VERSION 5.8 ;
BUSBITCHARS "[]" ;
DIVIDERCHAR "/" ;
UNITS
    DATABASE MICRONS 1000 ;
END UNITS

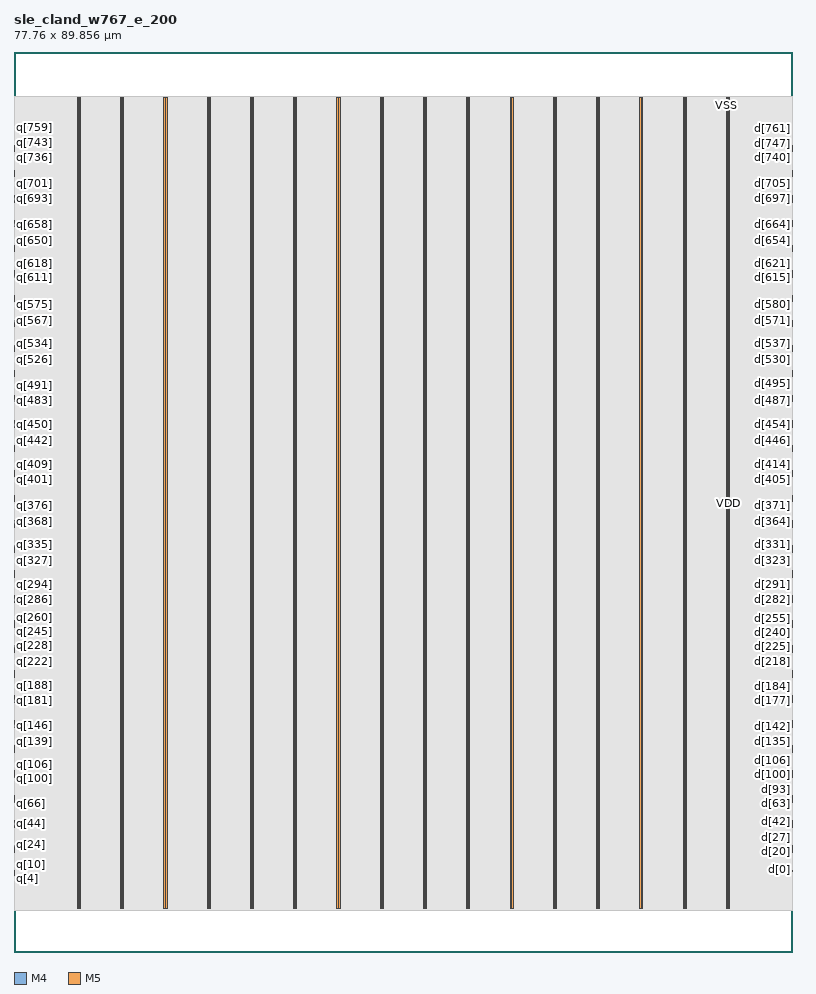
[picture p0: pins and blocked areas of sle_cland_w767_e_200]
MACRO sle_cland_w767_e_200
  FOREIGN sle_cland_w767_e_200 0 0 ;
  CLASS BLOCK ;
  SIZE 77.76 BY 89.856 ;
  PIN clk
    DIRECTION INPUT ;
    USE SIGNAL ;
    PORT
      LAYER M4 ;
        RECT  0 44.448 0.084 44.472 ;
    END
  END clk
  PIN d[0]
    DIRECTION INPUT ;
    USE SIGNAL ;
    PORT
      LAYER M4 ;
        RECT  77.676 8.256 77.76 8.28 ;
    END
  END d[0]
  PIN d[100]
    DIRECTION INPUT ;
    USE SIGNAL ;
    PORT
      LAYER M4 ;
        RECT  77.676 17.664 77.76 17.688 ;
    END
  END d[100]
  PIN d[101]
    DIRECTION INPUT ;
    USE SIGNAL ;
    PORT
      LAYER M4 ;
        RECT  77.676 17.76 77.76 17.784 ;
    END
  END d[101]
  PIN d[102]
    DIRECTION INPUT ;
    USE SIGNAL ;
    PORT
      LAYER M4 ;
        RECT  77.676 17.856 77.76 17.88 ;
    END
  END d[102]
  PIN d[103]
    DIRECTION INPUT ;
    USE SIGNAL ;
    PORT
      LAYER M4 ;
        RECT  77.676 17.952 77.76 17.976 ;
    END
  END d[103]
  PIN d[104]
    DIRECTION INPUT ;
    USE SIGNAL ;
    PORT
      LAYER M4 ;
        RECT  77.676 18.144 77.76 18.168 ;
    END
  END d[104]
  PIN d[105]
    DIRECTION INPUT ;
    USE SIGNAL ;
    PORT
      LAYER M4 ;
        RECT  77.676 18.048 77.76 18.072 ;
    END
  END d[105]
  PIN d[106]
    DIRECTION INPUT ;
    USE SIGNAL ;
    PORT
      LAYER M4 ;
        RECT  77.676 18.336 77.76 18.36 ;
    END
  END d[106]
  PIN d[107]
    DIRECTION INPUT ;
    USE SIGNAL ;
    PORT
      LAYER M4 ;
        RECT  77.676 18.24 77.76 18.264 ;
    END
  END d[107]
  PIN d[108]
    DIRECTION INPUT ;
    USE SIGNAL ;
    PORT
      LAYER M4 ;
        RECT  77.676 18.432 77.76 18.456 ;
    END
  END d[108]
  PIN d[109]
    DIRECTION INPUT ;
    USE SIGNAL ;
    PORT
      LAYER M4 ;
        RECT  77.676 18.528 77.76 18.552 ;
    END
  END d[109]
  PIN d[10]
    DIRECTION INPUT ;
    USE SIGNAL ;
    PORT
      LAYER M4 ;
        RECT  77.676 9.12 77.76 9.144 ;
    END
  END d[10]
  PIN d[110]
    DIRECTION INPUT ;
    USE SIGNAL ;
    PORT
      LAYER M4 ;
        RECT  77.676 18.624 77.76 18.648 ;
    END
  END d[110]
  PIN d[111]
    DIRECTION INPUT ;
    USE SIGNAL ;
    PORT
      LAYER M4 ;
        RECT  77.676 18.72 77.76 18.744 ;
    END
  END d[111]
  PIN d[112]
    DIRECTION INPUT ;
    USE SIGNAL ;
    PORT
      LAYER M4 ;
        RECT  77.676 18.816 77.76 18.84 ;
    END
  END d[112]
  PIN d[113]
    DIRECTION INPUT ;
    USE SIGNAL ;
    PORT
      LAYER M4 ;
        RECT  77.676 18.912 77.76 18.936 ;
    END
  END d[113]
  PIN d[114]
    DIRECTION INPUT ;
    USE SIGNAL ;
    PORT
      LAYER M4 ;
        RECT  77.676 19.008 77.76 19.032 ;
    END
  END d[114]
  PIN d[115]
    DIRECTION INPUT ;
    USE SIGNAL ;
    PORT
      LAYER M4 ;
        RECT  77.676 19.104 77.76 19.128 ;
    END
  END d[115]
  PIN d[116]
    DIRECTION INPUT ;
    USE SIGNAL ;
    PORT
      LAYER M4 ;
        RECT  77.676 19.2 77.76 19.224 ;
    END
  END d[116]
  PIN d[117]
    DIRECTION INPUT ;
    USE SIGNAL ;
    PORT
      LAYER M4 ;
        RECT  77.676 19.296 77.76 19.32 ;
    END
  END d[117]
  PIN d[118]
    DIRECTION INPUT ;
    USE SIGNAL ;
    PORT
      LAYER M4 ;
        RECT  77.676 19.392 77.76 19.416 ;
    END
  END d[118]
  PIN d[119]
    DIRECTION INPUT ;
    USE SIGNAL ;
    PORT
      LAYER M4 ;
        RECT  77.676 19.488 77.76 19.512 ;
    END
  END d[119]
  PIN d[11]
    DIRECTION INPUT ;
    USE SIGNAL ;
    PORT
      LAYER M4 ;
        RECT  77.676 9.024 77.76 9.048 ;
    END
  END d[11]
  PIN d[120]
    DIRECTION INPUT ;
    USE SIGNAL ;
    PORT
      LAYER M4 ;
        RECT  77.676 19.584 77.76 19.608 ;
    END
  END d[120]
  PIN d[121]
    DIRECTION INPUT ;
    USE SIGNAL ;
    PORT
      LAYER M4 ;
        RECT  77.676 19.68 77.76 19.704 ;
    END
  END d[121]
  PIN d[122]
    DIRECTION INPUT ;
    USE SIGNAL ;
    PORT
      LAYER M4 ;
        RECT  77.676 19.776 77.76 19.8 ;
    END
  END d[122]
  PIN d[123]
    DIRECTION INPUT ;
    USE SIGNAL ;
    PORT
      LAYER M4 ;
        RECT  77.676 19.872 77.76 19.896 ;
    END
  END d[123]
  PIN d[124]
    DIRECTION INPUT ;
    USE SIGNAL ;
    PORT
      LAYER M4 ;
        RECT  77.676 20.16 77.76 20.184 ;
    END
  END d[124]
  PIN d[125]
    DIRECTION INPUT ;
    USE SIGNAL ;
    PORT
      LAYER M4 ;
        RECT  77.676 19.968 77.76 19.992 ;
    END
  END d[125]
  PIN d[126]
    DIRECTION INPUT ;
    USE SIGNAL ;
    PORT
      LAYER M4 ;
        RECT  77.676 20.256 77.76 20.28 ;
    END
  END d[126]
  PIN d[127]
    DIRECTION INPUT ;
    USE SIGNAL ;
    PORT
      LAYER M4 ;
        RECT  77.676 20.064 77.76 20.088 ;
    END
  END d[127]
  PIN d[128]
    DIRECTION INPUT ;
    USE SIGNAL ;
    PORT
      LAYER M4 ;
        RECT  77.676 20.352 77.76 20.376 ;
    END
  END d[128]
  PIN d[129]
    DIRECTION INPUT ;
    USE SIGNAL ;
    PORT
      LAYER M4 ;
        RECT  77.676 20.448 77.76 20.472 ;
    END
  END d[129]
  PIN d[12]
    DIRECTION INPUT ;
    USE SIGNAL ;
    PORT
      LAYER M4 ;
        RECT  77.676 9.216 77.76 9.24 ;
    END
  END d[12]
  PIN d[130]
    DIRECTION INPUT ;
    USE SIGNAL ;
    PORT
      LAYER M4 ;
        RECT  77.676 20.544 77.76 20.568 ;
    END
  END d[130]
  PIN d[131]
    DIRECTION INPUT ;
    USE SIGNAL ;
    PORT
      LAYER M4 ;
        RECT  77.676 20.64 77.76 20.664 ;
    END
  END d[131]
  PIN d[132]
    DIRECTION INPUT ;
    USE SIGNAL ;
    PORT
      LAYER M4 ;
        RECT  77.676 20.736 77.76 20.76 ;
    END
  END d[132]
  PIN d[133]
    DIRECTION INPUT ;
    USE SIGNAL ;
    PORT
      LAYER M4 ;
        RECT  77.676 20.832 77.76 20.856 ;
    END
  END d[133]
  PIN d[134]
    DIRECTION INPUT ;
    USE SIGNAL ;
    PORT
      LAYER M4 ;
        RECT  77.676 20.928 77.76 20.952 ;
    END
  END d[134]
  PIN d[135]
    DIRECTION INPUT ;
    USE SIGNAL ;
    PORT
      LAYER M4 ;
        RECT  77.676 21.024 77.76 21.048 ;
    END
  END d[135]
  PIN d[136]
    DIRECTION INPUT ;
    USE SIGNAL ;
    PORT
      LAYER M4 ;
        RECT  77.676 21.12 77.76 21.144 ;
    END
  END d[136]
  PIN d[137]
    DIRECTION INPUT ;
    USE SIGNAL ;
    PORT
      LAYER M4 ;
        RECT  77.676 21.216 77.76 21.24 ;
    END
  END d[137]
  PIN d[138]
    DIRECTION INPUT ;
    USE SIGNAL ;
    PORT
      LAYER M4 ;
        RECT  77.676 21.312 77.76 21.336 ;
    END
  END d[138]
  PIN d[139]
    DIRECTION INPUT ;
    USE SIGNAL ;
    PORT
      LAYER M4 ;
        RECT  77.676 21.408 77.76 21.432 ;
    END
  END d[139]
  PIN d[13]
    DIRECTION INPUT ;
    USE SIGNAL ;
    PORT
      LAYER M4 ;
        RECT  77.676 9.312 77.76 9.336 ;
    END
  END d[13]
  PIN d[140]
    DIRECTION INPUT ;
    USE SIGNAL ;
    PORT
      LAYER M4 ;
        RECT  77.676 21.504 77.76 21.528 ;
    END
  END d[140]
  PIN d[141]
    DIRECTION INPUT ;
    USE SIGNAL ;
    PORT
      LAYER M4 ;
        RECT  77.676 21.6 77.76 21.624 ;
    END
  END d[141]
  PIN d[142]
    DIRECTION INPUT ;
    USE SIGNAL ;
    PORT
      LAYER M4 ;
        RECT  77.676 21.696 77.76 21.72 ;
    END
  END d[142]
  PIN d[143]
    DIRECTION INPUT ;
    USE SIGNAL ;
    PORT
      LAYER M4 ;
        RECT  77.676 21.792 77.76 21.816 ;
    END
  END d[143]
  PIN d[144]
    DIRECTION INPUT ;
    USE SIGNAL ;
    PORT
      LAYER M4 ;
        RECT  77.676 21.888 77.76 21.912 ;
    END
  END d[144]
  PIN d[145]
    DIRECTION INPUT ;
    USE SIGNAL ;
    PORT
      LAYER M4 ;
        RECT  77.676 21.984 77.76 22.008 ;
    END
  END d[145]
  PIN d[146]
    DIRECTION INPUT ;
    USE SIGNAL ;
    PORT
      LAYER M4 ;
        RECT  77.676 22.176 77.76 22.2 ;
    END
  END d[146]
  PIN d[147]
    DIRECTION INPUT ;
    USE SIGNAL ;
    PORT
      LAYER M4 ;
        RECT  77.676 22.08 77.76 22.104 ;
    END
  END d[147]
  PIN d[148]
    DIRECTION INPUT ;
    USE SIGNAL ;
    PORT
      LAYER M4 ;
        RECT  77.676 22.272 77.76 22.296 ;
    END
  END d[148]
  PIN d[149]
    DIRECTION INPUT ;
    USE SIGNAL ;
    PORT
      LAYER M4 ;
        RECT  77.676 22.368 77.76 22.392 ;
    END
  END d[149]
  PIN d[14]
    DIRECTION INPUT ;
    USE SIGNAL ;
    PORT
      LAYER M4 ;
        RECT  77.676 9.504 77.76 9.528 ;
    END
  END d[14]
  PIN d[150]
    DIRECTION INPUT ;
    USE SIGNAL ;
    PORT
      LAYER M4 ;
        RECT  77.676 22.464 77.76 22.488 ;
    END
  END d[150]
  PIN d[151]
    DIRECTION INPUT ;
    USE SIGNAL ;
    PORT
      LAYER M4 ;
        RECT  77.676 22.56 77.76 22.584 ;
    END
  END d[151]
  PIN d[152]
    DIRECTION INPUT ;
    USE SIGNAL ;
    PORT
      LAYER M4 ;
        RECT  77.676 22.656 77.76 22.68 ;
    END
  END d[152]
  PIN d[153]
    DIRECTION INPUT ;
    USE SIGNAL ;
    PORT
      LAYER M4 ;
        RECT  77.676 22.752 77.76 22.776 ;
    END
  END d[153]
  PIN d[154]
    DIRECTION INPUT ;
    USE SIGNAL ;
    PORT
      LAYER M4 ;
        RECT  77.676 22.848 77.76 22.872 ;
    END
  END d[154]
  PIN d[155]
    DIRECTION INPUT ;
    USE SIGNAL ;
    PORT
      LAYER M4 ;
        RECT  77.676 22.944 77.76 22.968 ;
    END
  END d[155]
  PIN d[156]
    DIRECTION INPUT ;
    USE SIGNAL ;
    PORT
      LAYER M4 ;
        RECT  77.676 23.04 77.76 23.064 ;
    END
  END d[156]
  PIN d[157]
    DIRECTION INPUT ;
    USE SIGNAL ;
    PORT
      LAYER M4 ;
        RECT  77.676 23.136 77.76 23.16 ;
    END
  END d[157]
  PIN d[158]
    DIRECTION INPUT ;
    USE SIGNAL ;
    PORT
      LAYER M4 ;
        RECT  77.676 23.232 77.76 23.256 ;
    END
  END d[158]
  PIN d[159]
    DIRECTION INPUT ;
    USE SIGNAL ;
    PORT
      LAYER M4 ;
        RECT  77.676 23.328 77.76 23.352 ;
    END
  END d[159]
  PIN d[15]
    DIRECTION INPUT ;
    USE SIGNAL ;
    PORT
      LAYER M4 ;
        RECT  77.676 9.408 77.76 9.432 ;
    END
  END d[15]
  PIN d[160]
    DIRECTION INPUT ;
    USE SIGNAL ;
    PORT
      LAYER M4 ;
        RECT  77.676 23.424 77.76 23.448 ;
    END
  END d[160]
  PIN d[161]
    DIRECTION INPUT ;
    USE SIGNAL ;
    PORT
      LAYER M4 ;
        RECT  77.676 23.52 77.76 23.544 ;
    END
  END d[161]
  PIN d[162]
    DIRECTION INPUT ;
    USE SIGNAL ;
    PORT
      LAYER M4 ;
        RECT  77.676 23.616 77.76 23.64 ;
    END
  END d[162]
  PIN d[163]
    DIRECTION INPUT ;
    USE SIGNAL ;
    PORT
      LAYER M4 ;
        RECT  77.676 23.712 77.76 23.736 ;
    END
  END d[163]
  PIN d[164]
    DIRECTION INPUT ;
    USE SIGNAL ;
    PORT
      LAYER M4 ;
        RECT  77.676 23.808 77.76 23.832 ;
    END
  END d[164]
  PIN d[165]
    DIRECTION INPUT ;
    USE SIGNAL ;
    PORT
      LAYER M4 ;
        RECT  77.676 23.904 77.76 23.928 ;
    END
  END d[165]
  PIN d[166]
    DIRECTION INPUT ;
    USE SIGNAL ;
    PORT
      LAYER M4 ;
        RECT  77.676 24.096 77.76 24.12 ;
    END
  END d[166]
  PIN d[167]
    DIRECTION INPUT ;
    USE SIGNAL ;
    PORT
      LAYER M4 ;
        RECT  77.676 24 77.76 24.024 ;
    END
  END d[167]
  PIN d[168]
    DIRECTION INPUT ;
    USE SIGNAL ;
    PORT
      LAYER M4 ;
        RECT  77.676 24.288 77.76 24.312 ;
    END
  END d[168]
  PIN d[169]
    DIRECTION INPUT ;
    USE SIGNAL ;
    PORT
      LAYER M4 ;
        RECT  77.676 24.192 77.76 24.216 ;
    END
  END d[169]
  PIN d[16]
    DIRECTION INPUT ;
    USE SIGNAL ;
    PORT
      LAYER M4 ;
        RECT  77.676 9.6 77.76 9.624 ;
    END
  END d[16]
  PIN d[170]
    DIRECTION INPUT ;
    USE SIGNAL ;
    PORT
      LAYER M4 ;
        RECT  77.676 24.384 77.76 24.408 ;
    END
  END d[170]
  PIN d[171]
    DIRECTION INPUT ;
    USE SIGNAL ;
    PORT
      LAYER M4 ;
        RECT  77.676 24.48 77.76 24.504 ;
    END
  END d[171]
  PIN d[172]
    DIRECTION INPUT ;
    USE SIGNAL ;
    PORT
      LAYER M4 ;
        RECT  77.676 24.576 77.76 24.6 ;
    END
  END d[172]
  PIN d[173]
    DIRECTION INPUT ;
    USE SIGNAL ;
    PORT
      LAYER M4 ;
        RECT  77.676 24.672 77.76 24.696 ;
    END
  END d[173]
  PIN d[174]
    DIRECTION INPUT ;
    USE SIGNAL ;
    PORT
      LAYER M4 ;
        RECT  77.676 24.768 77.76 24.792 ;
    END
  END d[174]
  PIN d[175]
    DIRECTION INPUT ;
    USE SIGNAL ;
    PORT
      LAYER M4 ;
        RECT  77.676 24.864 77.76 24.888 ;
    END
  END d[175]
  PIN d[176]
    DIRECTION INPUT ;
    USE SIGNAL ;
    PORT
      LAYER M4 ;
        RECT  77.676 24.96 77.76 24.984 ;
    END
  END d[176]
  PIN d[177]
    DIRECTION INPUT ;
    USE SIGNAL ;
    PORT
      LAYER M4 ;
        RECT  77.676 25.056 77.76 25.08 ;
    END
  END d[177]
  PIN d[178]
    DIRECTION INPUT ;
    USE SIGNAL ;
    PORT
      LAYER M4 ;
        RECT  77.676 25.152 77.76 25.176 ;
    END
  END d[178]
  PIN d[179]
    DIRECTION INPUT ;
    USE SIGNAL ;
    PORT
      LAYER M4 ;
        RECT  77.676 25.248 77.76 25.272 ;
    END
  END d[179]
  PIN d[17]
    DIRECTION INPUT ;
    USE SIGNAL ;
    PORT
      LAYER M4 ;
        RECT  77.676 9.696 77.76 9.72 ;
    END
  END d[17]
  PIN d[180]
    DIRECTION INPUT ;
    USE SIGNAL ;
    PORT
      LAYER M4 ;
        RECT  77.676 25.344 77.76 25.368 ;
    END
  END d[180]
  PIN d[181]
    DIRECTION INPUT ;
    USE SIGNAL ;
    PORT
      LAYER M4 ;
        RECT  77.676 25.44 77.76 25.464 ;
    END
  END d[181]
  PIN d[182]
    DIRECTION INPUT ;
    USE SIGNAL ;
    PORT
      LAYER M4 ;
        RECT  77.676 25.536 77.76 25.56 ;
    END
  END d[182]
  PIN d[183]
    DIRECTION INPUT ;
    USE SIGNAL ;
    PORT
      LAYER M4 ;
        RECT  77.676 25.632 77.76 25.656 ;
    END
  END d[183]
  PIN d[184]
    DIRECTION INPUT ;
    USE SIGNAL ;
    PORT
      LAYER M4 ;
        RECT  77.676 25.728 77.76 25.752 ;
    END
  END d[184]
  PIN d[185]
    DIRECTION INPUT ;
    USE SIGNAL ;
    PORT
      LAYER M4 ;
        RECT  77.676 25.92 77.76 25.944 ;
    END
  END d[185]
  PIN d[186]
    DIRECTION INPUT ;
    USE SIGNAL ;
    PORT
      LAYER M4 ;
        RECT  77.676 25.824 77.76 25.848 ;
    END
  END d[186]
  PIN d[187]
    DIRECTION INPUT ;
    USE SIGNAL ;
    PORT
      LAYER M4 ;
        RECT  77.676 26.016 77.76 26.04 ;
    END
  END d[187]
  PIN d[188]
    DIRECTION INPUT ;
    USE SIGNAL ;
    PORT
      LAYER M4 ;
        RECT  77.676 26.208 77.76 26.232 ;
    END
  END d[188]
  PIN d[189]
    DIRECTION INPUT ;
    USE SIGNAL ;
    PORT
      LAYER M4 ;
        RECT  77.676 26.112 77.76 26.136 ;
    END
  END d[189]
  PIN d[18]
    DIRECTION INPUT ;
    USE SIGNAL ;
    PORT
      LAYER M4 ;
        RECT  77.676 9.792 77.76 9.816 ;
    END
  END d[18]
  PIN d[190]
    DIRECTION INPUT ;
    USE SIGNAL ;
    PORT
      LAYER M4 ;
        RECT  77.676 26.304 77.76 26.328 ;
    END
  END d[190]
  PIN d[191]
    DIRECTION INPUT ;
    USE SIGNAL ;
    PORT
      LAYER M4 ;
        RECT  77.676 26.4 77.76 26.424 ;
    END
  END d[191]
  PIN d[192]
    DIRECTION INPUT ;
    USE SIGNAL ;
    PORT
      LAYER M4 ;
        RECT  77.676 26.496 77.76 26.52 ;
    END
  END d[192]
  PIN d[193]
    DIRECTION INPUT ;
    USE SIGNAL ;
    PORT
      LAYER M4 ;
        RECT  77.676 26.592 77.76 26.616 ;
    END
  END d[193]
  PIN d[194]
    DIRECTION INPUT ;
    USE SIGNAL ;
    PORT
      LAYER M4 ;
        RECT  77.676 26.688 77.76 26.712 ;
    END
  END d[194]
  PIN d[195]
    DIRECTION INPUT ;
    USE SIGNAL ;
    PORT
      LAYER M4 ;
        RECT  77.676 26.784 77.76 26.808 ;
    END
  END d[195]
  PIN d[196]
    DIRECTION INPUT ;
    USE SIGNAL ;
    PORT
      LAYER M4 ;
        RECT  77.676 26.88 77.76 26.904 ;
    END
  END d[196]
  PIN d[197]
    DIRECTION INPUT ;
    USE SIGNAL ;
    PORT
      LAYER M4 ;
        RECT  77.676 26.976 77.76 27 ;
    END
  END d[197]
  PIN d[198]
    DIRECTION INPUT ;
    USE SIGNAL ;
    PORT
      LAYER M4 ;
        RECT  77.676 27.072 77.76 27.096 ;
    END
  END d[198]
  PIN d[199]
    DIRECTION INPUT ;
    USE SIGNAL ;
    PORT
      LAYER M4 ;
        RECT  77.676 27.168 77.76 27.192 ;
    END
  END d[199]
  PIN d[19]
    DIRECTION INPUT ;
    USE SIGNAL ;
    PORT
      LAYER M4 ;
        RECT  77.676 9.888 77.76 9.912 ;
    END
  END d[19]
  PIN d[1]
    DIRECTION INPUT ;
    USE SIGNAL ;
    PORT
      LAYER M4 ;
        RECT  77.676 8.064 77.76 8.088 ;
    END
  END d[1]
  PIN d[200]
    DIRECTION INPUT ;
    USE SIGNAL ;
    PORT
      LAYER M4 ;
        RECT  77.676 27.264 77.76 27.288 ;
    END
  END d[200]
  PIN d[201]
    DIRECTION INPUT ;
    USE SIGNAL ;
    PORT
      LAYER M4 ;
        RECT  77.676 27.36 77.76 27.384 ;
    END
  END d[201]
  PIN d[202]
    DIRECTION INPUT ;
    USE SIGNAL ;
    PORT
      LAYER M4 ;
        RECT  77.676 27.456 77.76 27.48 ;
    END
  END d[202]
  PIN d[203]
    DIRECTION INPUT ;
    USE SIGNAL ;
    PORT
      LAYER M4 ;
        RECT  77.676 27.552 77.76 27.576 ;
    END
  END d[203]
  PIN d[204]
    DIRECTION INPUT ;
    USE SIGNAL ;
    PORT
      LAYER M4 ;
        RECT  77.676 27.648 77.76 27.672 ;
    END
  END d[204]
  PIN d[205]
    DIRECTION INPUT ;
    USE SIGNAL ;
    PORT
      LAYER M4 ;
        RECT  77.676 27.744 77.76 27.768 ;
    END
  END d[205]
  PIN d[206]
    DIRECTION INPUT ;
    USE SIGNAL ;
    PORT
      LAYER M4 ;
        RECT  77.676 27.84 77.76 27.864 ;
    END
  END d[206]
  PIN d[207]
    DIRECTION INPUT ;
    USE SIGNAL ;
    PORT
      LAYER M4 ;
        RECT  77.676 27.936 77.76 27.96 ;
    END
  END d[207]
  PIN d[208]
    DIRECTION INPUT ;
    USE SIGNAL ;
    PORT
      LAYER M4 ;
        RECT  77.676 28.128 77.76 28.152 ;
    END
  END d[208]
  PIN d[209]
    DIRECTION INPUT ;
    USE SIGNAL ;
    PORT
      LAYER M4 ;
        RECT  77.676 28.032 77.76 28.056 ;
    END
  END d[209]
  PIN d[20]
    DIRECTION INPUT ;
    USE SIGNAL ;
    PORT
      LAYER M4 ;
        RECT  77.676 9.984 77.76 10.008 ;
    END
  END d[20]
  PIN d[210]
    DIRECTION INPUT ;
    USE SIGNAL ;
    PORT
      LAYER M4 ;
        RECT  77.676 28.224 77.76 28.248 ;
    END
  END d[210]
  PIN d[211]
    DIRECTION INPUT ;
    USE SIGNAL ;
    PORT
      LAYER M4 ;
        RECT  77.676 28.32 77.76 28.344 ;
    END
  END d[211]
  PIN d[212]
    DIRECTION INPUT ;
    USE SIGNAL ;
    PORT
      LAYER M4 ;
        RECT  77.676 28.416 77.76 28.44 ;
    END
  END d[212]
  PIN d[213]
    DIRECTION INPUT ;
    USE SIGNAL ;
    PORT
      LAYER M4 ;
        RECT  77.676 28.512 77.76 28.536 ;
    END
  END d[213]
  PIN d[214]
    DIRECTION INPUT ;
    USE SIGNAL ;
    PORT
      LAYER M4 ;
        RECT  77.676 28.608 77.76 28.632 ;
    END
  END d[214]
  PIN d[215]
    DIRECTION INPUT ;
    USE SIGNAL ;
    PORT
      LAYER M4 ;
        RECT  77.676 28.704 77.76 28.728 ;
    END
  END d[215]
  PIN d[216]
    DIRECTION INPUT ;
    USE SIGNAL ;
    PORT
      LAYER M4 ;
        RECT  77.676 28.8 77.76 28.824 ;
    END
  END d[216]
  PIN d[217]
    DIRECTION INPUT ;
    USE SIGNAL ;
    PORT
      LAYER M4 ;
        RECT  77.676 28.896 77.76 28.92 ;
    END
  END d[217]
  PIN d[218]
    DIRECTION INPUT ;
    USE SIGNAL ;
    PORT
      LAYER M4 ;
        RECT  77.676 28.992 77.76 29.016 ;
    END
  END d[218]
  PIN d[219]
    DIRECTION INPUT ;
    USE SIGNAL ;
    PORT
      LAYER M4 ;
        RECT  77.676 29.088 77.76 29.112 ;
    END
  END d[219]
  PIN d[21]
    DIRECTION INPUT ;
    USE SIGNAL ;
    PORT
      LAYER M4 ;
        RECT  77.676 10.08 77.76 10.104 ;
    END
  END d[21]
  PIN d[220]
    DIRECTION INPUT ;
    USE SIGNAL ;
    PORT
      LAYER M4 ;
        RECT  77.676 29.184 77.76 29.208 ;
    END
  END d[220]
  PIN d[221]
    DIRECTION INPUT ;
    USE SIGNAL ;
    PORT
      LAYER M4 ;
        RECT  77.676 29.28 77.76 29.304 ;
    END
  END d[221]
  PIN d[222]
    DIRECTION INPUT ;
    USE SIGNAL ;
    PORT
      LAYER M4 ;
        RECT  77.676 29.376 77.76 29.4 ;
    END
  END d[222]
  PIN d[223]
    DIRECTION INPUT ;
    USE SIGNAL ;
    PORT
      LAYER M4 ;
        RECT  77.676 29.472 77.76 29.496 ;
    END
  END d[223]
  PIN d[224]
    DIRECTION INPUT ;
    USE SIGNAL ;
    PORT
      LAYER M4 ;
        RECT  77.676 29.568 77.76 29.592 ;
    END
  END d[224]
  PIN d[225]
    DIRECTION INPUT ;
    USE SIGNAL ;
    PORT
      LAYER M4 ;
        RECT  77.676 29.664 77.76 29.688 ;
    END
  END d[225]
  PIN d[226]
    DIRECTION INPUT ;
    USE SIGNAL ;
    PORT
      LAYER M4 ;
        RECT  77.676 29.76 77.76 29.784 ;
    END
  END d[226]
  PIN d[227]
    DIRECTION INPUT ;
    USE SIGNAL ;
    PORT
      LAYER M4 ;
        RECT  77.676 29.856 77.76 29.88 ;
    END
  END d[227]
  PIN d[228]
    DIRECTION INPUT ;
    USE SIGNAL ;
    PORT
      LAYER M4 ;
        RECT  77.676 30.144 77.76 30.168 ;
    END
  END d[228]
  PIN d[229]
    DIRECTION INPUT ;
    USE SIGNAL ;
    PORT
      LAYER M4 ;
        RECT  77.676 29.952 77.76 29.976 ;
    END
  END d[229]
  PIN d[22]
    DIRECTION INPUT ;
    USE SIGNAL ;
    PORT
      LAYER M4 ;
        RECT  77.676 10.272 77.76 10.296 ;
    END
  END d[22]
  PIN d[230]
    DIRECTION INPUT ;
    USE SIGNAL ;
    PORT
      LAYER M4 ;
        RECT  77.676 30.24 77.76 30.264 ;
    END
  END d[230]
  PIN d[231]
    DIRECTION INPUT ;
    USE SIGNAL ;
    PORT
      LAYER M4 ;
        RECT  77.676 30.048 77.76 30.072 ;
    END
  END d[231]
  PIN d[232]
    DIRECTION INPUT ;
    USE SIGNAL ;
    PORT
      LAYER M4 ;
        RECT  77.676 30.336 77.76 30.36 ;
    END
  END d[232]
  PIN d[233]
    DIRECTION INPUT ;
    USE SIGNAL ;
    PORT
      LAYER M4 ;
        RECT  77.676 30.432 77.76 30.456 ;
    END
  END d[233]
  PIN d[234]
    DIRECTION INPUT ;
    USE SIGNAL ;
    PORT
      LAYER M4 ;
        RECT  77.676 30.528 77.76 30.552 ;
    END
  END d[234]
  PIN d[235]
    DIRECTION INPUT ;
    USE SIGNAL ;
    PORT
      LAYER M4 ;
        RECT  77.676 30.624 77.76 30.648 ;
    END
  END d[235]
  PIN d[236]
    DIRECTION INPUT ;
    USE SIGNAL ;
    PORT
      LAYER M4 ;
        RECT  77.676 30.72 77.76 30.744 ;
    END
  END d[236]
  PIN d[237]
    DIRECTION INPUT ;
    USE SIGNAL ;
    PORT
      LAYER M4 ;
        RECT  77.676 30.816 77.76 30.84 ;
    END
  END d[237]
  PIN d[238]
    DIRECTION INPUT ;
    USE SIGNAL ;
    PORT
      LAYER M4 ;
        RECT  77.676 30.912 77.76 30.936 ;
    END
  END d[238]
  PIN d[239]
    DIRECTION INPUT ;
    USE SIGNAL ;
    PORT
      LAYER M4 ;
        RECT  77.676 31.008 77.76 31.032 ;
    END
  END d[239]
  PIN d[23]
    DIRECTION INPUT ;
    USE SIGNAL ;
    PORT
      LAYER M4 ;
        RECT  77.676 10.176 77.76 10.2 ;
    END
  END d[23]
  PIN d[240]
    DIRECTION INPUT ;
    USE SIGNAL ;
    PORT
      LAYER M4 ;
        RECT  77.676 31.104 77.76 31.128 ;
    END
  END d[240]
  PIN d[241]
    DIRECTION INPUT ;
    USE SIGNAL ;
    PORT
      LAYER M4 ;
        RECT  77.676 31.2 77.76 31.224 ;
    END
  END d[241]
  PIN d[242]
    DIRECTION INPUT ;
    USE SIGNAL ;
    PORT
      LAYER M4 ;
        RECT  77.676 31.296 77.76 31.32 ;
    END
  END d[242]
  PIN d[243]
    DIRECTION INPUT ;
    USE SIGNAL ;
    PORT
      LAYER M4 ;
        RECT  77.676 31.392 77.76 31.416 ;
    END
  END d[243]
  PIN d[244]
    DIRECTION INPUT ;
    USE SIGNAL ;
    PORT
      LAYER M4 ;
        RECT  77.676 31.488 77.76 31.512 ;
    END
  END d[244]
  PIN d[245]
    DIRECTION INPUT ;
    USE SIGNAL ;
    PORT
      LAYER M4 ;
        RECT  77.676 31.584 77.76 31.608 ;
    END
  END d[245]
  PIN d[246]
    DIRECTION INPUT ;
    USE SIGNAL ;
    PORT
      LAYER M4 ;
        RECT  77.676 31.68 77.76 31.704 ;
    END
  END d[246]
  PIN d[247]
    DIRECTION INPUT ;
    USE SIGNAL ;
    PORT
      LAYER M4 ;
        RECT  77.676 31.872 77.76 31.896 ;
    END
  END d[247]
  PIN d[248]
    DIRECTION INPUT ;
    USE SIGNAL ;
    PORT
      LAYER M4 ;
        RECT  77.676 31.776 77.76 31.8 ;
    END
  END d[248]
  PIN d[249]
    DIRECTION INPUT ;
    USE SIGNAL ;
    PORT
      LAYER M4 ;
        RECT  77.676 31.968 77.76 31.992 ;
    END
  END d[249]
  PIN d[24]
    DIRECTION INPUT ;
    USE SIGNAL ;
    PORT
      LAYER M4 ;
        RECT  77.676 10.368 77.76 10.392 ;
    END
  END d[24]
  PIN d[250]
    DIRECTION INPUT ;
    USE SIGNAL ;
    PORT
      LAYER M4 ;
        RECT  77.676 32.16 77.76 32.184 ;
    END
  END d[250]
  PIN d[251]
    DIRECTION INPUT ;
    USE SIGNAL ;
    PORT
      LAYER M4 ;
        RECT  77.676 32.064 77.76 32.088 ;
    END
  END d[251]
  PIN d[252]
    DIRECTION INPUT ;
    USE SIGNAL ;
    PORT
      LAYER M4 ;
        RECT  77.676 32.256 77.76 32.28 ;
    END
  END d[252]
  PIN d[253]
    DIRECTION INPUT ;
    USE SIGNAL ;
    PORT
      LAYER M4 ;
        RECT  77.676 32.352 77.76 32.376 ;
    END
  END d[253]
  PIN d[254]
    DIRECTION INPUT ;
    USE SIGNAL ;
    PORT
      LAYER M4 ;
        RECT  77.676 32.448 77.76 32.472 ;
    END
  END d[254]
  PIN d[255]
    DIRECTION INPUT ;
    USE SIGNAL ;
    PORT
      LAYER M4 ;
        RECT  77.676 32.544 77.76 32.568 ;
    END
  END d[255]
  PIN d[256]
    DIRECTION INPUT ;
    USE SIGNAL ;
    PORT
      LAYER M4 ;
        RECT  77.676 32.64 77.76 32.664 ;
    END
  END d[256]
  PIN d[257]
    DIRECTION INPUT ;
    USE SIGNAL ;
    PORT
      LAYER M4 ;
        RECT  77.676 32.736 77.76 32.76 ;
    END
  END d[257]
  PIN d[258]
    DIRECTION INPUT ;
    USE SIGNAL ;
    PORT
      LAYER M4 ;
        RECT  77.676 32.832 77.76 32.856 ;
    END
  END d[258]
  PIN d[259]
    DIRECTION INPUT ;
    USE SIGNAL ;
    PORT
      LAYER M4 ;
        RECT  77.676 32.928 77.76 32.952 ;
    END
  END d[259]
  PIN d[25]
    DIRECTION INPUT ;
    USE SIGNAL ;
    PORT
      LAYER M4 ;
        RECT  77.676 10.464 77.76 10.488 ;
    END
  END d[25]
  PIN d[260]
    DIRECTION INPUT ;
    USE SIGNAL ;
    PORT
      LAYER M4 ;
        RECT  77.676 33.024 77.76 33.048 ;
    END
  END d[260]
  PIN d[261]
    DIRECTION INPUT ;
    USE SIGNAL ;
    PORT
      LAYER M4 ;
        RECT  77.676 33.12 77.76 33.144 ;
    END
  END d[261]
  PIN d[262]
    DIRECTION INPUT ;
    USE SIGNAL ;
    PORT
      LAYER M4 ;
        RECT  77.676 33.216 77.76 33.24 ;
    END
  END d[262]
  PIN d[263]
    DIRECTION INPUT ;
    USE SIGNAL ;
    PORT
      LAYER M4 ;
        RECT  77.676 33.312 77.76 33.336 ;
    END
  END d[263]
  PIN d[264]
    DIRECTION INPUT ;
    USE SIGNAL ;
    PORT
      LAYER M4 ;
        RECT  77.676 33.408 77.76 33.432 ;
    END
  END d[264]
  PIN d[265]
    DIRECTION INPUT ;
    USE SIGNAL ;
    PORT
      LAYER M4 ;
        RECT  77.676 33.504 77.76 33.528 ;
    END
  END d[265]
  PIN d[266]
    DIRECTION INPUT ;
    USE SIGNAL ;
    PORT
      LAYER M4 ;
        RECT  77.676 33.6 77.76 33.624 ;
    END
  END d[266]
  PIN d[267]
    DIRECTION INPUT ;
    USE SIGNAL ;
    PORT
      LAYER M4 ;
        RECT  77.676 33.696 77.76 33.72 ;
    END
  END d[267]
  PIN d[268]
    DIRECTION INPUT ;
    USE SIGNAL ;
    PORT
      LAYER M4 ;
        RECT  77.676 33.792 77.76 33.816 ;
    END
  END d[268]
  PIN d[269]
    DIRECTION INPUT ;
    USE SIGNAL ;
    PORT
      LAYER M4 ;
        RECT  77.676 33.888 77.76 33.912 ;
    END
  END d[269]
  PIN d[26]
    DIRECTION INPUT ;
    USE SIGNAL ;
    PORT
      LAYER M4 ;
        RECT  77.676 10.56 77.76 10.584 ;
    END
  END d[26]
  PIN d[270]
    DIRECTION INPUT ;
    USE SIGNAL ;
    PORT
      LAYER M4 ;
        RECT  77.676 34.08 77.76 34.104 ;
    END
  END d[270]
  PIN d[271]
    DIRECTION INPUT ;
    USE SIGNAL ;
    PORT
      LAYER M4 ;
        RECT  77.676 33.984 77.76 34.008 ;
    END
  END d[271]
  PIN d[272]
    DIRECTION INPUT ;
    USE SIGNAL ;
    PORT
      LAYER M4 ;
        RECT  77.676 34.176 77.76 34.2 ;
    END
  END d[272]
  PIN d[273]
    DIRECTION INPUT ;
    USE SIGNAL ;
    PORT
      LAYER M4 ;
        RECT  77.676 34.272 77.76 34.296 ;
    END
  END d[273]
  PIN d[274]
    DIRECTION INPUT ;
    USE SIGNAL ;
    PORT
      LAYER M4 ;
        RECT  77.676 34.368 77.76 34.392 ;
    END
  END d[274]
  PIN d[275]
    DIRECTION INPUT ;
    USE SIGNAL ;
    PORT
      LAYER M4 ;
        RECT  77.676 34.464 77.76 34.488 ;
    END
  END d[275]
  PIN d[276]
    DIRECTION INPUT ;
    USE SIGNAL ;
    PORT
      LAYER M4 ;
        RECT  77.676 34.56 77.76 34.584 ;
    END
  END d[276]
  PIN d[277]
    DIRECTION INPUT ;
    USE SIGNAL ;
    PORT
      LAYER M4 ;
        RECT  77.676 34.656 77.76 34.68 ;
    END
  END d[277]
  PIN d[278]
    DIRECTION INPUT ;
    USE SIGNAL ;
    PORT
      LAYER M4 ;
        RECT  77.676 34.752 77.76 34.776 ;
    END
  END d[278]
  PIN d[279]
    DIRECTION INPUT ;
    USE SIGNAL ;
    PORT
      LAYER M4 ;
        RECT  77.676 34.848 77.76 34.872 ;
    END
  END d[279]
  PIN d[27]
    DIRECTION INPUT ;
    USE SIGNAL ;
    PORT
      LAYER M4 ;
        RECT  77.676 10.656 77.76 10.68 ;
    END
  END d[27]
  PIN d[280]
    DIRECTION INPUT ;
    USE SIGNAL ;
    PORT
      LAYER M4 ;
        RECT  77.676 34.944 77.76 34.968 ;
    END
  END d[280]
  PIN d[281]
    DIRECTION INPUT ;
    USE SIGNAL ;
    PORT
      LAYER M4 ;
        RECT  77.676 35.04 77.76 35.064 ;
    END
  END d[281]
  PIN d[282]
    DIRECTION INPUT ;
    USE SIGNAL ;
    PORT
      LAYER M4 ;
        RECT  77.676 35.136 77.76 35.16 ;
    END
  END d[282]
  PIN d[283]
    DIRECTION INPUT ;
    USE SIGNAL ;
    PORT
      LAYER M4 ;
        RECT  77.676 35.232 77.76 35.256 ;
    END
  END d[283]
  PIN d[284]
    DIRECTION INPUT ;
    USE SIGNAL ;
    PORT
      LAYER M4 ;
        RECT  77.676 35.328 77.76 35.352 ;
    END
  END d[284]
  PIN d[285]
    DIRECTION INPUT ;
    USE SIGNAL ;
    PORT
      LAYER M4 ;
        RECT  77.676 35.424 77.76 35.448 ;
    END
  END d[285]
  PIN d[286]
    DIRECTION INPUT ;
    USE SIGNAL ;
    PORT
      LAYER M4 ;
        RECT  77.676 35.52 77.76 35.544 ;
    END
  END d[286]
  PIN d[287]
    DIRECTION INPUT ;
    USE SIGNAL ;
    PORT
      LAYER M4 ;
        RECT  77.676 35.616 77.76 35.64 ;
    END
  END d[287]
  PIN d[288]
    DIRECTION INPUT ;
    USE SIGNAL ;
    PORT
      LAYER M4 ;
        RECT  77.676 35.712 77.76 35.736 ;
    END
  END d[288]
  PIN d[289]
    DIRECTION INPUT ;
    USE SIGNAL ;
    PORT
      LAYER M4 ;
        RECT  77.676 35.808 77.76 35.832 ;
    END
  END d[289]
  PIN d[28]
    DIRECTION INPUT ;
    USE SIGNAL ;
    PORT
      LAYER M4 ;
        RECT  77.676 10.752 77.76 10.776 ;
    END
  END d[28]
  PIN d[290]
    DIRECTION INPUT ;
    USE SIGNAL ;
    PORT
      LAYER M4 ;
        RECT  77.676 36 77.76 36.024 ;
    END
  END d[290]
  PIN d[291]
    DIRECTION INPUT ;
    USE SIGNAL ;
    PORT
      LAYER M4 ;
        RECT  77.676 35.904 77.76 35.928 ;
    END
  END d[291]
  PIN d[292]
    DIRECTION INPUT ;
    USE SIGNAL ;
    PORT
      LAYER M4 ;
        RECT  77.676 36.192 77.76 36.216 ;
    END
  END d[292]
  PIN d[293]
    DIRECTION INPUT ;
    USE SIGNAL ;
    PORT
      LAYER M4 ;
        RECT  77.676 36.096 77.76 36.12 ;
    END
  END d[293]
  PIN d[294]
    DIRECTION INPUT ;
    USE SIGNAL ;
    PORT
      LAYER M4 ;
        RECT  77.676 36.288 77.76 36.312 ;
    END
  END d[294]
  PIN d[295]
    DIRECTION INPUT ;
    USE SIGNAL ;
    PORT
      LAYER M4 ;
        RECT  77.676 36.384 77.76 36.408 ;
    END
  END d[295]
  PIN d[296]
    DIRECTION INPUT ;
    USE SIGNAL ;
    PORT
      LAYER M4 ;
        RECT  77.676 36.48 77.76 36.504 ;
    END
  END d[296]
  PIN d[297]
    DIRECTION INPUT ;
    USE SIGNAL ;
    PORT
      LAYER M4 ;
        RECT  77.676 36.576 77.76 36.6 ;
    END
  END d[297]
  PIN d[298]
    DIRECTION INPUT ;
    USE SIGNAL ;
    PORT
      LAYER M4 ;
        RECT  77.676 36.672 77.76 36.696 ;
    END
  END d[298]
  PIN d[299]
    DIRECTION INPUT ;
    USE SIGNAL ;
    PORT
      LAYER M4 ;
        RECT  77.676 36.768 77.76 36.792 ;
    END
  END d[299]
  PIN d[29]
    DIRECTION INPUT ;
    USE SIGNAL ;
    PORT
      LAYER M4 ;
        RECT  77.676 10.848 77.76 10.872 ;
    END
  END d[29]
  PIN d[2]
    DIRECTION INPUT ;
    USE SIGNAL ;
    PORT
      LAYER M4 ;
        RECT  77.676 8.352 77.76 8.376 ;
    END
  END d[2]
  PIN d[300]
    DIRECTION INPUT ;
    USE SIGNAL ;
    PORT
      LAYER M4 ;
        RECT  77.676 36.864 77.76 36.888 ;
    END
  END d[300]
  PIN d[301]
    DIRECTION INPUT ;
    USE SIGNAL ;
    PORT
      LAYER M4 ;
        RECT  77.676 36.96 77.76 36.984 ;
    END
  END d[301]
  PIN d[302]
    DIRECTION INPUT ;
    USE SIGNAL ;
    PORT
      LAYER M4 ;
        RECT  77.676 37.056 77.76 37.08 ;
    END
  END d[302]
  PIN d[303]
    DIRECTION INPUT ;
    USE SIGNAL ;
    PORT
      LAYER M4 ;
        RECT  77.676 37.152 77.76 37.176 ;
    END
  END d[303]
  PIN d[304]
    DIRECTION INPUT ;
    USE SIGNAL ;
    PORT
      LAYER M4 ;
        RECT  77.676 37.248 77.76 37.272 ;
    END
  END d[304]
  PIN d[305]
    DIRECTION INPUT ;
    USE SIGNAL ;
    PORT
      LAYER M4 ;
        RECT  77.676 37.344 77.76 37.368 ;
    END
  END d[305]
  PIN d[306]
    DIRECTION INPUT ;
    USE SIGNAL ;
    PORT
      LAYER M4 ;
        RECT  77.676 37.44 77.76 37.464 ;
    END
  END d[306]
  PIN d[307]
    DIRECTION INPUT ;
    USE SIGNAL ;
    PORT
      LAYER M4 ;
        RECT  77.676 37.536 77.76 37.56 ;
    END
  END d[307]
  PIN d[308]
    DIRECTION INPUT ;
    USE SIGNAL ;
    PORT
      LAYER M4 ;
        RECT  77.676 37.632 77.76 37.656 ;
    END
  END d[308]
  PIN d[309]
    DIRECTION INPUT ;
    USE SIGNAL ;
    PORT
      LAYER M4 ;
        RECT  77.676 37.824 77.76 37.848 ;
    END
  END d[309]
  PIN d[30]
    DIRECTION INPUT ;
    USE SIGNAL ;
    PORT
      LAYER M4 ;
        RECT  77.676 10.944 77.76 10.968 ;
    END
  END d[30]
  PIN d[310]
    DIRECTION INPUT ;
    USE SIGNAL ;
    PORT
      LAYER M4 ;
        RECT  77.676 37.728 77.76 37.752 ;
    END
  END d[310]
  PIN d[311]
    DIRECTION INPUT ;
    USE SIGNAL ;
    PORT
      LAYER M4 ;
        RECT  77.676 37.92 77.76 37.944 ;
    END
  END d[311]
  PIN d[312]
    DIRECTION INPUT ;
    USE SIGNAL ;
    PORT
      LAYER M4 ;
        RECT  77.676 38.112 77.76 38.136 ;
    END
  END d[312]
  PIN d[313]
    DIRECTION INPUT ;
    USE SIGNAL ;
    PORT
      LAYER M4 ;
        RECT  77.676 38.016 77.76 38.04 ;
    END
  END d[313]
  PIN d[314]
    DIRECTION INPUT ;
    USE SIGNAL ;
    PORT
      LAYER M4 ;
        RECT  77.676 38.208 77.76 38.232 ;
    END
  END d[314]
  PIN d[315]
    DIRECTION INPUT ;
    USE SIGNAL ;
    PORT
      LAYER M4 ;
        RECT  77.676 38.304 77.76 38.328 ;
    END
  END d[315]
  PIN d[316]
    DIRECTION INPUT ;
    USE SIGNAL ;
    PORT
      LAYER M4 ;
        RECT  77.676 38.4 77.76 38.424 ;
    END
  END d[316]
  PIN d[317]
    DIRECTION INPUT ;
    USE SIGNAL ;
    PORT
      LAYER M4 ;
        RECT  77.676 38.496 77.76 38.52 ;
    END
  END d[317]
  PIN d[318]
    DIRECTION INPUT ;
    USE SIGNAL ;
    PORT
      LAYER M4 ;
        RECT  77.676 38.592 77.76 38.616 ;
    END
  END d[318]
  PIN d[319]
    DIRECTION INPUT ;
    USE SIGNAL ;
    PORT
      LAYER M4 ;
        RECT  77.676 38.688 77.76 38.712 ;
    END
  END d[319]
  PIN d[31]
    DIRECTION INPUT ;
    USE SIGNAL ;
    PORT
      LAYER M4 ;
        RECT  77.676 11.04 77.76 11.064 ;
    END
  END d[31]
  PIN d[320]
    DIRECTION INPUT ;
    USE SIGNAL ;
    PORT
      LAYER M4 ;
        RECT  77.676 38.784 77.76 38.808 ;
    END
  END d[320]
  PIN d[321]
    DIRECTION INPUT ;
    USE SIGNAL ;
    PORT
      LAYER M4 ;
        RECT  77.676 38.88 77.76 38.904 ;
    END
  END d[321]
  PIN d[322]
    DIRECTION INPUT ;
    USE SIGNAL ;
    PORT
      LAYER M4 ;
        RECT  77.676 38.976 77.76 39 ;
    END
  END d[322]
  PIN d[323]
    DIRECTION INPUT ;
    USE SIGNAL ;
    PORT
      LAYER M4 ;
        RECT  77.676 39.072 77.76 39.096 ;
    END
  END d[323]
  PIN d[324]
    DIRECTION INPUT ;
    USE SIGNAL ;
    PORT
      LAYER M4 ;
        RECT  77.676 39.168 77.76 39.192 ;
    END
  END d[324]
  PIN d[325]
    DIRECTION INPUT ;
    USE SIGNAL ;
    PORT
      LAYER M4 ;
        RECT  77.676 39.264 77.76 39.288 ;
    END
  END d[325]
  PIN d[326]
    DIRECTION INPUT ;
    USE SIGNAL ;
    PORT
      LAYER M4 ;
        RECT  77.676 39.36 77.76 39.384 ;
    END
  END d[326]
  PIN d[327]
    DIRECTION INPUT ;
    USE SIGNAL ;
    PORT
      LAYER M4 ;
        RECT  77.676 39.456 77.76 39.48 ;
    END
  END d[327]
  PIN d[328]
    DIRECTION INPUT ;
    USE SIGNAL ;
    PORT
      LAYER M4 ;
        RECT  77.676 39.552 77.76 39.576 ;
    END
  END d[328]
  PIN d[329]
    DIRECTION INPUT ;
    USE SIGNAL ;
    PORT
      LAYER M4 ;
        RECT  77.676 39.648 77.76 39.672 ;
    END
  END d[329]
  PIN d[32]
    DIRECTION INPUT ;
    USE SIGNAL ;
    PORT
      LAYER M4 ;
        RECT  77.676 11.136 77.76 11.16 ;
    END
  END d[32]
  PIN d[330]
    DIRECTION INPUT ;
    USE SIGNAL ;
    PORT
      LAYER M4 ;
        RECT  77.676 39.744 77.76 39.768 ;
    END
  END d[330]
  PIN d[331]
    DIRECTION INPUT ;
    USE SIGNAL ;
    PORT
      LAYER M4 ;
        RECT  77.676 39.84 77.76 39.864 ;
    END
  END d[331]
  PIN d[332]
    DIRECTION INPUT ;
    USE SIGNAL ;
    PORT
      LAYER M4 ;
        RECT  77.676 40.032 77.76 40.056 ;
    END
  END d[332]
  PIN d[333]
    DIRECTION INPUT ;
    USE SIGNAL ;
    PORT
      LAYER M4 ;
        RECT  77.676 39.936 77.76 39.96 ;
    END
  END d[333]
  PIN d[334]
    DIRECTION INPUT ;
    USE SIGNAL ;
    PORT
      LAYER M4 ;
        RECT  77.676 40.128 77.76 40.152 ;
    END
  END d[334]
  PIN d[335]
    DIRECTION INPUT ;
    USE SIGNAL ;
    PORT
      LAYER M4 ;
        RECT  77.676 40.224 77.76 40.248 ;
    END
  END d[335]
  PIN d[336]
    DIRECTION INPUT ;
    USE SIGNAL ;
    PORT
      LAYER M4 ;
        RECT  77.676 40.32 77.76 40.344 ;
    END
  END d[336]
  PIN d[337]
    DIRECTION INPUT ;
    USE SIGNAL ;
    PORT
      LAYER M4 ;
        RECT  77.676 40.416 77.76 40.44 ;
    END
  END d[337]
  PIN d[338]
    DIRECTION INPUT ;
    USE SIGNAL ;
    PORT
      LAYER M4 ;
        RECT  77.676 40.512 77.76 40.536 ;
    END
  END d[338]
  PIN d[339]
    DIRECTION INPUT ;
    USE SIGNAL ;
    PORT
      LAYER M4 ;
        RECT  77.676 40.608 77.76 40.632 ;
    END
  END d[339]
  PIN d[33]
    DIRECTION INPUT ;
    USE SIGNAL ;
    PORT
      LAYER M4 ;
        RECT  77.676 11.232 77.76 11.256 ;
    END
  END d[33]
  PIN d[340]
    DIRECTION INPUT ;
    USE SIGNAL ;
    PORT
      LAYER M4 ;
        RECT  77.676 40.704 77.76 40.728 ;
    END
  END d[340]
  PIN d[341]
    DIRECTION INPUT ;
    USE SIGNAL ;
    PORT
      LAYER M4 ;
        RECT  77.676 40.8 77.76 40.824 ;
    END
  END d[341]
  PIN d[342]
    DIRECTION INPUT ;
    USE SIGNAL ;
    PORT
      LAYER M4 ;
        RECT  77.676 40.896 77.76 40.92 ;
    END
  END d[342]
  PIN d[343]
    DIRECTION INPUT ;
    USE SIGNAL ;
    PORT
      LAYER M4 ;
        RECT  77.676 40.992 77.76 41.016 ;
    END
  END d[343]
  PIN d[344]
    DIRECTION INPUT ;
    USE SIGNAL ;
    PORT
      LAYER M4 ;
        RECT  77.676 41.088 77.76 41.112 ;
    END
  END d[344]
  PIN d[345]
    DIRECTION INPUT ;
    USE SIGNAL ;
    PORT
      LAYER M4 ;
        RECT  77.676 41.184 77.76 41.208 ;
    END
  END d[345]
  PIN d[346]
    DIRECTION INPUT ;
    USE SIGNAL ;
    PORT
      LAYER M4 ;
        RECT  77.676 41.28 77.76 41.304 ;
    END
  END d[346]
  PIN d[347]
    DIRECTION INPUT ;
    USE SIGNAL ;
    PORT
      LAYER M4 ;
        RECT  77.676 41.376 77.76 41.4 ;
    END
  END d[347]
  PIN d[348]
    DIRECTION INPUT ;
    USE SIGNAL ;
    PORT
      LAYER M4 ;
        RECT  77.676 41.472 77.76 41.496 ;
    END
  END d[348]
  PIN d[349]
    DIRECTION INPUT ;
    USE SIGNAL ;
    PORT
      LAYER M4 ;
        RECT  77.676 41.568 77.76 41.592 ;
    END
  END d[349]
  PIN d[34]
    DIRECTION INPUT ;
    USE SIGNAL ;
    PORT
      LAYER M4 ;
        RECT  77.676 11.424 77.76 11.448 ;
    END
  END d[34]
  PIN d[350]
    DIRECTION INPUT ;
    USE SIGNAL ;
    PORT
      LAYER M4 ;
        RECT  77.676 41.664 77.76 41.688 ;
    END
  END d[350]
  PIN d[351]
    DIRECTION INPUT ;
    USE SIGNAL ;
    PORT
      LAYER M4 ;
        RECT  77.676 41.856 77.76 41.88 ;
    END
  END d[351]
  PIN d[352]
    DIRECTION INPUT ;
    USE SIGNAL ;
    PORT
      LAYER M4 ;
        RECT  77.676 41.76 77.76 41.784 ;
    END
  END d[352]
  PIN d[353]
    DIRECTION INPUT ;
    USE SIGNAL ;
    PORT
      LAYER M4 ;
        RECT  77.676 41.952 77.76 41.976 ;
    END
  END d[353]
  PIN d[354]
    DIRECTION INPUT ;
    USE SIGNAL ;
    PORT
      LAYER M4 ;
        RECT  77.676 42.144 77.76 42.168 ;
    END
  END d[354]
  PIN d[355]
    DIRECTION INPUT ;
    USE SIGNAL ;
    PORT
      LAYER M4 ;
        RECT  77.676 42.048 77.76 42.072 ;
    END
  END d[355]
  PIN d[356]
    DIRECTION INPUT ;
    USE SIGNAL ;
    PORT
      LAYER M4 ;
        RECT  77.676 42.24 77.76 42.264 ;
    END
  END d[356]
  PIN d[357]
    DIRECTION INPUT ;
    USE SIGNAL ;
    PORT
      LAYER M4 ;
        RECT  77.676 42.336 77.76 42.36 ;
    END
  END d[357]
  PIN d[358]
    DIRECTION INPUT ;
    USE SIGNAL ;
    PORT
      LAYER M4 ;
        RECT  77.676 42.432 77.76 42.456 ;
    END
  END d[358]
  PIN d[359]
    DIRECTION INPUT ;
    USE SIGNAL ;
    PORT
      LAYER M4 ;
        RECT  77.676 42.528 77.76 42.552 ;
    END
  END d[359]
  PIN d[35]
    DIRECTION INPUT ;
    USE SIGNAL ;
    PORT
      LAYER M4 ;
        RECT  77.676 11.328 77.76 11.352 ;
    END
  END d[35]
  PIN d[360]
    DIRECTION INPUT ;
    USE SIGNAL ;
    PORT
      LAYER M4 ;
        RECT  77.676 42.624 77.76 42.648 ;
    END
  END d[360]
  PIN d[361]
    DIRECTION INPUT ;
    USE SIGNAL ;
    PORT
      LAYER M4 ;
        RECT  77.676 42.72 77.76 42.744 ;
    END
  END d[361]
  PIN d[362]
    DIRECTION INPUT ;
    USE SIGNAL ;
    PORT
      LAYER M4 ;
        RECT  77.676 42.816 77.76 42.84 ;
    END
  END d[362]
  PIN d[363]
    DIRECTION INPUT ;
    USE SIGNAL ;
    PORT
      LAYER M4 ;
        RECT  77.676 42.912 77.76 42.936 ;
    END
  END d[363]
  PIN d[364]
    DIRECTION INPUT ;
    USE SIGNAL ;
    PORT
      LAYER M4 ;
        RECT  77.676 43.008 77.76 43.032 ;
    END
  END d[364]
  PIN d[365]
    DIRECTION INPUT ;
    USE SIGNAL ;
    PORT
      LAYER M4 ;
        RECT  77.676 43.104 77.76 43.128 ;
    END
  END d[365]
  PIN d[366]
    DIRECTION INPUT ;
    USE SIGNAL ;
    PORT
      LAYER M4 ;
        RECT  77.676 43.2 77.76 43.224 ;
    END
  END d[366]
  PIN d[367]
    DIRECTION INPUT ;
    USE SIGNAL ;
    PORT
      LAYER M4 ;
        RECT  77.676 43.296 77.76 43.32 ;
    END
  END d[367]
  PIN d[368]
    DIRECTION INPUT ;
    USE SIGNAL ;
    PORT
      LAYER M4 ;
        RECT  77.676 43.392 77.76 43.416 ;
    END
  END d[368]
  PIN d[369]
    DIRECTION INPUT ;
    USE SIGNAL ;
    PORT
      LAYER M4 ;
        RECT  77.676 43.488 77.76 43.512 ;
    END
  END d[369]
  PIN d[36]
    DIRECTION INPUT ;
    USE SIGNAL ;
    PORT
      LAYER M4 ;
        RECT  77.676 11.52 77.76 11.544 ;
    END
  END d[36]
  PIN d[370]
    DIRECTION INPUT ;
    USE SIGNAL ;
    PORT
      LAYER M4 ;
        RECT  77.676 43.584 77.76 43.608 ;
    END
  END d[370]
  PIN d[371]
    DIRECTION INPUT ;
    USE SIGNAL ;
    PORT
      LAYER M4 ;
        RECT  77.676 43.776 77.76 43.8 ;
    END
  END d[371]
  PIN d[372]
    DIRECTION INPUT ;
    USE SIGNAL ;
    PORT
      LAYER M4 ;
        RECT  77.676 43.68 77.76 43.704 ;
    END
  END d[372]
  PIN d[373]
    DIRECTION INPUT ;
    USE SIGNAL ;
    PORT
      LAYER M4 ;
        RECT  77.676 43.872 77.76 43.896 ;
    END
  END d[373]
  PIN d[374]
    DIRECTION INPUT ;
    USE SIGNAL ;
    PORT
      LAYER M4 ;
        RECT  77.676 44.064 77.76 44.088 ;
    END
  END d[374]
  PIN d[375]
    DIRECTION INPUT ;
    USE SIGNAL ;
    PORT
      LAYER M4 ;
        RECT  77.676 43.968 77.76 43.992 ;
    END
  END d[375]
  PIN d[376]
    DIRECTION INPUT ;
    USE SIGNAL ;
    PORT
      LAYER M4 ;
        RECT  77.676 44.16 77.76 44.184 ;
    END
  END d[376]
  PIN d[377]
    DIRECTION INPUT ;
    USE SIGNAL ;
    PORT
      LAYER M4 ;
        RECT  77.676 44.256 77.76 44.28 ;
    END
  END d[377]
  PIN d[378]
    DIRECTION INPUT ;
    USE SIGNAL ;
    PORT
      LAYER M4 ;
        RECT  77.676 44.352 77.76 44.376 ;
    END
  END d[378]
  PIN d[379]
    DIRECTION INPUT ;
    USE SIGNAL ;
    PORT
      LAYER M4 ;
        RECT  77.676 44.448 77.76 44.472 ;
    END
  END d[379]
  PIN d[37]
    DIRECTION INPUT ;
    USE SIGNAL ;
    PORT
      LAYER M4 ;
        RECT  77.676 11.616 77.76 11.64 ;
    END
  END d[37]
  PIN d[380]
    DIRECTION INPUT ;
    USE SIGNAL ;
    PORT
      LAYER M4 ;
        RECT  77.676 44.544 77.76 44.568 ;
    END
  END d[380]
  PIN d[381]
    DIRECTION INPUT ;
    USE SIGNAL ;
    PORT
      LAYER M4 ;
        RECT  77.676 44.64 77.76 44.664 ;
    END
  END d[381]
  PIN d[382]
    DIRECTION INPUT ;
    USE SIGNAL ;
    PORT
      LAYER M4 ;
        RECT  77.676 44.736 77.76 44.76 ;
    END
  END d[382]
  PIN d[383]
    DIRECTION INPUT ;
    USE SIGNAL ;
    PORT
      LAYER M4 ;
        RECT  77.676 45.024 77.76 45.048 ;
    END
  END d[383]
  PIN d[384]
    DIRECTION INPUT ;
    USE SIGNAL ;
    PORT
      LAYER M4 ;
        RECT  77.676 45.12 77.76 45.144 ;
    END
  END d[384]
  PIN d[385]
    DIRECTION INPUT ;
    USE SIGNAL ;
    PORT
      LAYER M4 ;
        RECT  77.676 45.216 77.76 45.24 ;
    END
  END d[385]
  PIN d[386]
    DIRECTION INPUT ;
    USE SIGNAL ;
    PORT
      LAYER M4 ;
        RECT  77.676 45.312 77.76 45.336 ;
    END
  END d[386]
  PIN d[387]
    DIRECTION INPUT ;
    USE SIGNAL ;
    PORT
      LAYER M4 ;
        RECT  77.676 45.408 77.76 45.432 ;
    END
  END d[387]
  PIN d[388]
    DIRECTION INPUT ;
    USE SIGNAL ;
    PORT
      LAYER M4 ;
        RECT  77.676 45.504 77.76 45.528 ;
    END
  END d[388]
  PIN d[389]
    DIRECTION INPUT ;
    USE SIGNAL ;
    PORT
      LAYER M4 ;
        RECT  77.676 45.6 77.76 45.624 ;
    END
  END d[389]
  PIN d[38]
    DIRECTION INPUT ;
    USE SIGNAL ;
    PORT
      LAYER M4 ;
        RECT  77.676 11.712 77.76 11.736 ;
    END
  END d[38]
  PIN d[390]
    DIRECTION INPUT ;
    USE SIGNAL ;
    PORT
      LAYER M4 ;
        RECT  77.676 45.696 77.76 45.72 ;
    END
  END d[390]
  PIN d[391]
    DIRECTION INPUT ;
    USE SIGNAL ;
    PORT
      LAYER M4 ;
        RECT  77.676 45.792 77.76 45.816 ;
    END
  END d[391]
  PIN d[392]
    DIRECTION INPUT ;
    USE SIGNAL ;
    PORT
      LAYER M4 ;
        RECT  77.676 45.888 77.76 45.912 ;
    END
  END d[392]
  PIN d[393]
    DIRECTION INPUT ;
    USE SIGNAL ;
    PORT
      LAYER M4 ;
        RECT  77.676 46.08 77.76 46.104 ;
    END
  END d[393]
  PIN d[394]
    DIRECTION INPUT ;
    USE SIGNAL ;
    PORT
      LAYER M4 ;
        RECT  77.676 45.984 77.76 46.008 ;
    END
  END d[394]
  PIN d[395]
    DIRECTION INPUT ;
    USE SIGNAL ;
    PORT
      LAYER M4 ;
        RECT  77.676 46.176 77.76 46.2 ;
    END
  END d[395]
  PIN d[396]
    DIRECTION INPUT ;
    USE SIGNAL ;
    PORT
      LAYER M4 ;
        RECT  77.676 46.272 77.76 46.296 ;
    END
  END d[396]
  PIN d[397]
    DIRECTION INPUT ;
    USE SIGNAL ;
    PORT
      LAYER M4 ;
        RECT  77.676 46.368 77.76 46.392 ;
    END
  END d[397]
  PIN d[398]
    DIRECTION INPUT ;
    USE SIGNAL ;
    PORT
      LAYER M4 ;
        RECT  77.676 46.464 77.76 46.488 ;
    END
  END d[398]
  PIN d[399]
    DIRECTION INPUT ;
    USE SIGNAL ;
    PORT
      LAYER M4 ;
        RECT  77.676 46.56 77.76 46.584 ;
    END
  END d[399]
  PIN d[39]
    DIRECTION INPUT ;
    USE SIGNAL ;
    PORT
      LAYER M4 ;
        RECT  77.676 11.808 77.76 11.832 ;
    END
  END d[39]
  PIN d[3]
    DIRECTION INPUT ;
    USE SIGNAL ;
    PORT
      LAYER M4 ;
        RECT  77.676 8.16 77.76 8.184 ;
    END
  END d[3]
  PIN d[400]
    DIRECTION INPUT ;
    USE SIGNAL ;
    PORT
      LAYER M4 ;
        RECT  77.676 46.656 77.76 46.68 ;
    END
  END d[400]
  PIN d[401]
    DIRECTION INPUT ;
    USE SIGNAL ;
    PORT
      LAYER M4 ;
        RECT  77.676 46.752 77.76 46.776 ;
    END
  END d[401]
  PIN d[402]
    DIRECTION INPUT ;
    USE SIGNAL ;
    PORT
      LAYER M4 ;
        RECT  77.676 46.848 77.76 46.872 ;
    END
  END d[402]
  PIN d[403]
    DIRECTION INPUT ;
    USE SIGNAL ;
    PORT
      LAYER M4 ;
        RECT  77.676 46.944 77.76 46.968 ;
    END
  END d[403]
  PIN d[404]
    DIRECTION INPUT ;
    USE SIGNAL ;
    PORT
      LAYER M4 ;
        RECT  77.676 47.04 77.76 47.064 ;
    END
  END d[404]
  PIN d[405]
    DIRECTION INPUT ;
    USE SIGNAL ;
    PORT
      LAYER M4 ;
        RECT  77.676 47.136 77.76 47.16 ;
    END
  END d[405]
  PIN d[406]
    DIRECTION INPUT ;
    USE SIGNAL ;
    PORT
      LAYER M4 ;
        RECT  77.676 47.232 77.76 47.256 ;
    END
  END d[406]
  PIN d[407]
    DIRECTION INPUT ;
    USE SIGNAL ;
    PORT
      LAYER M4 ;
        RECT  77.676 47.328 77.76 47.352 ;
    END
  END d[407]
  PIN d[408]
    DIRECTION INPUT ;
    USE SIGNAL ;
    PORT
      LAYER M4 ;
        RECT  77.676 47.424 77.76 47.448 ;
    END
  END d[408]
  PIN d[409]
    DIRECTION INPUT ;
    USE SIGNAL ;
    PORT
      LAYER M4 ;
        RECT  77.676 47.52 77.76 47.544 ;
    END
  END d[409]
  PIN d[40]
    DIRECTION INPUT ;
    USE SIGNAL ;
    PORT
      LAYER M4 ;
        RECT  77.676 11.904 77.76 11.928 ;
    END
  END d[40]
  PIN d[410]
    DIRECTION INPUT ;
    USE SIGNAL ;
    PORT
      LAYER M4 ;
        RECT  77.676 47.616 77.76 47.64 ;
    END
  END d[410]
  PIN d[411]
    DIRECTION INPUT ;
    USE SIGNAL ;
    PORT
      LAYER M4 ;
        RECT  77.676 47.712 77.76 47.736 ;
    END
  END d[411]
  PIN d[412]
    DIRECTION INPUT ;
    USE SIGNAL ;
    PORT
      LAYER M4 ;
        RECT  77.676 47.808 77.76 47.832 ;
    END
  END d[412]
  PIN d[413]
    DIRECTION INPUT ;
    USE SIGNAL ;
    PORT
      LAYER M4 ;
        RECT  77.676 48 77.76 48.024 ;
    END
  END d[413]
  PIN d[414]
    DIRECTION INPUT ;
    USE SIGNAL ;
    PORT
      LAYER M4 ;
        RECT  77.676 47.904 77.76 47.928 ;
    END
  END d[414]
  PIN d[415]
    DIRECTION INPUT ;
    USE SIGNAL ;
    PORT
      LAYER M4 ;
        RECT  77.676 48.096 77.76 48.12 ;
    END
  END d[415]
  PIN d[416]
    DIRECTION INPUT ;
    USE SIGNAL ;
    PORT
      LAYER M4 ;
        RECT  77.676 48.288 77.76 48.312 ;
    END
  END d[416]
  PIN d[417]
    DIRECTION INPUT ;
    USE SIGNAL ;
    PORT
      LAYER M4 ;
        RECT  77.676 48.192 77.76 48.216 ;
    END
  END d[417]
  PIN d[418]
    DIRECTION INPUT ;
    USE SIGNAL ;
    PORT
      LAYER M4 ;
        RECT  77.676 48.384 77.76 48.408 ;
    END
  END d[418]
  PIN d[419]
    DIRECTION INPUT ;
    USE SIGNAL ;
    PORT
      LAYER M4 ;
        RECT  77.676 48.48 77.76 48.504 ;
    END
  END d[419]
  PIN d[41]
    DIRECTION INPUT ;
    USE SIGNAL ;
    PORT
      LAYER M4 ;
        RECT  77.676 12 77.76 12.024 ;
    END
  END d[41]
  PIN d[420]
    DIRECTION INPUT ;
    USE SIGNAL ;
    PORT
      LAYER M4 ;
        RECT  77.676 48.576 77.76 48.6 ;
    END
  END d[420]
  PIN d[421]
    DIRECTION INPUT ;
    USE SIGNAL ;
    PORT
      LAYER M4 ;
        RECT  77.676 48.672 77.76 48.696 ;
    END
  END d[421]
  PIN d[422]
    DIRECTION INPUT ;
    USE SIGNAL ;
    PORT
      LAYER M4 ;
        RECT  77.676 48.768 77.76 48.792 ;
    END
  END d[422]
  PIN d[423]
    DIRECTION INPUT ;
    USE SIGNAL ;
    PORT
      LAYER M4 ;
        RECT  77.676 48.864 77.76 48.888 ;
    END
  END d[423]
  PIN d[424]
    DIRECTION INPUT ;
    USE SIGNAL ;
    PORT
      LAYER M4 ;
        RECT  77.676 48.96 77.76 48.984 ;
    END
  END d[424]
  PIN d[425]
    DIRECTION INPUT ;
    USE SIGNAL ;
    PORT
      LAYER M4 ;
        RECT  77.676 49.056 77.76 49.08 ;
    END
  END d[425]
  PIN d[426]
    DIRECTION INPUT ;
    USE SIGNAL ;
    PORT
      LAYER M4 ;
        RECT  77.676 49.152 77.76 49.176 ;
    END
  END d[426]
  PIN d[427]
    DIRECTION INPUT ;
    USE SIGNAL ;
    PORT
      LAYER M4 ;
        RECT  77.676 49.248 77.76 49.272 ;
    END
  END d[427]
  PIN d[428]
    DIRECTION INPUT ;
    USE SIGNAL ;
    PORT
      LAYER M4 ;
        RECT  77.676 49.344 77.76 49.368 ;
    END
  END d[428]
  PIN d[429]
    DIRECTION INPUT ;
    USE SIGNAL ;
    PORT
      LAYER M4 ;
        RECT  77.676 49.44 77.76 49.464 ;
    END
  END d[429]
  PIN d[42]
    DIRECTION INPUT ;
    USE SIGNAL ;
    PORT
      LAYER M4 ;
        RECT  77.676 12.192 77.76 12.216 ;
    END
  END d[42]
  PIN d[430]
    DIRECTION INPUT ;
    USE SIGNAL ;
    PORT
      LAYER M4 ;
        RECT  77.676 49.536 77.76 49.56 ;
    END
  END d[430]
  PIN d[431]
    DIRECTION INPUT ;
    USE SIGNAL ;
    PORT
      LAYER M4 ;
        RECT  77.676 49.632 77.76 49.656 ;
    END
  END d[431]
  PIN d[432]
    DIRECTION INPUT ;
    USE SIGNAL ;
    PORT
      LAYER M4 ;
        RECT  77.676 49.728 77.76 49.752 ;
    END
  END d[432]
  PIN d[433]
    DIRECTION INPUT ;
    USE SIGNAL ;
    PORT
      LAYER M4 ;
        RECT  77.676 49.92 77.76 49.944 ;
    END
  END d[433]
  PIN d[434]
    DIRECTION INPUT ;
    USE SIGNAL ;
    PORT
      LAYER M4 ;
        RECT  77.676 49.824 77.76 49.848 ;
    END
  END d[434]
  PIN d[435]
    DIRECTION INPUT ;
    USE SIGNAL ;
    PORT
      LAYER M4 ;
        RECT  77.676 50.112 77.76 50.136 ;
    END
  END d[435]
  PIN d[436]
    DIRECTION INPUT ;
    USE SIGNAL ;
    PORT
      LAYER M4 ;
        RECT  77.676 50.016 77.76 50.04 ;
    END
  END d[436]
  PIN d[437]
    DIRECTION INPUT ;
    USE SIGNAL ;
    PORT
      LAYER M4 ;
        RECT  77.676 50.208 77.76 50.232 ;
    END
  END d[437]
  PIN d[438]
    DIRECTION INPUT ;
    USE SIGNAL ;
    PORT
      LAYER M4 ;
        RECT  77.676 50.304 77.76 50.328 ;
    END
  END d[438]
  PIN d[439]
    DIRECTION INPUT ;
    USE SIGNAL ;
    PORT
      LAYER M4 ;
        RECT  77.676 50.4 77.76 50.424 ;
    END
  END d[439]
  PIN d[43]
    DIRECTION INPUT ;
    USE SIGNAL ;
    PORT
      LAYER M4 ;
        RECT  77.676 12.096 77.76 12.12 ;
    END
  END d[43]
  PIN d[440]
    DIRECTION INPUT ;
    USE SIGNAL ;
    PORT
      LAYER M4 ;
        RECT  77.676 50.496 77.76 50.52 ;
    END
  END d[440]
  PIN d[441]
    DIRECTION INPUT ;
    USE SIGNAL ;
    PORT
      LAYER M4 ;
        RECT  77.676 50.592 77.76 50.616 ;
    END
  END d[441]
  PIN d[442]
    DIRECTION INPUT ;
    USE SIGNAL ;
    PORT
      LAYER M4 ;
        RECT  77.676 50.688 77.76 50.712 ;
    END
  END d[442]
  PIN d[443]
    DIRECTION INPUT ;
    USE SIGNAL ;
    PORT
      LAYER M4 ;
        RECT  77.676 50.784 77.76 50.808 ;
    END
  END d[443]
  PIN d[444]
    DIRECTION INPUT ;
    USE SIGNAL ;
    PORT
      LAYER M4 ;
        RECT  77.676 50.88 77.76 50.904 ;
    END
  END d[444]
  PIN d[445]
    DIRECTION INPUT ;
    USE SIGNAL ;
    PORT
      LAYER M4 ;
        RECT  77.676 50.976 77.76 51 ;
    END
  END d[445]
  PIN d[446]
    DIRECTION INPUT ;
    USE SIGNAL ;
    PORT
      LAYER M4 ;
        RECT  77.676 51.072 77.76 51.096 ;
    END
  END d[446]
  PIN d[447]
    DIRECTION INPUT ;
    USE SIGNAL ;
    PORT
      LAYER M4 ;
        RECT  77.676 51.168 77.76 51.192 ;
    END
  END d[447]
  PIN d[448]
    DIRECTION INPUT ;
    USE SIGNAL ;
    PORT
      LAYER M4 ;
        RECT  77.676 51.264 77.76 51.288 ;
    END
  END d[448]
  PIN d[449]
    DIRECTION INPUT ;
    USE SIGNAL ;
    PORT
      LAYER M4 ;
        RECT  77.676 51.36 77.76 51.384 ;
    END
  END d[449]
  PIN d[44]
    DIRECTION INPUT ;
    USE SIGNAL ;
    PORT
      LAYER M4 ;
        RECT  77.676 12.384 77.76 12.408 ;
    END
  END d[44]
  PIN d[450]
    DIRECTION INPUT ;
    USE SIGNAL ;
    PORT
      LAYER M4 ;
        RECT  77.676 51.456 77.76 51.48 ;
    END
  END d[450]
  PIN d[451]
    DIRECTION INPUT ;
    USE SIGNAL ;
    PORT
      LAYER M4 ;
        RECT  77.676 51.552 77.76 51.576 ;
    END
  END d[451]
  PIN d[452]
    DIRECTION INPUT ;
    USE SIGNAL ;
    PORT
      LAYER M4 ;
        RECT  77.676 51.648 77.76 51.672 ;
    END
  END d[452]
  PIN d[453]
    DIRECTION INPUT ;
    USE SIGNAL ;
    PORT
      LAYER M4 ;
        RECT  77.676 51.744 77.76 51.768 ;
    END
  END d[453]
  PIN d[454]
    DIRECTION INPUT ;
    USE SIGNAL ;
    PORT
      LAYER M4 ;
        RECT  77.676 51.84 77.76 51.864 ;
    END
  END d[454]
  PIN d[455]
    DIRECTION INPUT ;
    USE SIGNAL ;
    PORT
      LAYER M4 ;
        RECT  77.676 52.032 77.76 52.056 ;
    END
  END d[455]
  PIN d[456]
    DIRECTION INPUT ;
    USE SIGNAL ;
    PORT
      LAYER M4 ;
        RECT  77.676 51.936 77.76 51.96 ;
    END
  END d[456]
  PIN d[457]
    DIRECTION INPUT ;
    USE SIGNAL ;
    PORT
      LAYER M4 ;
        RECT  77.676 52.128 77.76 52.152 ;
    END
  END d[457]
  PIN d[458]
    DIRECTION INPUT ;
    USE SIGNAL ;
    PORT
      LAYER M4 ;
        RECT  77.676 52.224 77.76 52.248 ;
    END
  END d[458]
  PIN d[459]
    DIRECTION INPUT ;
    USE SIGNAL ;
    PORT
      LAYER M4 ;
        RECT  77.676 52.32 77.76 52.344 ;
    END
  END d[459]
  PIN d[45]
    DIRECTION INPUT ;
    USE SIGNAL ;
    PORT
      LAYER M4 ;
        RECT  77.676 12.288 77.76 12.312 ;
    END
  END d[45]
  PIN d[460]
    DIRECTION INPUT ;
    USE SIGNAL ;
    PORT
      LAYER M4 ;
        RECT  77.676 52.416 77.76 52.44 ;
    END
  END d[460]
  PIN d[461]
    DIRECTION INPUT ;
    USE SIGNAL ;
    PORT
      LAYER M4 ;
        RECT  77.676 52.512 77.76 52.536 ;
    END
  END d[461]
  PIN d[462]
    DIRECTION INPUT ;
    USE SIGNAL ;
    PORT
      LAYER M4 ;
        RECT  77.676 52.608 77.76 52.632 ;
    END
  END d[462]
  PIN d[463]
    DIRECTION INPUT ;
    USE SIGNAL ;
    PORT
      LAYER M4 ;
        RECT  77.676 52.704 77.76 52.728 ;
    END
  END d[463]
  PIN d[464]
    DIRECTION INPUT ;
    USE SIGNAL ;
    PORT
      LAYER M4 ;
        RECT  77.676 52.8 77.76 52.824 ;
    END
  END d[464]
  PIN d[465]
    DIRECTION INPUT ;
    USE SIGNAL ;
    PORT
      LAYER M4 ;
        RECT  77.676 52.896 77.76 52.92 ;
    END
  END d[465]
  PIN d[466]
    DIRECTION INPUT ;
    USE SIGNAL ;
    PORT
      LAYER M4 ;
        RECT  77.676 52.992 77.76 53.016 ;
    END
  END d[466]
  PIN d[467]
    DIRECTION INPUT ;
    USE SIGNAL ;
    PORT
      LAYER M4 ;
        RECT  77.676 53.088 77.76 53.112 ;
    END
  END d[467]
  PIN d[468]
    DIRECTION INPUT ;
    USE SIGNAL ;
    PORT
      LAYER M4 ;
        RECT  77.676 53.184 77.76 53.208 ;
    END
  END d[468]
  PIN d[469]
    DIRECTION INPUT ;
    USE SIGNAL ;
    PORT
      LAYER M4 ;
        RECT  77.676 53.28 77.76 53.304 ;
    END
  END d[469]
  PIN d[46]
    DIRECTION INPUT ;
    USE SIGNAL ;
    PORT
      LAYER M4 ;
        RECT  77.676 12.48 77.76 12.504 ;
    END
  END d[46]
  PIN d[470]
    DIRECTION INPUT ;
    USE SIGNAL ;
    PORT
      LAYER M4 ;
        RECT  77.676 53.376 77.76 53.4 ;
    END
  END d[470]
  PIN d[471]
    DIRECTION INPUT ;
    USE SIGNAL ;
    PORT
      LAYER M4 ;
        RECT  77.676 53.472 77.76 53.496 ;
    END
  END d[471]
  PIN d[472]
    DIRECTION INPUT ;
    USE SIGNAL ;
    PORT
      LAYER M4 ;
        RECT  77.676 53.568 77.76 53.592 ;
    END
  END d[472]
  PIN d[473]
    DIRECTION INPUT ;
    USE SIGNAL ;
    PORT
      LAYER M4 ;
        RECT  77.676 53.664 77.76 53.688 ;
    END
  END d[473]
  PIN d[474]
    DIRECTION INPUT ;
    USE SIGNAL ;
    PORT
      LAYER M4 ;
        RECT  77.676 53.76 77.76 53.784 ;
    END
  END d[474]
  PIN d[475]
    DIRECTION INPUT ;
    USE SIGNAL ;
    PORT
      LAYER M4 ;
        RECT  77.676 53.952 77.76 53.976 ;
    END
  END d[475]
  PIN d[476]
    DIRECTION INPUT ;
    USE SIGNAL ;
    PORT
      LAYER M4 ;
        RECT  77.676 53.856 77.76 53.88 ;
    END
  END d[476]
  PIN d[477]
    DIRECTION INPUT ;
    USE SIGNAL ;
    PORT
      LAYER M4 ;
        RECT  77.676 54.048 77.76 54.072 ;
    END
  END d[477]
  PIN d[478]
    DIRECTION INPUT ;
    USE SIGNAL ;
    PORT
      LAYER M4 ;
        RECT  77.676 54.24 77.76 54.264 ;
    END
  END d[478]
  PIN d[479]
    DIRECTION INPUT ;
    USE SIGNAL ;
    PORT
      LAYER M4 ;
        RECT  77.676 54.144 77.76 54.168 ;
    END
  END d[479]
  PIN d[47]
    DIRECTION INPUT ;
    USE SIGNAL ;
    PORT
      LAYER M4 ;
        RECT  77.676 12.576 77.76 12.6 ;
    END
  END d[47]
  PIN d[480]
    DIRECTION INPUT ;
    USE SIGNAL ;
    PORT
      LAYER M4 ;
        RECT  77.676 54.336 77.76 54.36 ;
    END
  END d[480]
  PIN d[481]
    DIRECTION INPUT ;
    USE SIGNAL ;
    PORT
      LAYER M4 ;
        RECT  77.676 54.432 77.76 54.456 ;
    END
  END d[481]
  PIN d[482]
    DIRECTION INPUT ;
    USE SIGNAL ;
    PORT
      LAYER M4 ;
        RECT  77.676 54.528 77.76 54.552 ;
    END
  END d[482]
  PIN d[483]
    DIRECTION INPUT ;
    USE SIGNAL ;
    PORT
      LAYER M4 ;
        RECT  77.676 54.624 77.76 54.648 ;
    END
  END d[483]
  PIN d[484]
    DIRECTION INPUT ;
    USE SIGNAL ;
    PORT
      LAYER M4 ;
        RECT  77.676 54.72 77.76 54.744 ;
    END
  END d[484]
  PIN d[485]
    DIRECTION INPUT ;
    USE SIGNAL ;
    PORT
      LAYER M4 ;
        RECT  77.676 54.816 77.76 54.84 ;
    END
  END d[485]
  PIN d[486]
    DIRECTION INPUT ;
    USE SIGNAL ;
    PORT
      LAYER M4 ;
        RECT  77.676 54.912 77.76 54.936 ;
    END
  END d[486]
  PIN d[487]
    DIRECTION INPUT ;
    USE SIGNAL ;
    PORT
      LAYER M4 ;
        RECT  77.676 55.008 77.76 55.032 ;
    END
  END d[487]
  PIN d[488]
    DIRECTION INPUT ;
    USE SIGNAL ;
    PORT
      LAYER M4 ;
        RECT  77.676 55.104 77.76 55.128 ;
    END
  END d[488]
  PIN d[489]
    DIRECTION INPUT ;
    USE SIGNAL ;
    PORT
      LAYER M4 ;
        RECT  77.676 55.2 77.76 55.224 ;
    END
  END d[489]
  PIN d[48]
    DIRECTION INPUT ;
    USE SIGNAL ;
    PORT
      LAYER M4 ;
        RECT  77.676 12.672 77.76 12.696 ;
    END
  END d[48]
  PIN d[490]
    DIRECTION INPUT ;
    USE SIGNAL ;
    PORT
      LAYER M4 ;
        RECT  77.676 55.296 77.76 55.32 ;
    END
  END d[490]
  PIN d[491]
    DIRECTION INPUT ;
    USE SIGNAL ;
    PORT
      LAYER M4 ;
        RECT  77.676 55.392 77.76 55.416 ;
    END
  END d[491]
  PIN d[492]
    DIRECTION INPUT ;
    USE SIGNAL ;
    PORT
      LAYER M4 ;
        RECT  77.676 55.488 77.76 55.512 ;
    END
  END d[492]
  PIN d[493]
    DIRECTION INPUT ;
    USE SIGNAL ;
    PORT
      LAYER M4 ;
        RECT  77.676 55.584 77.76 55.608 ;
    END
  END d[493]
  PIN d[494]
    DIRECTION INPUT ;
    USE SIGNAL ;
    PORT
      LAYER M4 ;
        RECT  77.676 55.68 77.76 55.704 ;
    END
  END d[494]
  PIN d[495]
    DIRECTION INPUT ;
    USE SIGNAL ;
    PORT
      LAYER M4 ;
        RECT  77.676 55.968 77.76 55.992 ;
    END
  END d[495]
  PIN d[496]
    DIRECTION INPUT ;
    USE SIGNAL ;
    PORT
      LAYER M4 ;
        RECT  77.676 55.776 77.76 55.8 ;
    END
  END d[496]
  PIN d[497]
    DIRECTION INPUT ;
    USE SIGNAL ;
    PORT
      LAYER M4 ;
        RECT  77.676 56.064 77.76 56.088 ;
    END
  END d[497]
  PIN d[498]
    DIRECTION INPUT ;
    USE SIGNAL ;
    PORT
      LAYER M4 ;
        RECT  77.676 55.872 77.76 55.896 ;
    END
  END d[498]
  PIN d[499]
    DIRECTION INPUT ;
    USE SIGNAL ;
    PORT
      LAYER M4 ;
        RECT  77.676 56.16 77.76 56.184 ;
    END
  END d[499]
  PIN d[49]
    DIRECTION INPUT ;
    USE SIGNAL ;
    PORT
      LAYER M4 ;
        RECT  77.676 12.768 77.76 12.792 ;
    END
  END d[49]
  PIN d[4]
    DIRECTION INPUT ;
    USE SIGNAL ;
    PORT
      LAYER M4 ;
        RECT  77.676 8.448 77.76 8.472 ;
    END
  END d[4]
  PIN d[500]
    DIRECTION INPUT ;
    USE SIGNAL ;
    PORT
      LAYER M4 ;
        RECT  77.676 56.256 77.76 56.28 ;
    END
  END d[500]
  PIN d[501]
    DIRECTION INPUT ;
    USE SIGNAL ;
    PORT
      LAYER M4 ;
        RECT  77.676 56.352 77.76 56.376 ;
    END
  END d[501]
  PIN d[502]
    DIRECTION INPUT ;
    USE SIGNAL ;
    PORT
      LAYER M4 ;
        RECT  77.676 56.448 77.76 56.472 ;
    END
  END d[502]
  PIN d[503]
    DIRECTION INPUT ;
    USE SIGNAL ;
    PORT
      LAYER M4 ;
        RECT  77.676 56.544 77.76 56.568 ;
    END
  END d[503]
  PIN d[504]
    DIRECTION INPUT ;
    USE SIGNAL ;
    PORT
      LAYER M4 ;
        RECT  77.676 56.64 77.76 56.664 ;
    END
  END d[504]
  PIN d[505]
    DIRECTION INPUT ;
    USE SIGNAL ;
    PORT
      LAYER M4 ;
        RECT  77.676 56.736 77.76 56.76 ;
    END
  END d[505]
  PIN d[506]
    DIRECTION INPUT ;
    USE SIGNAL ;
    PORT
      LAYER M4 ;
        RECT  77.676 56.832 77.76 56.856 ;
    END
  END d[506]
  PIN d[507]
    DIRECTION INPUT ;
    USE SIGNAL ;
    PORT
      LAYER M4 ;
        RECT  77.676 56.928 77.76 56.952 ;
    END
  END d[507]
  PIN d[508]
    DIRECTION INPUT ;
    USE SIGNAL ;
    PORT
      LAYER M4 ;
        RECT  77.676 57.024 77.76 57.048 ;
    END
  END d[508]
  PIN d[509]
    DIRECTION INPUT ;
    USE SIGNAL ;
    PORT
      LAYER M4 ;
        RECT  77.676 57.12 77.76 57.144 ;
    END
  END d[509]
  PIN d[50]
    DIRECTION INPUT ;
    USE SIGNAL ;
    PORT
      LAYER M4 ;
        RECT  77.676 12.864 77.76 12.888 ;
    END
  END d[50]
  PIN d[510]
    DIRECTION INPUT ;
    USE SIGNAL ;
    PORT
      LAYER M4 ;
        RECT  77.676 57.216 77.76 57.24 ;
    END
  END d[510]
  PIN d[511]
    DIRECTION INPUT ;
    USE SIGNAL ;
    PORT
      LAYER M4 ;
        RECT  77.676 57.312 77.76 57.336 ;
    END
  END d[511]
  PIN d[512]
    DIRECTION INPUT ;
    USE SIGNAL ;
    PORT
      LAYER M4 ;
        RECT  77.676 57.408 77.76 57.432 ;
    END
  END d[512]
  PIN d[513]
    DIRECTION INPUT ;
    USE SIGNAL ;
    PORT
      LAYER M4 ;
        RECT  77.676 57.504 77.76 57.528 ;
    END
  END d[513]
  PIN d[514]
    DIRECTION INPUT ;
    USE SIGNAL ;
    PORT
      LAYER M4 ;
        RECT  77.676 57.6 77.76 57.624 ;
    END
  END d[514]
  PIN d[515]
    DIRECTION INPUT ;
    USE SIGNAL ;
    PORT
      LAYER M4 ;
        RECT  77.676 57.696 77.76 57.72 ;
    END
  END d[515]
  PIN d[516]
    DIRECTION INPUT ;
    USE SIGNAL ;
    PORT
      LAYER M4 ;
        RECT  77.676 57.792 77.76 57.816 ;
    END
  END d[516]
  PIN d[517]
    DIRECTION INPUT ;
    USE SIGNAL ;
    PORT
      LAYER M4 ;
        RECT  77.676 57.984 77.76 58.008 ;
    END
  END d[517]
  PIN d[518]
    DIRECTION INPUT ;
    USE SIGNAL ;
    PORT
      LAYER M4 ;
        RECT  77.676 57.888 77.76 57.912 ;
    END
  END d[518]
  PIN d[519]
    DIRECTION INPUT ;
    USE SIGNAL ;
    PORT
      LAYER M4 ;
        RECT  77.676 58.08 77.76 58.104 ;
    END
  END d[519]
  PIN d[51]
    DIRECTION INPUT ;
    USE SIGNAL ;
    PORT
      LAYER M4 ;
        RECT  77.676 12.96 77.76 12.984 ;
    END
  END d[51]
  PIN d[520]
    DIRECTION INPUT ;
    USE SIGNAL ;
    PORT
      LAYER M4 ;
        RECT  77.676 58.176 77.76 58.2 ;
    END
  END d[520]
  PIN d[521]
    DIRECTION INPUT ;
    USE SIGNAL ;
    PORT
      LAYER M4 ;
        RECT  77.676 58.272 77.76 58.296 ;
    END
  END d[521]
  PIN d[522]
    DIRECTION INPUT ;
    USE SIGNAL ;
    PORT
      LAYER M4 ;
        RECT  77.676 58.368 77.76 58.392 ;
    END
  END d[522]
  PIN d[523]
    DIRECTION INPUT ;
    USE SIGNAL ;
    PORT
      LAYER M4 ;
        RECT  77.676 58.464 77.76 58.488 ;
    END
  END d[523]
  PIN d[524]
    DIRECTION INPUT ;
    USE SIGNAL ;
    PORT
      LAYER M4 ;
        RECT  77.676 58.56 77.76 58.584 ;
    END
  END d[524]
  PIN d[525]
    DIRECTION INPUT ;
    USE SIGNAL ;
    PORT
      LAYER M4 ;
        RECT  77.676 58.656 77.76 58.68 ;
    END
  END d[525]
  PIN d[526]
    DIRECTION INPUT ;
    USE SIGNAL ;
    PORT
      LAYER M4 ;
        RECT  77.676 58.752 77.76 58.776 ;
    END
  END d[526]
  PIN d[527]
    DIRECTION INPUT ;
    USE SIGNAL ;
    PORT
      LAYER M4 ;
        RECT  77.676 58.848 77.76 58.872 ;
    END
  END d[527]
  PIN d[528]
    DIRECTION INPUT ;
    USE SIGNAL ;
    PORT
      LAYER M4 ;
        RECT  77.676 58.944 77.76 58.968 ;
    END
  END d[528]
  PIN d[529]
    DIRECTION INPUT ;
    USE SIGNAL ;
    PORT
      LAYER M4 ;
        RECT  77.676 59.04 77.76 59.064 ;
    END
  END d[529]
  PIN d[52]
    DIRECTION INPUT ;
    USE SIGNAL ;
    PORT
      LAYER M4 ;
        RECT  77.676 13.056 77.76 13.08 ;
    END
  END d[52]
  PIN d[530]
    DIRECTION INPUT ;
    USE SIGNAL ;
    PORT
      LAYER M4 ;
        RECT  77.676 59.136 77.76 59.16 ;
    END
  END d[530]
  PIN d[531]
    DIRECTION INPUT ;
    USE SIGNAL ;
    PORT
      LAYER M4 ;
        RECT  77.676 59.232 77.76 59.256 ;
    END
  END d[531]
  PIN d[532]
    DIRECTION INPUT ;
    USE SIGNAL ;
    PORT
      LAYER M4 ;
        RECT  77.676 59.328 77.76 59.352 ;
    END
  END d[532]
  PIN d[533]
    DIRECTION INPUT ;
    USE SIGNAL ;
    PORT
      LAYER M4 ;
        RECT  77.676 59.424 77.76 59.448 ;
    END
  END d[533]
  PIN d[534]
    DIRECTION INPUT ;
    USE SIGNAL ;
    PORT
      LAYER M4 ;
        RECT  77.676 59.52 77.76 59.544 ;
    END
  END d[534]
  PIN d[535]
    DIRECTION INPUT ;
    USE SIGNAL ;
    PORT
      LAYER M4 ;
        RECT  77.676 59.616 77.76 59.64 ;
    END
  END d[535]
  PIN d[536]
    DIRECTION INPUT ;
    USE SIGNAL ;
    PORT
      LAYER M4 ;
        RECT  77.676 59.712 77.76 59.736 ;
    END
  END d[536]
  PIN d[537]
    DIRECTION INPUT ;
    USE SIGNAL ;
    PORT
      LAYER M4 ;
        RECT  77.676 59.904 77.76 59.928 ;
    END
  END d[537]
  PIN d[538]
    DIRECTION INPUT ;
    USE SIGNAL ;
    PORT
      LAYER M4 ;
        RECT  77.676 59.808 77.76 59.832 ;
    END
  END d[538]
  PIN d[539]
    DIRECTION INPUT ;
    USE SIGNAL ;
    PORT
      LAYER M4 ;
        RECT  77.676 60 77.76 60.024 ;
    END
  END d[539]
  PIN d[53]
    DIRECTION INPUT ;
    USE SIGNAL ;
    PORT
      LAYER M4 ;
        RECT  77.676 13.152 77.76 13.176 ;
    END
  END d[53]
  PIN d[540]
    DIRECTION INPUT ;
    USE SIGNAL ;
    PORT
      LAYER M4 ;
        RECT  77.676 60.192 77.76 60.216 ;
    END
  END d[540]
  PIN d[541]
    DIRECTION INPUT ;
    USE SIGNAL ;
    PORT
      LAYER M4 ;
        RECT  77.676 60.096 77.76 60.12 ;
    END
  END d[541]
  PIN d[542]
    DIRECTION INPUT ;
    USE SIGNAL ;
    PORT
      LAYER M4 ;
        RECT  77.676 60.288 77.76 60.312 ;
    END
  END d[542]
  PIN d[543]
    DIRECTION INPUT ;
    USE SIGNAL ;
    PORT
      LAYER M4 ;
        RECT  77.676 60.384 77.76 60.408 ;
    END
  END d[543]
  PIN d[544]
    DIRECTION INPUT ;
    USE SIGNAL ;
    PORT
      LAYER M4 ;
        RECT  77.676 60.48 77.76 60.504 ;
    END
  END d[544]
  PIN d[545]
    DIRECTION INPUT ;
    USE SIGNAL ;
    PORT
      LAYER M4 ;
        RECT  77.676 60.576 77.76 60.6 ;
    END
  END d[545]
  PIN d[546]
    DIRECTION INPUT ;
    USE SIGNAL ;
    PORT
      LAYER M4 ;
        RECT  77.676 60.672 77.76 60.696 ;
    END
  END d[546]
  PIN d[547]
    DIRECTION INPUT ;
    USE SIGNAL ;
    PORT
      LAYER M4 ;
        RECT  77.676 60.768 77.76 60.792 ;
    END
  END d[547]
  PIN d[548]
    DIRECTION INPUT ;
    USE SIGNAL ;
    PORT
      LAYER M4 ;
        RECT  77.676 60.864 77.76 60.888 ;
    END
  END d[548]
  PIN d[549]
    DIRECTION INPUT ;
    USE SIGNAL ;
    PORT
      LAYER M4 ;
        RECT  77.676 60.96 77.76 60.984 ;
    END
  END d[549]
  PIN d[54]
    DIRECTION INPUT ;
    USE SIGNAL ;
    PORT
      LAYER M4 ;
        RECT  77.676 13.248 77.76 13.272 ;
    END
  END d[54]
  PIN d[550]
    DIRECTION INPUT ;
    USE SIGNAL ;
    PORT
      LAYER M4 ;
        RECT  77.676 61.056 77.76 61.08 ;
    END
  END d[550]
  PIN d[551]
    DIRECTION INPUT ;
    USE SIGNAL ;
    PORT
      LAYER M4 ;
        RECT  77.676 61.152 77.76 61.176 ;
    END
  END d[551]
  PIN d[552]
    DIRECTION INPUT ;
    USE SIGNAL ;
    PORT
      LAYER M4 ;
        RECT  77.676 61.248 77.76 61.272 ;
    END
  END d[552]
  PIN d[553]
    DIRECTION INPUT ;
    USE SIGNAL ;
    PORT
      LAYER M4 ;
        RECT  77.676 61.344 77.76 61.368 ;
    END
  END d[553]
  PIN d[554]
    DIRECTION INPUT ;
    USE SIGNAL ;
    PORT
      LAYER M4 ;
        RECT  77.676 61.44 77.76 61.464 ;
    END
  END d[554]
  PIN d[555]
    DIRECTION INPUT ;
    USE SIGNAL ;
    PORT
      LAYER M4 ;
        RECT  77.676 61.536 77.76 61.56 ;
    END
  END d[555]
  PIN d[556]
    DIRECTION INPUT ;
    USE SIGNAL ;
    PORT
      LAYER M4 ;
        RECT  77.676 61.632 77.76 61.656 ;
    END
  END d[556]
  PIN d[557]
    DIRECTION INPUT ;
    USE SIGNAL ;
    PORT
      LAYER M4 ;
        RECT  77.676 61.824 77.76 61.848 ;
    END
  END d[557]
  PIN d[558]
    DIRECTION INPUT ;
    USE SIGNAL ;
    PORT
      LAYER M4 ;
        RECT  77.676 61.728 77.76 61.752 ;
    END
  END d[558]
  PIN d[559]
    DIRECTION INPUT ;
    USE SIGNAL ;
    PORT
      LAYER M4 ;
        RECT  77.676 62.016 77.76 62.04 ;
    END
  END d[559]
  PIN d[55]
    DIRECTION INPUT ;
    USE SIGNAL ;
    PORT
      LAYER M4 ;
        RECT  77.676 13.344 77.76 13.368 ;
    END
  END d[55]
  PIN d[560]
    DIRECTION INPUT ;
    USE SIGNAL ;
    PORT
      LAYER M4 ;
        RECT  77.676 61.92 77.76 61.944 ;
    END
  END d[560]
  PIN d[561]
    DIRECTION INPUT ;
    USE SIGNAL ;
    PORT
      LAYER M4 ;
        RECT  77.676 62.112 77.76 62.136 ;
    END
  END d[561]
  PIN d[562]
    DIRECTION INPUT ;
    USE SIGNAL ;
    PORT
      LAYER M4 ;
        RECT  77.676 62.208 77.76 62.232 ;
    END
  END d[562]
  PIN d[563]
    DIRECTION INPUT ;
    USE SIGNAL ;
    PORT
      LAYER M4 ;
        RECT  77.676 62.304 77.76 62.328 ;
    END
  END d[563]
  PIN d[564]
    DIRECTION INPUT ;
    USE SIGNAL ;
    PORT
      LAYER M4 ;
        RECT  77.676 62.4 77.76 62.424 ;
    END
  END d[564]
  PIN d[565]
    DIRECTION INPUT ;
    USE SIGNAL ;
    PORT
      LAYER M4 ;
        RECT  77.676 62.496 77.76 62.52 ;
    END
  END d[565]
  PIN d[566]
    DIRECTION INPUT ;
    USE SIGNAL ;
    PORT
      LAYER M4 ;
        RECT  77.676 62.592 77.76 62.616 ;
    END
  END d[566]
  PIN d[567]
    DIRECTION INPUT ;
    USE SIGNAL ;
    PORT
      LAYER M4 ;
        RECT  77.676 62.688 77.76 62.712 ;
    END
  END d[567]
  PIN d[568]
    DIRECTION INPUT ;
    USE SIGNAL ;
    PORT
      LAYER M4 ;
        RECT  77.676 62.784 77.76 62.808 ;
    END
  END d[568]
  PIN d[569]
    DIRECTION INPUT ;
    USE SIGNAL ;
    PORT
      LAYER M4 ;
        RECT  77.676 62.88 77.76 62.904 ;
    END
  END d[569]
  PIN d[56]
    DIRECTION INPUT ;
    USE SIGNAL ;
    PORT
      LAYER M4 ;
        RECT  77.676 13.536 77.76 13.56 ;
    END
  END d[56]
  PIN d[570]
    DIRECTION INPUT ;
    USE SIGNAL ;
    PORT
      LAYER M4 ;
        RECT  77.676 62.976 77.76 63 ;
    END
  END d[570]
  PIN d[571]
    DIRECTION INPUT ;
    USE SIGNAL ;
    PORT
      LAYER M4 ;
        RECT  77.676 63.072 77.76 63.096 ;
    END
  END d[571]
  PIN d[572]
    DIRECTION INPUT ;
    USE SIGNAL ;
    PORT
      LAYER M4 ;
        RECT  77.676 63.168 77.76 63.192 ;
    END
  END d[572]
  PIN d[573]
    DIRECTION INPUT ;
    USE SIGNAL ;
    PORT
      LAYER M4 ;
        RECT  77.676 63.264 77.76 63.288 ;
    END
  END d[573]
  PIN d[574]
    DIRECTION INPUT ;
    USE SIGNAL ;
    PORT
      LAYER M4 ;
        RECT  77.676 63.36 77.76 63.384 ;
    END
  END d[574]
  PIN d[575]
    DIRECTION INPUT ;
    USE SIGNAL ;
    PORT
      LAYER M4 ;
        RECT  77.676 63.456 77.76 63.48 ;
    END
  END d[575]
  PIN d[576]
    DIRECTION INPUT ;
    USE SIGNAL ;
    PORT
      LAYER M4 ;
        RECT  77.676 63.552 77.76 63.576 ;
    END
  END d[576]
  PIN d[577]
    DIRECTION INPUT ;
    USE SIGNAL ;
    PORT
      LAYER M4 ;
        RECT  77.676 63.648 77.76 63.672 ;
    END
  END d[577]
  PIN d[578]
    DIRECTION INPUT ;
    USE SIGNAL ;
    PORT
      LAYER M4 ;
        RECT  77.676 63.744 77.76 63.768 ;
    END
  END d[578]
  PIN d[579]
    DIRECTION INPUT ;
    USE SIGNAL ;
    PORT
      LAYER M4 ;
        RECT  77.676 63.936 77.76 63.96 ;
    END
  END d[579]
  PIN d[57]
    DIRECTION INPUT ;
    USE SIGNAL ;
    PORT
      LAYER M4 ;
        RECT  77.676 13.44 77.76 13.464 ;
    END
  END d[57]
  PIN d[580]
    DIRECTION INPUT ;
    USE SIGNAL ;
    PORT
      LAYER M4 ;
        RECT  77.676 63.84 77.76 63.864 ;
    END
  END d[580]
  PIN d[581]
    DIRECTION INPUT ;
    USE SIGNAL ;
    PORT
      LAYER M4 ;
        RECT  77.676 64.032 77.76 64.056 ;
    END
  END d[581]
  PIN d[582]
    DIRECTION INPUT ;
    USE SIGNAL ;
    PORT
      LAYER M4 ;
        RECT  77.676 64.128 77.76 64.152 ;
    END
  END d[582]
  PIN d[583]
    DIRECTION INPUT ;
    USE SIGNAL ;
    PORT
      LAYER M4 ;
        RECT  77.676 64.224 77.76 64.248 ;
    END
  END d[583]
  PIN d[584]
    DIRECTION INPUT ;
    USE SIGNAL ;
    PORT
      LAYER M4 ;
        RECT  77.676 64.32 77.76 64.344 ;
    END
  END d[584]
  PIN d[585]
    DIRECTION INPUT ;
    USE SIGNAL ;
    PORT
      LAYER M4 ;
        RECT  77.676 64.416 77.76 64.44 ;
    END
  END d[585]
  PIN d[586]
    DIRECTION INPUT ;
    USE SIGNAL ;
    PORT
      LAYER M4 ;
        RECT  77.676 64.512 77.76 64.536 ;
    END
  END d[586]
  PIN d[587]
    DIRECTION INPUT ;
    USE SIGNAL ;
    PORT
      LAYER M4 ;
        RECT  77.676 64.608 77.76 64.632 ;
    END
  END d[587]
  PIN d[588]
    DIRECTION INPUT ;
    USE SIGNAL ;
    PORT
      LAYER M4 ;
        RECT  77.676 64.704 77.76 64.728 ;
    END
  END d[588]
  PIN d[589]
    DIRECTION INPUT ;
    USE SIGNAL ;
    PORT
      LAYER M4 ;
        RECT  77.676 64.8 77.76 64.824 ;
    END
  END d[589]
  PIN d[58]
    DIRECTION INPUT ;
    USE SIGNAL ;
    PORT
      LAYER M4 ;
        RECT  77.676 13.632 77.76 13.656 ;
    END
  END d[58]
  PIN d[590]
    DIRECTION INPUT ;
    USE SIGNAL ;
    PORT
      LAYER M4 ;
        RECT  77.676 64.896 77.76 64.92 ;
    END
  END d[590]
  PIN d[591]
    DIRECTION INPUT ;
    USE SIGNAL ;
    PORT
      LAYER M4 ;
        RECT  77.676 64.992 77.76 65.016 ;
    END
  END d[591]
  PIN d[592]
    DIRECTION INPUT ;
    USE SIGNAL ;
    PORT
      LAYER M4 ;
        RECT  77.676 65.088 77.76 65.112 ;
    END
  END d[592]
  PIN d[593]
    DIRECTION INPUT ;
    USE SIGNAL ;
    PORT
      LAYER M4 ;
        RECT  77.676 65.184 77.76 65.208 ;
    END
  END d[593]
  PIN d[594]
    DIRECTION INPUT ;
    USE SIGNAL ;
    PORT
      LAYER M4 ;
        RECT  77.676 65.28 77.76 65.304 ;
    END
  END d[594]
  PIN d[595]
    DIRECTION INPUT ;
    USE SIGNAL ;
    PORT
      LAYER M4 ;
        RECT  77.676 65.376 77.76 65.4 ;
    END
  END d[595]
  PIN d[596]
    DIRECTION INPUT ;
    USE SIGNAL ;
    PORT
      LAYER M4 ;
        RECT  77.676 65.472 77.76 65.496 ;
    END
  END d[596]
  PIN d[597]
    DIRECTION INPUT ;
    USE SIGNAL ;
    PORT
      LAYER M4 ;
        RECT  77.676 65.568 77.76 65.592 ;
    END
  END d[597]
  PIN d[598]
    DIRECTION INPUT ;
    USE SIGNAL ;
    PORT
      LAYER M4 ;
        RECT  77.676 65.664 77.76 65.688 ;
    END
  END d[598]
  PIN d[599]
    DIRECTION INPUT ;
    USE SIGNAL ;
    PORT
      LAYER M4 ;
        RECT  77.676 65.952 77.76 65.976 ;
    END
  END d[599]
  PIN d[59]
    DIRECTION INPUT ;
    USE SIGNAL ;
    PORT
      LAYER M4 ;
        RECT  77.676 13.728 77.76 13.752 ;
    END
  END d[59]
  PIN d[5]
    DIRECTION INPUT ;
    USE SIGNAL ;
    PORT
      LAYER M4 ;
        RECT  77.676 8.544 77.76 8.568 ;
    END
  END d[5]
  PIN d[600]
    DIRECTION INPUT ;
    USE SIGNAL ;
    PORT
      LAYER M4 ;
        RECT  77.676 65.76 77.76 65.784 ;
    END
  END d[600]
  PIN d[601]
    DIRECTION INPUT ;
    USE SIGNAL ;
    PORT
      LAYER M4 ;
        RECT  77.676 66.048 77.76 66.072 ;
    END
  END d[601]
  PIN d[602]
    DIRECTION INPUT ;
    USE SIGNAL ;
    PORT
      LAYER M4 ;
        RECT  77.676 65.856 77.76 65.88 ;
    END
  END d[602]
  PIN d[603]
    DIRECTION INPUT ;
    USE SIGNAL ;
    PORT
      LAYER M4 ;
        RECT  77.676 66.144 77.76 66.168 ;
    END
  END d[603]
  PIN d[604]
    DIRECTION INPUT ;
    USE SIGNAL ;
    PORT
      LAYER M4 ;
        RECT  77.676 66.24 77.76 66.264 ;
    END
  END d[604]
  PIN d[605]
    DIRECTION INPUT ;
    USE SIGNAL ;
    PORT
      LAYER M4 ;
        RECT  77.676 66.336 77.76 66.36 ;
    END
  END d[605]
  PIN d[606]
    DIRECTION INPUT ;
    USE SIGNAL ;
    PORT
      LAYER M4 ;
        RECT  77.676 66.432 77.76 66.456 ;
    END
  END d[606]
  PIN d[607]
    DIRECTION INPUT ;
    USE SIGNAL ;
    PORT
      LAYER M4 ;
        RECT  77.676 66.528 77.76 66.552 ;
    END
  END d[607]
  PIN d[608]
    DIRECTION INPUT ;
    USE SIGNAL ;
    PORT
      LAYER M4 ;
        RECT  77.676 66.624 77.76 66.648 ;
    END
  END d[608]
  PIN d[609]
    DIRECTION INPUT ;
    USE SIGNAL ;
    PORT
      LAYER M4 ;
        RECT  77.676 66.72 77.76 66.744 ;
    END
  END d[609]
  PIN d[60]
    DIRECTION INPUT ;
    USE SIGNAL ;
    PORT
      LAYER M4 ;
        RECT  77.676 13.824 77.76 13.848 ;
    END
  END d[60]
  PIN d[610]
    DIRECTION INPUT ;
    USE SIGNAL ;
    PORT
      LAYER M4 ;
        RECT  77.676 66.816 77.76 66.84 ;
    END
  END d[610]
  PIN d[611]
    DIRECTION INPUT ;
    USE SIGNAL ;
    PORT
      LAYER M4 ;
        RECT  77.676 66.912 77.76 66.936 ;
    END
  END d[611]
  PIN d[612]
    DIRECTION INPUT ;
    USE SIGNAL ;
    PORT
      LAYER M4 ;
        RECT  77.676 67.008 77.76 67.032 ;
    END
  END d[612]
  PIN d[613]
    DIRECTION INPUT ;
    USE SIGNAL ;
    PORT
      LAYER M4 ;
        RECT  77.676 67.104 77.76 67.128 ;
    END
  END d[613]
  PIN d[614]
    DIRECTION INPUT ;
    USE SIGNAL ;
    PORT
      LAYER M4 ;
        RECT  77.676 67.2 77.76 67.224 ;
    END
  END d[614]
  PIN d[615]
    DIRECTION INPUT ;
    USE SIGNAL ;
    PORT
      LAYER M4 ;
        RECT  77.676 67.296 77.76 67.32 ;
    END
  END d[615]
  PIN d[616]
    DIRECTION INPUT ;
    USE SIGNAL ;
    PORT
      LAYER M4 ;
        RECT  77.676 67.392 77.76 67.416 ;
    END
  END d[616]
  PIN d[617]
    DIRECTION INPUT ;
    USE SIGNAL ;
    PORT
      LAYER M4 ;
        RECT  77.676 67.488 77.76 67.512 ;
    END
  END d[617]
  PIN d[618]
    DIRECTION INPUT ;
    USE SIGNAL ;
    PORT
      LAYER M4 ;
        RECT  77.676 67.584 77.76 67.608 ;
    END
  END d[618]
  PIN d[619]
    DIRECTION INPUT ;
    USE SIGNAL ;
    PORT
      LAYER M4 ;
        RECT  77.676 67.776 77.76 67.8 ;
    END
  END d[619]
  PIN d[61]
    DIRECTION INPUT ;
    USE SIGNAL ;
    PORT
      LAYER M4 ;
        RECT  77.676 13.92 77.76 13.944 ;
    END
  END d[61]
  PIN d[620]
    DIRECTION INPUT ;
    USE SIGNAL ;
    PORT
      LAYER M4 ;
        RECT  77.676 67.68 77.76 67.704 ;
    END
  END d[620]
  PIN d[621]
    DIRECTION INPUT ;
    USE SIGNAL ;
    PORT
      LAYER M4 ;
        RECT  77.676 67.968 77.76 67.992 ;
    END
  END d[621]
  PIN d[622]
    DIRECTION INPUT ;
    USE SIGNAL ;
    PORT
      LAYER M4 ;
        RECT  77.676 67.872 77.76 67.896 ;
    END
  END d[622]
  PIN d[623]
    DIRECTION INPUT ;
    USE SIGNAL ;
    PORT
      LAYER M4 ;
        RECT  77.676 68.064 77.76 68.088 ;
    END
  END d[623]
  PIN d[624]
    DIRECTION INPUT ;
    USE SIGNAL ;
    PORT
      LAYER M4 ;
        RECT  77.676 68.16 77.76 68.184 ;
    END
  END d[624]
  PIN d[625]
    DIRECTION INPUT ;
    USE SIGNAL ;
    PORT
      LAYER M4 ;
        RECT  77.676 68.256 77.76 68.28 ;
    END
  END d[625]
  PIN d[626]
    DIRECTION INPUT ;
    USE SIGNAL ;
    PORT
      LAYER M4 ;
        RECT  77.676 68.352 77.76 68.376 ;
    END
  END d[626]
  PIN d[627]
    DIRECTION INPUT ;
    USE SIGNAL ;
    PORT
      LAYER M4 ;
        RECT  77.676 68.448 77.76 68.472 ;
    END
  END d[627]
  PIN d[628]
    DIRECTION INPUT ;
    USE SIGNAL ;
    PORT
      LAYER M4 ;
        RECT  77.676 68.544 77.76 68.568 ;
    END
  END d[628]
  PIN d[629]
    DIRECTION INPUT ;
    USE SIGNAL ;
    PORT
      LAYER M4 ;
        RECT  77.676 68.64 77.76 68.664 ;
    END
  END d[629]
  PIN d[62]
    DIRECTION INPUT ;
    USE SIGNAL ;
    PORT
      LAYER M4 ;
        RECT  77.676 14.208 77.76 14.232 ;
    END
  END d[62]
  PIN d[630]
    DIRECTION INPUT ;
    USE SIGNAL ;
    PORT
      LAYER M4 ;
        RECT  77.676 68.736 77.76 68.76 ;
    END
  END d[630]
  PIN d[631]
    DIRECTION INPUT ;
    USE SIGNAL ;
    PORT
      LAYER M4 ;
        RECT  77.676 68.832 77.76 68.856 ;
    END
  END d[631]
  PIN d[632]
    DIRECTION INPUT ;
    USE SIGNAL ;
    PORT
      LAYER M4 ;
        RECT  77.676 68.928 77.76 68.952 ;
    END
  END d[632]
  PIN d[633]
    DIRECTION INPUT ;
    USE SIGNAL ;
    PORT
      LAYER M4 ;
        RECT  77.676 69.024 77.76 69.048 ;
    END
  END d[633]
  PIN d[634]
    DIRECTION INPUT ;
    USE SIGNAL ;
    PORT
      LAYER M4 ;
        RECT  77.676 69.12 77.76 69.144 ;
    END
  END d[634]
  PIN d[635]
    DIRECTION INPUT ;
    USE SIGNAL ;
    PORT
      LAYER M4 ;
        RECT  77.676 69.216 77.76 69.24 ;
    END
  END d[635]
  PIN d[636]
    DIRECTION INPUT ;
    USE SIGNAL ;
    PORT
      LAYER M4 ;
        RECT  77.676 69.312 77.76 69.336 ;
    END
  END d[636]
  PIN d[637]
    DIRECTION INPUT ;
    USE SIGNAL ;
    PORT
      LAYER M4 ;
        RECT  77.676 69.408 77.76 69.432 ;
    END
  END d[637]
  PIN d[638]
    DIRECTION INPUT ;
    USE SIGNAL ;
    PORT
      LAYER M4 ;
        RECT  77.676 69.504 77.76 69.528 ;
    END
  END d[638]
  PIN d[639]
    DIRECTION INPUT ;
    USE SIGNAL ;
    PORT
      LAYER M4 ;
        RECT  77.676 69.6 77.76 69.624 ;
    END
  END d[639]
  PIN d[63]
    DIRECTION INPUT ;
    USE SIGNAL ;
    PORT
      LAYER M4 ;
        RECT  77.676 14.016 77.76 14.04 ;
    END
  END d[63]
  PIN d[640]
    DIRECTION INPUT ;
    USE SIGNAL ;
    PORT
      LAYER M4 ;
        RECT  77.676 69.696 77.76 69.72 ;
    END
  END d[640]
  PIN d[641]
    DIRECTION INPUT ;
    USE SIGNAL ;
    PORT
      LAYER M4 ;
        RECT  77.676 69.888 77.76 69.912 ;
    END
  END d[641]
  PIN d[642]
    DIRECTION INPUT ;
    USE SIGNAL ;
    PORT
      LAYER M4 ;
        RECT  77.676 69.792 77.76 69.816 ;
    END
  END d[642]
  PIN d[643]
    DIRECTION INPUT ;
    USE SIGNAL ;
    PORT
      LAYER M4 ;
        RECT  77.676 69.984 77.76 70.008 ;
    END
  END d[643]
  PIN d[644]
    DIRECTION INPUT ;
    USE SIGNAL ;
    PORT
      LAYER M4 ;
        RECT  77.676 70.08 77.76 70.104 ;
    END
  END d[644]
  PIN d[645]
    DIRECTION INPUT ;
    USE SIGNAL ;
    PORT
      LAYER M4 ;
        RECT  77.676 70.176 77.76 70.2 ;
    END
  END d[645]
  PIN d[646]
    DIRECTION INPUT ;
    USE SIGNAL ;
    PORT
      LAYER M4 ;
        RECT  77.676 70.272 77.76 70.296 ;
    END
  END d[646]
  PIN d[647]
    DIRECTION INPUT ;
    USE SIGNAL ;
    PORT
      LAYER M4 ;
        RECT  77.676 70.368 77.76 70.392 ;
    END
  END d[647]
  PIN d[648]
    DIRECTION INPUT ;
    USE SIGNAL ;
    PORT
      LAYER M4 ;
        RECT  77.676 70.464 77.76 70.488 ;
    END
  END d[648]
  PIN d[649]
    DIRECTION INPUT ;
    USE SIGNAL ;
    PORT
      LAYER M4 ;
        RECT  77.676 70.56 77.76 70.584 ;
    END
  END d[649]
  PIN d[64]
    DIRECTION INPUT ;
    USE SIGNAL ;
    PORT
      LAYER M4 ;
        RECT  77.676 14.304 77.76 14.328 ;
    END
  END d[64]
  PIN d[650]
    DIRECTION INPUT ;
    USE SIGNAL ;
    PORT
      LAYER M4 ;
        RECT  77.676 70.656 77.76 70.68 ;
    END
  END d[650]
  PIN d[651]
    DIRECTION INPUT ;
    USE SIGNAL ;
    PORT
      LAYER M4 ;
        RECT  77.676 70.752 77.76 70.776 ;
    END
  END d[651]
  PIN d[652]
    DIRECTION INPUT ;
    USE SIGNAL ;
    PORT
      LAYER M4 ;
        RECT  77.676 70.848 77.76 70.872 ;
    END
  END d[652]
  PIN d[653]
    DIRECTION INPUT ;
    USE SIGNAL ;
    PORT
      LAYER M4 ;
        RECT  77.676 70.944 77.76 70.968 ;
    END
  END d[653]
  PIN d[654]
    DIRECTION INPUT ;
    USE SIGNAL ;
    PORT
      LAYER M4 ;
        RECT  77.676 71.04 77.76 71.064 ;
    END
  END d[654]
  PIN d[655]
    DIRECTION INPUT ;
    USE SIGNAL ;
    PORT
      LAYER M4 ;
        RECT  77.676 71.136 77.76 71.16 ;
    END
  END d[655]
  PIN d[656]
    DIRECTION INPUT ;
    USE SIGNAL ;
    PORT
      LAYER M4 ;
        RECT  77.676 71.232 77.76 71.256 ;
    END
  END d[656]
  PIN d[657]
    DIRECTION INPUT ;
    USE SIGNAL ;
    PORT
      LAYER M4 ;
        RECT  77.676 71.328 77.76 71.352 ;
    END
  END d[657]
  PIN d[658]
    DIRECTION INPUT ;
    USE SIGNAL ;
    PORT
      LAYER M4 ;
        RECT  77.676 71.424 77.76 71.448 ;
    END
  END d[658]
  PIN d[659]
    DIRECTION INPUT ;
    USE SIGNAL ;
    PORT
      LAYER M4 ;
        RECT  77.676 71.52 77.76 71.544 ;
    END
  END d[659]
  PIN d[65]
    DIRECTION INPUT ;
    USE SIGNAL ;
    PORT
      LAYER M4 ;
        RECT  77.676 14.112 77.76 14.136 ;
    END
  END d[65]
  PIN d[660]
    DIRECTION INPUT ;
    USE SIGNAL ;
    PORT
      LAYER M4 ;
        RECT  77.676 71.616 77.76 71.64 ;
    END
  END d[660]
  PIN d[661]
    DIRECTION INPUT ;
    USE SIGNAL ;
    PORT
      LAYER M4 ;
        RECT  77.676 71.904 77.76 71.928 ;
    END
  END d[661]
  PIN d[662]
    DIRECTION INPUT ;
    USE SIGNAL ;
    PORT
      LAYER M4 ;
        RECT  77.676 71.712 77.76 71.736 ;
    END
  END d[662]
  PIN d[663]
    DIRECTION INPUT ;
    USE SIGNAL ;
    PORT
      LAYER M4 ;
        RECT  77.676 72 77.76 72.024 ;
    END
  END d[663]
  PIN d[664]
    DIRECTION INPUT ;
    USE SIGNAL ;
    PORT
      LAYER M4 ;
        RECT  77.676 71.808 77.76 71.832 ;
    END
  END d[664]
  PIN d[665]
    DIRECTION INPUT ;
    USE SIGNAL ;
    PORT
      LAYER M4 ;
        RECT  77.676 72.096 77.76 72.12 ;
    END
  END d[665]
  PIN d[666]
    DIRECTION INPUT ;
    USE SIGNAL ;
    PORT
      LAYER M4 ;
        RECT  77.676 72.192 77.76 72.216 ;
    END
  END d[666]
  PIN d[667]
    DIRECTION INPUT ;
    USE SIGNAL ;
    PORT
      LAYER M4 ;
        RECT  77.676 72.288 77.76 72.312 ;
    END
  END d[667]
  PIN d[668]
    DIRECTION INPUT ;
    USE SIGNAL ;
    PORT
      LAYER M4 ;
        RECT  77.676 72.384 77.76 72.408 ;
    END
  END d[668]
  PIN d[669]
    DIRECTION INPUT ;
    USE SIGNAL ;
    PORT
      LAYER M4 ;
        RECT  77.676 72.48 77.76 72.504 ;
    END
  END d[669]
  PIN d[66]
    DIRECTION INPUT ;
    USE SIGNAL ;
    PORT
      LAYER M4 ;
        RECT  77.676 14.4 77.76 14.424 ;
    END
  END d[66]
  PIN d[670]
    DIRECTION INPUT ;
    USE SIGNAL ;
    PORT
      LAYER M4 ;
        RECT  77.676 72.576 77.76 72.6 ;
    END
  END d[670]
  PIN d[671]
    DIRECTION INPUT ;
    USE SIGNAL ;
    PORT
      LAYER M4 ;
        RECT  77.676 72.672 77.76 72.696 ;
    END
  END d[671]
  PIN d[672]
    DIRECTION INPUT ;
    USE SIGNAL ;
    PORT
      LAYER M4 ;
        RECT  77.676 72.768 77.76 72.792 ;
    END
  END d[672]
  PIN d[673]
    DIRECTION INPUT ;
    USE SIGNAL ;
    PORT
      LAYER M4 ;
        RECT  77.676 72.864 77.76 72.888 ;
    END
  END d[673]
  PIN d[674]
    DIRECTION INPUT ;
    USE SIGNAL ;
    PORT
      LAYER M4 ;
        RECT  77.676 72.96 77.76 72.984 ;
    END
  END d[674]
  PIN d[675]
    DIRECTION INPUT ;
    USE SIGNAL ;
    PORT
      LAYER M4 ;
        RECT  77.676 73.056 77.76 73.08 ;
    END
  END d[675]
  PIN d[676]
    DIRECTION INPUT ;
    USE SIGNAL ;
    PORT
      LAYER M4 ;
        RECT  77.676 73.152 77.76 73.176 ;
    END
  END d[676]
  PIN d[677]
    DIRECTION INPUT ;
    USE SIGNAL ;
    PORT
      LAYER M4 ;
        RECT  77.676 73.248 77.76 73.272 ;
    END
  END d[677]
  PIN d[678]
    DIRECTION INPUT ;
    USE SIGNAL ;
    PORT
      LAYER M4 ;
        RECT  77.676 73.344 77.76 73.368 ;
    END
  END d[678]
  PIN d[679]
    DIRECTION INPUT ;
    USE SIGNAL ;
    PORT
      LAYER M4 ;
        RECT  77.676 73.44 77.76 73.464 ;
    END
  END d[679]
  PIN d[67]
    DIRECTION INPUT ;
    USE SIGNAL ;
    PORT
      LAYER M4 ;
        RECT  77.676 14.496 77.76 14.52 ;
    END
  END d[67]
  PIN d[680]
    DIRECTION INPUT ;
    USE SIGNAL ;
    PORT
      LAYER M4 ;
        RECT  77.676 73.536 77.76 73.56 ;
    END
  END d[680]
  PIN d[681]
    DIRECTION INPUT ;
    USE SIGNAL ;
    PORT
      LAYER M4 ;
        RECT  77.676 73.728 77.76 73.752 ;
    END
  END d[681]
  PIN d[682]
    DIRECTION INPUT ;
    USE SIGNAL ;
    PORT
      LAYER M4 ;
        RECT  77.676 73.632 77.76 73.656 ;
    END
  END d[682]
  PIN d[683]
    DIRECTION INPUT ;
    USE SIGNAL ;
    PORT
      LAYER M4 ;
        RECT  77.676 73.92 77.76 73.944 ;
    END
  END d[683]
  PIN d[684]
    DIRECTION INPUT ;
    USE SIGNAL ;
    PORT
      LAYER M4 ;
        RECT  77.676 73.824 77.76 73.848 ;
    END
  END d[684]
  PIN d[685]
    DIRECTION INPUT ;
    USE SIGNAL ;
    PORT
      LAYER M4 ;
        RECT  77.676 74.016 77.76 74.04 ;
    END
  END d[685]
  PIN d[686]
    DIRECTION INPUT ;
    USE SIGNAL ;
    PORT
      LAYER M4 ;
        RECT  77.676 74.112 77.76 74.136 ;
    END
  END d[686]
  PIN d[687]
    DIRECTION INPUT ;
    USE SIGNAL ;
    PORT
      LAYER M4 ;
        RECT  77.676 74.208 77.76 74.232 ;
    END
  END d[687]
  PIN d[688]
    DIRECTION INPUT ;
    USE SIGNAL ;
    PORT
      LAYER M4 ;
        RECT  77.676 74.304 77.76 74.328 ;
    END
  END d[688]
  PIN d[689]
    DIRECTION INPUT ;
    USE SIGNAL ;
    PORT
      LAYER M4 ;
        RECT  77.676 74.4 77.76 74.424 ;
    END
  END d[689]
  PIN d[68]
    DIRECTION INPUT ;
    USE SIGNAL ;
    PORT
      LAYER M4 ;
        RECT  77.676 14.688 77.76 14.712 ;
    END
  END d[68]
  PIN d[690]
    DIRECTION INPUT ;
    USE SIGNAL ;
    PORT
      LAYER M4 ;
        RECT  77.676 74.496 77.76 74.52 ;
    END
  END d[690]
  PIN d[691]
    DIRECTION INPUT ;
    USE SIGNAL ;
    PORT
      LAYER M4 ;
        RECT  77.676 74.688 77.76 74.712 ;
    END
  END d[691]
  PIN d[692]
    DIRECTION INPUT ;
    USE SIGNAL ;
    PORT
      LAYER M4 ;
        RECT  77.676 74.592 77.76 74.616 ;
    END
  END d[692]
  PIN d[693]
    DIRECTION INPUT ;
    USE SIGNAL ;
    PORT
      LAYER M4 ;
        RECT  77.676 74.784 77.76 74.808 ;
    END
  END d[693]
  PIN d[694]
    DIRECTION INPUT ;
    USE SIGNAL ;
    PORT
      LAYER M4 ;
        RECT  77.676 74.88 77.76 74.904 ;
    END
  END d[694]
  PIN d[695]
    DIRECTION INPUT ;
    USE SIGNAL ;
    PORT
      LAYER M4 ;
        RECT  77.676 74.976 77.76 75 ;
    END
  END d[695]
  PIN d[696]
    DIRECTION INPUT ;
    USE SIGNAL ;
    PORT
      LAYER M4 ;
        RECT  77.676 75.072 77.76 75.096 ;
    END
  END d[696]
  PIN d[697]
    DIRECTION INPUT ;
    USE SIGNAL ;
    PORT
      LAYER M4 ;
        RECT  77.676 75.168 77.76 75.192 ;
    END
  END d[697]
  PIN d[698]
    DIRECTION INPUT ;
    USE SIGNAL ;
    PORT
      LAYER M4 ;
        RECT  77.676 75.264 77.76 75.288 ;
    END
  END d[698]
  PIN d[699]
    DIRECTION INPUT ;
    USE SIGNAL ;
    PORT
      LAYER M4 ;
        RECT  77.676 75.36 77.76 75.384 ;
    END
  END d[699]
  PIN d[69]
    DIRECTION INPUT ;
    USE SIGNAL ;
    PORT
      LAYER M4 ;
        RECT  77.676 14.592 77.76 14.616 ;
    END
  END d[69]
  PIN d[6]
    DIRECTION INPUT ;
    USE SIGNAL ;
    PORT
      LAYER M4 ;
        RECT  77.676 8.64 77.76 8.664 ;
    END
  END d[6]
  PIN d[700]
    DIRECTION INPUT ;
    USE SIGNAL ;
    PORT
      LAYER M4 ;
        RECT  77.676 75.456 77.76 75.48 ;
    END
  END d[700]
  PIN d[701]
    DIRECTION INPUT ;
    USE SIGNAL ;
    PORT
      LAYER M4 ;
        RECT  77.676 75.552 77.76 75.576 ;
    END
  END d[701]
  PIN d[702]
    DIRECTION INPUT ;
    USE SIGNAL ;
    PORT
      LAYER M4 ;
        RECT  77.676 75.648 77.76 75.672 ;
    END
  END d[702]
  PIN d[703]
    DIRECTION INPUT ;
    USE SIGNAL ;
    PORT
      LAYER M4 ;
        RECT  77.676 75.84 77.76 75.864 ;
    END
  END d[703]
  PIN d[704]
    DIRECTION INPUT ;
    USE SIGNAL ;
    PORT
      LAYER M4 ;
        RECT  77.676 75.744 77.76 75.768 ;
    END
  END d[704]
  PIN d[705]
    DIRECTION INPUT ;
    USE SIGNAL ;
    PORT
      LAYER M4 ;
        RECT  77.676 75.936 77.76 75.96 ;
    END
  END d[705]
  PIN d[706]
    DIRECTION INPUT ;
    USE SIGNAL ;
    PORT
      LAYER M4 ;
        RECT  77.676 76.032 77.76 76.056 ;
    END
  END d[706]
  PIN d[707]
    DIRECTION INPUT ;
    USE SIGNAL ;
    PORT
      LAYER M4 ;
        RECT  77.676 76.128 77.76 76.152 ;
    END
  END d[707]
  PIN d[708]
    DIRECTION INPUT ;
    USE SIGNAL ;
    PORT
      LAYER M4 ;
        RECT  77.676 76.224 77.76 76.248 ;
    END
  END d[708]
  PIN d[709]
    DIRECTION INPUT ;
    USE SIGNAL ;
    PORT
      LAYER M4 ;
        RECT  77.676 76.32 77.76 76.344 ;
    END
  END d[709]
  PIN d[70]
    DIRECTION INPUT ;
    USE SIGNAL ;
    PORT
      LAYER M4 ;
        RECT  77.676 14.784 77.76 14.808 ;
    END
  END d[70]
  PIN d[710]
    DIRECTION INPUT ;
    USE SIGNAL ;
    PORT
      LAYER M4 ;
        RECT  77.676 76.416 77.76 76.44 ;
    END
  END d[710]
  PIN d[711]
    DIRECTION INPUT ;
    USE SIGNAL ;
    PORT
      LAYER M4 ;
        RECT  77.676 76.608 77.76 76.632 ;
    END
  END d[711]
  PIN d[712]
    DIRECTION INPUT ;
    USE SIGNAL ;
    PORT
      LAYER M4 ;
        RECT  77.676 76.512 77.76 76.536 ;
    END
  END d[712]
  PIN d[713]
    DIRECTION INPUT ;
    USE SIGNAL ;
    PORT
      LAYER M4 ;
        RECT  77.676 76.704 77.76 76.728 ;
    END
  END d[713]
  PIN d[714]
    DIRECTION INPUT ;
    USE SIGNAL ;
    PORT
      LAYER M4 ;
        RECT  77.676 76.8 77.76 76.824 ;
    END
  END d[714]
  PIN d[715]
    DIRECTION INPUT ;
    USE SIGNAL ;
    PORT
      LAYER M4 ;
        RECT  77.676 76.896 77.76 76.92 ;
    END
  END d[715]
  PIN d[716]
    DIRECTION INPUT ;
    USE SIGNAL ;
    PORT
      LAYER M4 ;
        RECT  77.676 76.992 77.76 77.016 ;
    END
  END d[716]
  PIN d[717]
    DIRECTION INPUT ;
    USE SIGNAL ;
    PORT
      LAYER M4 ;
        RECT  77.676 77.088 77.76 77.112 ;
    END
  END d[717]
  PIN d[718]
    DIRECTION INPUT ;
    USE SIGNAL ;
    PORT
      LAYER M4 ;
        RECT  77.676 77.184 77.76 77.208 ;
    END
  END d[718]
  PIN d[719]
    DIRECTION INPUT ;
    USE SIGNAL ;
    PORT
      LAYER M4 ;
        RECT  77.676 77.28 77.76 77.304 ;
    END
  END d[719]
  PIN d[71]
    DIRECTION INPUT ;
    USE SIGNAL ;
    PORT
      LAYER M4 ;
        RECT  77.676 14.88 77.76 14.904 ;
    END
  END d[71]
  PIN d[720]
    DIRECTION INPUT ;
    USE SIGNAL ;
    PORT
      LAYER M4 ;
        RECT  77.676 77.376 77.76 77.4 ;
    END
  END d[720]
  PIN d[721]
    DIRECTION INPUT ;
    USE SIGNAL ;
    PORT
      LAYER M4 ;
        RECT  77.676 77.472 77.76 77.496 ;
    END
  END d[721]
  PIN d[722]
    DIRECTION INPUT ;
    USE SIGNAL ;
    PORT
      LAYER M4 ;
        RECT  77.676 77.568 77.76 77.592 ;
    END
  END d[722]
  PIN d[723]
    DIRECTION INPUT ;
    USE SIGNAL ;
    PORT
      LAYER M4 ;
        RECT  77.676 77.856 77.76 77.88 ;
    END
  END d[723]
  PIN d[724]
    DIRECTION INPUT ;
    USE SIGNAL ;
    PORT
      LAYER M4 ;
        RECT  77.676 77.664 77.76 77.688 ;
    END
  END d[724]
  PIN d[725]
    DIRECTION INPUT ;
    USE SIGNAL ;
    PORT
      LAYER M4 ;
        RECT  77.676 77.952 77.76 77.976 ;
    END
  END d[725]
  PIN d[726]
    DIRECTION INPUT ;
    USE SIGNAL ;
    PORT
      LAYER M4 ;
        RECT  77.676 77.76 77.76 77.784 ;
    END
  END d[726]
  PIN d[727]
    DIRECTION INPUT ;
    USE SIGNAL ;
    PORT
      LAYER M4 ;
        RECT  77.676 78.048 77.76 78.072 ;
    END
  END d[727]
  PIN d[728]
    DIRECTION INPUT ;
    USE SIGNAL ;
    PORT
      LAYER M4 ;
        RECT  77.676 78.144 77.76 78.168 ;
    END
  END d[728]
  PIN d[729]
    DIRECTION INPUT ;
    USE SIGNAL ;
    PORT
      LAYER M4 ;
        RECT  77.676 78.24 77.76 78.264 ;
    END
  END d[729]
  PIN d[72]
    DIRECTION INPUT ;
    USE SIGNAL ;
    PORT
      LAYER M4 ;
        RECT  77.676 14.976 77.76 15 ;
    END
  END d[72]
  PIN d[730]
    DIRECTION INPUT ;
    USE SIGNAL ;
    PORT
      LAYER M4 ;
        RECT  77.676 78.336 77.76 78.36 ;
    END
  END d[730]
  PIN d[731]
    DIRECTION INPUT ;
    USE SIGNAL ;
    PORT
      LAYER M4 ;
        RECT  77.676 78.432 77.76 78.456 ;
    END
  END d[731]
  PIN d[732]
    DIRECTION INPUT ;
    USE SIGNAL ;
    PORT
      LAYER M4 ;
        RECT  77.676 78.528 77.76 78.552 ;
    END
  END d[732]
  PIN d[733]
    DIRECTION INPUT ;
    USE SIGNAL ;
    PORT
      LAYER M4 ;
        RECT  77.676 78.624 77.76 78.648 ;
    END
  END d[733]
  PIN d[734]
    DIRECTION INPUT ;
    USE SIGNAL ;
    PORT
      LAYER M4 ;
        RECT  77.676 78.72 77.76 78.744 ;
    END
  END d[734]
  PIN d[735]
    DIRECTION INPUT ;
    USE SIGNAL ;
    PORT
      LAYER M4 ;
        RECT  77.676 78.816 77.76 78.84 ;
    END
  END d[735]
  PIN d[736]
    DIRECTION INPUT ;
    USE SIGNAL ;
    PORT
      LAYER M4 ;
        RECT  77.676 78.912 77.76 78.936 ;
    END
  END d[736]
  PIN d[737]
    DIRECTION INPUT ;
    USE SIGNAL ;
    PORT
      LAYER M4 ;
        RECT  77.676 79.104 77.76 79.128 ;
    END
  END d[737]
  PIN d[738]
    DIRECTION INPUT ;
    USE SIGNAL ;
    PORT
      LAYER M4 ;
        RECT  77.676 79.008 77.76 79.032 ;
    END
  END d[738]
  PIN d[739]
    DIRECTION INPUT ;
    USE SIGNAL ;
    PORT
      LAYER M4 ;
        RECT  77.676 79.2 77.76 79.224 ;
    END
  END d[739]
  PIN d[73]
    DIRECTION INPUT ;
    USE SIGNAL ;
    PORT
      LAYER M4 ;
        RECT  77.676 15.072 77.76 15.096 ;
    END
  END d[73]
  PIN d[740]
    DIRECTION INPUT ;
    USE SIGNAL ;
    PORT
      LAYER M4 ;
        RECT  77.676 79.296 77.76 79.32 ;
    END
  END d[740]
  PIN d[741]
    DIRECTION INPUT ;
    USE SIGNAL ;
    PORT
      LAYER M4 ;
        RECT  77.676 79.392 77.76 79.416 ;
    END
  END d[741]
  PIN d[742]
    DIRECTION INPUT ;
    USE SIGNAL ;
    PORT
      LAYER M4 ;
        RECT  77.676 79.488 77.76 79.512 ;
    END
  END d[742]
  PIN d[743]
    DIRECTION INPUT ;
    USE SIGNAL ;
    PORT
      LAYER M4 ;
        RECT  77.676 79.68 77.76 79.704 ;
    END
  END d[743]
  PIN d[744]
    DIRECTION INPUT ;
    USE SIGNAL ;
    PORT
      LAYER M4 ;
        RECT  77.676 79.584 77.76 79.608 ;
    END
  END d[744]
  PIN d[745]
    DIRECTION INPUT ;
    USE SIGNAL ;
    PORT
      LAYER M4 ;
        RECT  77.676 79.872 77.76 79.896 ;
    END
  END d[745]
  PIN d[746]
    DIRECTION INPUT ;
    USE SIGNAL ;
    PORT
      LAYER M4 ;
        RECT  77.676 79.776 77.76 79.8 ;
    END
  END d[746]
  PIN d[747]
    DIRECTION INPUT ;
    USE SIGNAL ;
    PORT
      LAYER M4 ;
        RECT  77.676 79.968 77.76 79.992 ;
    END
  END d[747]
  PIN d[748]
    DIRECTION INPUT ;
    USE SIGNAL ;
    PORT
      LAYER M4 ;
        RECT  77.676 80.064 77.76 80.088 ;
    END
  END d[748]
  PIN d[749]
    DIRECTION INPUT ;
    USE SIGNAL ;
    PORT
      LAYER M4 ;
        RECT  77.676 80.256 77.76 80.28 ;
    END
  END d[749]
  PIN d[74]
    DIRECTION INPUT ;
    USE SIGNAL ;
    PORT
      LAYER M4 ;
        RECT  77.676 15.168 77.76 15.192 ;
    END
  END d[74]
  PIN d[750]
    DIRECTION INPUT ;
    USE SIGNAL ;
    PORT
      LAYER M4 ;
        RECT  77.676 80.16 77.76 80.184 ;
    END
  END d[750]
  PIN d[751]
    DIRECTION INPUT ;
    USE SIGNAL ;
    PORT
      LAYER M4 ;
        RECT  77.676 80.352 77.76 80.376 ;
    END
  END d[751]
  PIN d[752]
    DIRECTION INPUT ;
    USE SIGNAL ;
    PORT
      LAYER M4 ;
        RECT  77.676 80.448 77.76 80.472 ;
    END
  END d[752]
  PIN d[753]
    DIRECTION INPUT ;
    USE SIGNAL ;
    PORT
      LAYER M4 ;
        RECT  77.676 80.544 77.76 80.568 ;
    END
  END d[753]
  PIN d[754]
    DIRECTION INPUT ;
    USE SIGNAL ;
    PORT
      LAYER M4 ;
        RECT  77.676 80.64 77.76 80.664 ;
    END
  END d[754]
  PIN d[755]
    DIRECTION INPUT ;
    USE SIGNAL ;
    PORT
      LAYER M4 ;
        RECT  77.676 80.736 77.76 80.76 ;
    END
  END d[755]
  PIN d[756]
    DIRECTION INPUT ;
    USE SIGNAL ;
    PORT
      LAYER M4 ;
        RECT  77.676 80.832 77.76 80.856 ;
    END
  END d[756]
  PIN d[757]
    DIRECTION INPUT ;
    USE SIGNAL ;
    PORT
      LAYER M4 ;
        RECT  77.676 81.024 77.76 81.048 ;
    END
  END d[757]
  PIN d[758]
    DIRECTION INPUT ;
    USE SIGNAL ;
    PORT
      LAYER M4 ;
        RECT  77.676 80.928 77.76 80.952 ;
    END
  END d[758]
  PIN d[759]
    DIRECTION INPUT ;
    USE SIGNAL ;
    PORT
      LAYER M4 ;
        RECT  77.676 81.12 77.76 81.144 ;
    END
  END d[759]
  PIN d[75]
    DIRECTION INPUT ;
    USE SIGNAL ;
    PORT
      LAYER M4 ;
        RECT  77.676 15.264 77.76 15.288 ;
    END
  END d[75]
  PIN d[760]
    DIRECTION INPUT ;
    USE SIGNAL ;
    PORT
      LAYER M4 ;
        RECT  77.676 81.216 77.76 81.24 ;
    END
  END d[760]
  PIN d[761]
    DIRECTION INPUT ;
    USE SIGNAL ;
    PORT
      LAYER M4 ;
        RECT  77.676 81.408 77.76 81.432 ;
    END
  END d[761]
  PIN d[762]
    DIRECTION INPUT ;
    USE SIGNAL ;
    PORT
      LAYER M4 ;
        RECT  77.676 81.312 77.76 81.336 ;
    END
  END d[762]
  PIN d[763]
    DIRECTION INPUT ;
    USE SIGNAL ;
    PORT
      LAYER M4 ;
        RECT  77.676 81.504 77.76 81.528 ;
    END
  END d[763]
  PIN d[764]
    DIRECTION INPUT ;
    USE SIGNAL ;
    PORT
      LAYER M4 ;
        RECT  77.676 81.6 77.76 81.624 ;
    END
  END d[764]
  PIN d[765]
    DIRECTION INPUT ;
    USE SIGNAL ;
    PORT
      LAYER M4 ;
        RECT  77.676 81.792 77.76 81.816 ;
    END
  END d[765]
  PIN d[766]
    DIRECTION INPUT ;
    USE SIGNAL ;
    PORT
      LAYER M4 ;
        RECT  77.676 81.696 77.76 81.72 ;
    END
  END d[766]
  PIN d[76]
    DIRECTION INPUT ;
    USE SIGNAL ;
    PORT
      LAYER M4 ;
        RECT  77.676 15.36 77.76 15.384 ;
    END
  END d[76]
  PIN d[77]
    DIRECTION INPUT ;
    USE SIGNAL ;
    PORT
      LAYER M4 ;
        RECT  77.676 15.456 77.76 15.48 ;
    END
  END d[77]
  PIN d[78]
    DIRECTION INPUT ;
    USE SIGNAL ;
    PORT
      LAYER M4 ;
        RECT  77.676 15.552 77.76 15.576 ;
    END
  END d[78]
  PIN d[79]
    DIRECTION INPUT ;
    USE SIGNAL ;
    PORT
      LAYER M4 ;
        RECT  77.676 15.648 77.76 15.672 ;
    END
  END d[79]
  PIN d[7]
    DIRECTION INPUT ;
    USE SIGNAL ;
    PORT
      LAYER M4 ;
        RECT  77.676 8.736 77.76 8.76 ;
    END
  END d[7]
  PIN d[80]
    DIRECTION INPUT ;
    USE SIGNAL ;
    PORT
      LAYER M4 ;
        RECT  77.676 15.744 77.76 15.768 ;
    END
  END d[80]
  PIN d[81]
    DIRECTION INPUT ;
    USE SIGNAL ;
    PORT
      LAYER M4 ;
        RECT  77.676 15.84 77.76 15.864 ;
    END
  END d[81]
  PIN d[82]
    DIRECTION INPUT ;
    USE SIGNAL ;
    PORT
      LAYER M4 ;
        RECT  77.676 15.936 77.76 15.96 ;
    END
  END d[82]
  PIN d[83]
    DIRECTION INPUT ;
    USE SIGNAL ;
    PORT
      LAYER M4 ;
        RECT  77.676 16.032 77.76 16.056 ;
    END
  END d[83]
  PIN d[84]
    DIRECTION INPUT ;
    USE SIGNAL ;
    PORT
      LAYER M4 ;
        RECT  77.676 16.224 77.76 16.248 ;
    END
  END d[84]
  PIN d[85]
    DIRECTION INPUT ;
    USE SIGNAL ;
    PORT
      LAYER M4 ;
        RECT  77.676 16.128 77.76 16.152 ;
    END
  END d[85]
  PIN d[86]
    DIRECTION INPUT ;
    USE SIGNAL ;
    PORT
      LAYER M4 ;
        RECT  77.676 16.32 77.76 16.344 ;
    END
  END d[86]
  PIN d[87]
    DIRECTION INPUT ;
    USE SIGNAL ;
    PORT
      LAYER M4 ;
        RECT  77.676 16.416 77.76 16.44 ;
    END
  END d[87]
  PIN d[88]
    DIRECTION INPUT ;
    USE SIGNAL ;
    PORT
      LAYER M4 ;
        RECT  77.676 16.512 77.76 16.536 ;
    END
  END d[88]
  PIN d[89]
    DIRECTION INPUT ;
    USE SIGNAL ;
    PORT
      LAYER M4 ;
        RECT  77.676 16.608 77.76 16.632 ;
    END
  END d[89]
  PIN d[8]
    DIRECTION INPUT ;
    USE SIGNAL ;
    PORT
      LAYER M4 ;
        RECT  77.676 8.832 77.76 8.856 ;
    END
  END d[8]
  PIN d[90]
    DIRECTION INPUT ;
    USE SIGNAL ;
    PORT
      LAYER M4 ;
        RECT  77.676 16.704 77.76 16.728 ;
    END
  END d[90]
  PIN d[91]
    DIRECTION INPUT ;
    USE SIGNAL ;
    PORT
      LAYER M4 ;
        RECT  77.676 16.8 77.76 16.824 ;
    END
  END d[91]
  PIN d[92]
    DIRECTION INPUT ;
    USE SIGNAL ;
    PORT
      LAYER M4 ;
        RECT  77.676 16.896 77.76 16.92 ;
    END
  END d[92]
  PIN d[93]
    DIRECTION INPUT ;
    USE SIGNAL ;
    PORT
      LAYER M4 ;
        RECT  77.676 16.992 77.76 17.016 ;
    END
  END d[93]
  PIN d[94]
    DIRECTION INPUT ;
    USE SIGNAL ;
    PORT
      LAYER M4 ;
        RECT  77.676 17.088 77.76 17.112 ;
    END
  END d[94]
  PIN d[95]
    DIRECTION INPUT ;
    USE SIGNAL ;
    PORT
      LAYER M4 ;
        RECT  77.676 17.184 77.76 17.208 ;
    END
  END d[95]
  PIN d[96]
    DIRECTION INPUT ;
    USE SIGNAL ;
    PORT
      LAYER M4 ;
        RECT  77.676 17.28 77.76 17.304 ;
    END
  END d[96]
  PIN d[97]
    DIRECTION INPUT ;
    USE SIGNAL ;
    PORT
      LAYER M4 ;
        RECT  77.676 17.376 77.76 17.4 ;
    END
  END d[97]
  PIN d[98]
    DIRECTION INPUT ;
    USE SIGNAL ;
    PORT
      LAYER M4 ;
        RECT  77.676 17.472 77.76 17.496 ;
    END
  END d[98]
  PIN d[99]
    DIRECTION INPUT ;
    USE SIGNAL ;
    PORT
      LAYER M4 ;
        RECT  77.676 17.568 77.76 17.592 ;
    END
  END d[99]
  PIN d[9]
    DIRECTION INPUT ;
    USE SIGNAL ;
    PORT
      LAYER M4 ;
        RECT  77.676 8.928 77.76 8.952 ;
    END
  END d[9]
  PIN fault
    DIRECTION OUTPUT ;
    USE SIGNAL ;
    PORT
      LAYER M4 ;
        RECT  0 44.736 0.084 44.76 ;
    END
  END fault
  PIN fclk
    DIRECTION INPUT ;
    USE SIGNAL ;
    PORT
      LAYER M4 ;
        RECT  77.676 44.832 77.76 44.856 ;
    END
  END fclk
  PIN q[0]
    DIRECTION OUTPUT ;
    USE SIGNAL ;
    PORT
      LAYER M4 ;
        RECT  0 7.872 0.084 7.896 ;
    END
  END q[0]
  PIN q[100]
    DIRECTION OUTPUT ;
    USE SIGNAL ;
    PORT
      LAYER M4 ;
        RECT  0 17.28 0.084 17.304 ;
    END
  END q[100]
  PIN q[101]
    DIRECTION OUTPUT ;
    USE SIGNAL ;
    PORT
      LAYER M4 ;
        RECT  0 17.376 0.084 17.4 ;
    END
  END q[101]
  PIN q[102]
    DIRECTION OUTPUT ;
    USE SIGNAL ;
    PORT
      LAYER M4 ;
        RECT  0 17.472 0.084 17.496 ;
    END
  END q[102]
  PIN q[103]
    DIRECTION OUTPUT ;
    USE SIGNAL ;
    PORT
      LAYER M4 ;
        RECT  0 17.568 0.084 17.592 ;
    END
  END q[103]
  PIN q[104]
    DIRECTION OUTPUT ;
    USE SIGNAL ;
    PORT
      LAYER M4 ;
        RECT  0 17.76 0.084 17.784 ;
    END
  END q[104]
  PIN q[105]
    DIRECTION OUTPUT ;
    USE SIGNAL ;
    PORT
      LAYER M4 ;
        RECT  0 17.664 0.084 17.688 ;
    END
  END q[105]
  PIN q[106]
    DIRECTION OUTPUT ;
    USE SIGNAL ;
    PORT
      LAYER M4 ;
        RECT  0 17.952 0.084 17.976 ;
    END
  END q[106]
  PIN q[107]
    DIRECTION OUTPUT ;
    USE SIGNAL ;
    PORT
      LAYER M4 ;
        RECT  0 17.856 0.084 17.88 ;
    END
  END q[107]
  PIN q[108]
    DIRECTION OUTPUT ;
    USE SIGNAL ;
    PORT
      LAYER M4 ;
        RECT  0 18.048 0.084 18.072 ;
    END
  END q[108]
  PIN q[109]
    DIRECTION OUTPUT ;
    USE SIGNAL ;
    PORT
      LAYER M4 ;
        RECT  0 18.144 0.084 18.168 ;
    END
  END q[109]
  PIN q[10]
    DIRECTION OUTPUT ;
    USE SIGNAL ;
    PORT
      LAYER M4 ;
        RECT  0 8.736 0.084 8.76 ;
    END
  END q[10]
  PIN q[110]
    DIRECTION OUTPUT ;
    USE SIGNAL ;
    PORT
      LAYER M4 ;
        RECT  0 18.24 0.084 18.264 ;
    END
  END q[110]
  PIN q[111]
    DIRECTION OUTPUT ;
    USE SIGNAL ;
    PORT
      LAYER M4 ;
        RECT  0 18.336 0.084 18.36 ;
    END
  END q[111]
  PIN q[112]
    DIRECTION OUTPUT ;
    USE SIGNAL ;
    PORT
      LAYER M4 ;
        RECT  0 18.432 0.084 18.456 ;
    END
  END q[112]
  PIN q[113]
    DIRECTION OUTPUT ;
    USE SIGNAL ;
    PORT
      LAYER M4 ;
        RECT  0 18.528 0.084 18.552 ;
    END
  END q[113]
  PIN q[114]
    DIRECTION OUTPUT ;
    USE SIGNAL ;
    PORT
      LAYER M4 ;
        RECT  0 18.624 0.084 18.648 ;
    END
  END q[114]
  PIN q[115]
    DIRECTION OUTPUT ;
    USE SIGNAL ;
    PORT
      LAYER M4 ;
        RECT  0 18.72 0.084 18.744 ;
    END
  END q[115]
  PIN q[116]
    DIRECTION OUTPUT ;
    USE SIGNAL ;
    PORT
      LAYER M4 ;
        RECT  0 18.816 0.084 18.84 ;
    END
  END q[116]
  PIN q[117]
    DIRECTION OUTPUT ;
    USE SIGNAL ;
    PORT
      LAYER M4 ;
        RECT  0 18.912 0.084 18.936 ;
    END
  END q[117]
  PIN q[118]
    DIRECTION OUTPUT ;
    USE SIGNAL ;
    PORT
      LAYER M4 ;
        RECT  0 19.008 0.084 19.032 ;
    END
  END q[118]
  PIN q[119]
    DIRECTION OUTPUT ;
    USE SIGNAL ;
    PORT
      LAYER M4 ;
        RECT  0 19.104 0.084 19.128 ;
    END
  END q[119]
  PIN q[11]
    DIRECTION OUTPUT ;
    USE SIGNAL ;
    PORT
      LAYER M4 ;
        RECT  0 8.64 0.084 8.664 ;
    END
  END q[11]
  PIN q[120]
    DIRECTION OUTPUT ;
    USE SIGNAL ;
    PORT
      LAYER M4 ;
        RECT  0 19.2 0.084 19.224 ;
    END
  END q[120]
  PIN q[121]
    DIRECTION OUTPUT ;
    USE SIGNAL ;
    PORT
      LAYER M4 ;
        RECT  0 19.296 0.084 19.32 ;
    END
  END q[121]
  PIN q[122]
    DIRECTION OUTPUT ;
    USE SIGNAL ;
    PORT
      LAYER M4 ;
        RECT  0 19.392 0.084 19.416 ;
    END
  END q[122]
  PIN q[123]
    DIRECTION OUTPUT ;
    USE SIGNAL ;
    PORT
      LAYER M4 ;
        RECT  0 19.488 0.084 19.512 ;
    END
  END q[123]
  PIN q[124]
    DIRECTION OUTPUT ;
    USE SIGNAL ;
    PORT
      LAYER M4 ;
        RECT  0 19.776 0.084 19.8 ;
    END
  END q[124]
  PIN q[125]
    DIRECTION OUTPUT ;
    USE SIGNAL ;
    PORT
      LAYER M4 ;
        RECT  0 19.584 0.084 19.608 ;
    END
  END q[125]
  PIN q[126]
    DIRECTION OUTPUT ;
    USE SIGNAL ;
    PORT
      LAYER M4 ;
        RECT  0 19.872 0.084 19.896 ;
    END
  END q[126]
  PIN q[127]
    DIRECTION OUTPUT ;
    USE SIGNAL ;
    PORT
      LAYER M4 ;
        RECT  0 19.68 0.084 19.704 ;
    END
  END q[127]
  PIN q[128]
    DIRECTION OUTPUT ;
    USE SIGNAL ;
    PORT
      LAYER M4 ;
        RECT  0 19.968 0.084 19.992 ;
    END
  END q[128]
  PIN q[129]
    DIRECTION OUTPUT ;
    USE SIGNAL ;
    PORT
      LAYER M4 ;
        RECT  0 20.064 0.084 20.088 ;
    END
  END q[129]
  PIN q[12]
    DIRECTION OUTPUT ;
    USE SIGNAL ;
    PORT
      LAYER M4 ;
        RECT  0 8.832 0.084 8.856 ;
    END
  END q[12]
  PIN q[130]
    DIRECTION OUTPUT ;
    USE SIGNAL ;
    PORT
      LAYER M4 ;
        RECT  0 20.16 0.084 20.184 ;
    END
  END q[130]
  PIN q[131]
    DIRECTION OUTPUT ;
    USE SIGNAL ;
    PORT
      LAYER M4 ;
        RECT  0 20.256 0.084 20.28 ;
    END
  END q[131]
  PIN q[132]
    DIRECTION OUTPUT ;
    USE SIGNAL ;
    PORT
      LAYER M4 ;
        RECT  0 20.352 0.084 20.376 ;
    END
  END q[132]
  PIN q[133]
    DIRECTION OUTPUT ;
    USE SIGNAL ;
    PORT
      LAYER M4 ;
        RECT  0 20.448 0.084 20.472 ;
    END
  END q[133]
  PIN q[134]
    DIRECTION OUTPUT ;
    USE SIGNAL ;
    PORT
      LAYER M4 ;
        RECT  0 20.544 0.084 20.568 ;
    END
  END q[134]
  PIN q[135]
    DIRECTION OUTPUT ;
    USE SIGNAL ;
    PORT
      LAYER M4 ;
        RECT  0 20.64 0.084 20.664 ;
    END
  END q[135]
  PIN q[136]
    DIRECTION OUTPUT ;
    USE SIGNAL ;
    PORT
      LAYER M4 ;
        RECT  0 20.736 0.084 20.76 ;
    END
  END q[136]
  PIN q[137]
    DIRECTION OUTPUT ;
    USE SIGNAL ;
    PORT
      LAYER M4 ;
        RECT  0 20.832 0.084 20.856 ;
    END
  END q[137]
  PIN q[138]
    DIRECTION OUTPUT ;
    USE SIGNAL ;
    PORT
      LAYER M4 ;
        RECT  0 20.928 0.084 20.952 ;
    END
  END q[138]
  PIN q[139]
    DIRECTION OUTPUT ;
    USE SIGNAL ;
    PORT
      LAYER M4 ;
        RECT  0 21.024 0.084 21.048 ;
    END
  END q[139]
  PIN q[13]
    DIRECTION OUTPUT ;
    USE SIGNAL ;
    PORT
      LAYER M4 ;
        RECT  0 8.928 0.084 8.952 ;
    END
  END q[13]
  PIN q[140]
    DIRECTION OUTPUT ;
    USE SIGNAL ;
    PORT
      LAYER M4 ;
        RECT  0 21.12 0.084 21.144 ;
    END
  END q[140]
  PIN q[141]
    DIRECTION OUTPUT ;
    USE SIGNAL ;
    PORT
      LAYER M4 ;
        RECT  0 21.216 0.084 21.24 ;
    END
  END q[141]
  PIN q[142]
    DIRECTION OUTPUT ;
    USE SIGNAL ;
    PORT
      LAYER M4 ;
        RECT  0 21.312 0.084 21.336 ;
    END
  END q[142]
  PIN q[143]
    DIRECTION OUTPUT ;
    USE SIGNAL ;
    PORT
      LAYER M4 ;
        RECT  0 21.408 0.084 21.432 ;
    END
  END q[143]
  PIN q[144]
    DIRECTION OUTPUT ;
    USE SIGNAL ;
    PORT
      LAYER M4 ;
        RECT  0 21.504 0.084 21.528 ;
    END
  END q[144]
  PIN q[145]
    DIRECTION OUTPUT ;
    USE SIGNAL ;
    PORT
      LAYER M4 ;
        RECT  0 21.6 0.084 21.624 ;
    END
  END q[145]
  PIN q[146]
    DIRECTION OUTPUT ;
    USE SIGNAL ;
    PORT
      LAYER M4 ;
        RECT  0 21.792 0.084 21.816 ;
    END
  END q[146]
  PIN q[147]
    DIRECTION OUTPUT ;
    USE SIGNAL ;
    PORT
      LAYER M4 ;
        RECT  0 21.696 0.084 21.72 ;
    END
  END q[147]
  PIN q[148]
    DIRECTION OUTPUT ;
    USE SIGNAL ;
    PORT
      LAYER M4 ;
        RECT  0 21.888 0.084 21.912 ;
    END
  END q[148]
  PIN q[149]
    DIRECTION OUTPUT ;
    USE SIGNAL ;
    PORT
      LAYER M4 ;
        RECT  0 21.984 0.084 22.008 ;
    END
  END q[149]
  PIN q[14]
    DIRECTION OUTPUT ;
    USE SIGNAL ;
    PORT
      LAYER M4 ;
        RECT  0 9.12 0.084 9.144 ;
    END
  END q[14]
  PIN q[150]
    DIRECTION OUTPUT ;
    USE SIGNAL ;
    PORT
      LAYER M4 ;
        RECT  0 22.08 0.084 22.104 ;
    END
  END q[150]
  PIN q[151]
    DIRECTION OUTPUT ;
    USE SIGNAL ;
    PORT
      LAYER M4 ;
        RECT  0 22.176 0.084 22.2 ;
    END
  END q[151]
  PIN q[152]
    DIRECTION OUTPUT ;
    USE SIGNAL ;
    PORT
      LAYER M4 ;
        RECT  0 22.272 0.084 22.296 ;
    END
  END q[152]
  PIN q[153]
    DIRECTION OUTPUT ;
    USE SIGNAL ;
    PORT
      LAYER M4 ;
        RECT  0 22.368 0.084 22.392 ;
    END
  END q[153]
  PIN q[154]
    DIRECTION OUTPUT ;
    USE SIGNAL ;
    PORT
      LAYER M4 ;
        RECT  0 22.464 0.084 22.488 ;
    END
  END q[154]
  PIN q[155]
    DIRECTION OUTPUT ;
    USE SIGNAL ;
    PORT
      LAYER M4 ;
        RECT  0 22.56 0.084 22.584 ;
    END
  END q[155]
  PIN q[156]
    DIRECTION OUTPUT ;
    USE SIGNAL ;
    PORT
      LAYER M4 ;
        RECT  0 22.656 0.084 22.68 ;
    END
  END q[156]
  PIN q[157]
    DIRECTION OUTPUT ;
    USE SIGNAL ;
    PORT
      LAYER M4 ;
        RECT  0 22.752 0.084 22.776 ;
    END
  END q[157]
  PIN q[158]
    DIRECTION OUTPUT ;
    USE SIGNAL ;
    PORT
      LAYER M4 ;
        RECT  0 22.848 0.084 22.872 ;
    END
  END q[158]
  PIN q[159]
    DIRECTION OUTPUT ;
    USE SIGNAL ;
    PORT
      LAYER M4 ;
        RECT  0 22.944 0.084 22.968 ;
    END
  END q[159]
  PIN q[15]
    DIRECTION OUTPUT ;
    USE SIGNAL ;
    PORT
      LAYER M4 ;
        RECT  0 9.024 0.084 9.048 ;
    END
  END q[15]
  PIN q[160]
    DIRECTION OUTPUT ;
    USE SIGNAL ;
    PORT
      LAYER M4 ;
        RECT  0 23.04 0.084 23.064 ;
    END
  END q[160]
  PIN q[161]
    DIRECTION OUTPUT ;
    USE SIGNAL ;
    PORT
      LAYER M4 ;
        RECT  0 23.136 0.084 23.16 ;
    END
  END q[161]
  PIN q[162]
    DIRECTION OUTPUT ;
    USE SIGNAL ;
    PORT
      LAYER M4 ;
        RECT  0 23.232 0.084 23.256 ;
    END
  END q[162]
  PIN q[163]
    DIRECTION OUTPUT ;
    USE SIGNAL ;
    PORT
      LAYER M4 ;
        RECT  0 23.328 0.084 23.352 ;
    END
  END q[163]
  PIN q[164]
    DIRECTION OUTPUT ;
    USE SIGNAL ;
    PORT
      LAYER M4 ;
        RECT  0 23.424 0.084 23.448 ;
    END
  END q[164]
  PIN q[165]
    DIRECTION OUTPUT ;
    USE SIGNAL ;
    PORT
      LAYER M4 ;
        RECT  0 23.52 0.084 23.544 ;
    END
  END q[165]
  PIN q[166]
    DIRECTION OUTPUT ;
    USE SIGNAL ;
    PORT
      LAYER M4 ;
        RECT  0 23.712 0.084 23.736 ;
    END
  END q[166]
  PIN q[167]
    DIRECTION OUTPUT ;
    USE SIGNAL ;
    PORT
      LAYER M4 ;
        RECT  0 23.616 0.084 23.64 ;
    END
  END q[167]
  PIN q[168]
    DIRECTION OUTPUT ;
    USE SIGNAL ;
    PORT
      LAYER M4 ;
        RECT  0 23.904 0.084 23.928 ;
    END
  END q[168]
  PIN q[169]
    DIRECTION OUTPUT ;
    USE SIGNAL ;
    PORT
      LAYER M4 ;
        RECT  0 23.808 0.084 23.832 ;
    END
  END q[169]
  PIN q[16]
    DIRECTION OUTPUT ;
    USE SIGNAL ;
    PORT
      LAYER M4 ;
        RECT  0 9.216 0.084 9.24 ;
    END
  END q[16]
  PIN q[170]
    DIRECTION OUTPUT ;
    USE SIGNAL ;
    PORT
      LAYER M4 ;
        RECT  0 24 0.084 24.024 ;
    END
  END q[170]
  PIN q[171]
    DIRECTION OUTPUT ;
    USE SIGNAL ;
    PORT
      LAYER M4 ;
        RECT  0 24.096 0.084 24.12 ;
    END
  END q[171]
  PIN q[172]
    DIRECTION OUTPUT ;
    USE SIGNAL ;
    PORT
      LAYER M4 ;
        RECT  0 24.192 0.084 24.216 ;
    END
  END q[172]
  PIN q[173]
    DIRECTION OUTPUT ;
    USE SIGNAL ;
    PORT
      LAYER M4 ;
        RECT  0 24.288 0.084 24.312 ;
    END
  END q[173]
  PIN q[174]
    DIRECTION OUTPUT ;
    USE SIGNAL ;
    PORT
      LAYER M4 ;
        RECT  0 24.384 0.084 24.408 ;
    END
  END q[174]
  PIN q[175]
    DIRECTION OUTPUT ;
    USE SIGNAL ;
    PORT
      LAYER M4 ;
        RECT  0 24.48 0.084 24.504 ;
    END
  END q[175]
  PIN q[176]
    DIRECTION OUTPUT ;
    USE SIGNAL ;
    PORT
      LAYER M4 ;
        RECT  0 24.576 0.084 24.6 ;
    END
  END q[176]
  PIN q[177]
    DIRECTION OUTPUT ;
    USE SIGNAL ;
    PORT
      LAYER M4 ;
        RECT  0 24.672 0.084 24.696 ;
    END
  END q[177]
  PIN q[178]
    DIRECTION OUTPUT ;
    USE SIGNAL ;
    PORT
      LAYER M4 ;
        RECT  0 24.768 0.084 24.792 ;
    END
  END q[178]
  PIN q[179]
    DIRECTION OUTPUT ;
    USE SIGNAL ;
    PORT
      LAYER M4 ;
        RECT  0 24.864 0.084 24.888 ;
    END
  END q[179]
  PIN q[17]
    DIRECTION OUTPUT ;
    USE SIGNAL ;
    PORT
      LAYER M4 ;
        RECT  0 9.312 0.084 9.336 ;
    END
  END q[17]
  PIN q[180]
    DIRECTION OUTPUT ;
    USE SIGNAL ;
    PORT
      LAYER M4 ;
        RECT  0 24.96 0.084 24.984 ;
    END
  END q[180]
  PIN q[181]
    DIRECTION OUTPUT ;
    USE SIGNAL ;
    PORT
      LAYER M4 ;
        RECT  0 25.056 0.084 25.08 ;
    END
  END q[181]
  PIN q[182]
    DIRECTION OUTPUT ;
    USE SIGNAL ;
    PORT
      LAYER M4 ;
        RECT  0 25.152 0.084 25.176 ;
    END
  END q[182]
  PIN q[183]
    DIRECTION OUTPUT ;
    USE SIGNAL ;
    PORT
      LAYER M4 ;
        RECT  0 25.248 0.084 25.272 ;
    END
  END q[183]
  PIN q[184]
    DIRECTION OUTPUT ;
    USE SIGNAL ;
    PORT
      LAYER M4 ;
        RECT  0 25.344 0.084 25.368 ;
    END
  END q[184]
  PIN q[185]
    DIRECTION OUTPUT ;
    USE SIGNAL ;
    PORT
      LAYER M4 ;
        RECT  0 25.536 0.084 25.56 ;
    END
  END q[185]
  PIN q[186]
    DIRECTION OUTPUT ;
    USE SIGNAL ;
    PORT
      LAYER M4 ;
        RECT  0 25.44 0.084 25.464 ;
    END
  END q[186]
  PIN q[187]
    DIRECTION OUTPUT ;
    USE SIGNAL ;
    PORT
      LAYER M4 ;
        RECT  0 25.632 0.084 25.656 ;
    END
  END q[187]
  PIN q[188]
    DIRECTION OUTPUT ;
    USE SIGNAL ;
    PORT
      LAYER M4 ;
        RECT  0 25.824 0.084 25.848 ;
    END
  END q[188]
  PIN q[189]
    DIRECTION OUTPUT ;
    USE SIGNAL ;
    PORT
      LAYER M4 ;
        RECT  0 25.728 0.084 25.752 ;
    END
  END q[189]
  PIN q[18]
    DIRECTION OUTPUT ;
    USE SIGNAL ;
    PORT
      LAYER M4 ;
        RECT  0 9.408 0.084 9.432 ;
    END
  END q[18]
  PIN q[190]
    DIRECTION OUTPUT ;
    USE SIGNAL ;
    PORT
      LAYER M4 ;
        RECT  0 25.92 0.084 25.944 ;
    END
  END q[190]
  PIN q[191]
    DIRECTION OUTPUT ;
    USE SIGNAL ;
    PORT
      LAYER M4 ;
        RECT  0 26.016 0.084 26.04 ;
    END
  END q[191]
  PIN q[192]
    DIRECTION OUTPUT ;
    USE SIGNAL ;
    PORT
      LAYER M4 ;
        RECT  0 26.112 0.084 26.136 ;
    END
  END q[192]
  PIN q[193]
    DIRECTION OUTPUT ;
    USE SIGNAL ;
    PORT
      LAYER M4 ;
        RECT  0 26.208 0.084 26.232 ;
    END
  END q[193]
  PIN q[194]
    DIRECTION OUTPUT ;
    USE SIGNAL ;
    PORT
      LAYER M4 ;
        RECT  0 26.304 0.084 26.328 ;
    END
  END q[194]
  PIN q[195]
    DIRECTION OUTPUT ;
    USE SIGNAL ;
    PORT
      LAYER M4 ;
        RECT  0 26.4 0.084 26.424 ;
    END
  END q[195]
  PIN q[196]
    DIRECTION OUTPUT ;
    USE SIGNAL ;
    PORT
      LAYER M4 ;
        RECT  0 26.496 0.084 26.52 ;
    END
  END q[196]
  PIN q[197]
    DIRECTION OUTPUT ;
    USE SIGNAL ;
    PORT
      LAYER M4 ;
        RECT  0 26.592 0.084 26.616 ;
    END
  END q[197]
  PIN q[198]
    DIRECTION OUTPUT ;
    USE SIGNAL ;
    PORT
      LAYER M4 ;
        RECT  0 26.688 0.084 26.712 ;
    END
  END q[198]
  PIN q[199]
    DIRECTION OUTPUT ;
    USE SIGNAL ;
    PORT
      LAYER M4 ;
        RECT  0 26.784 0.084 26.808 ;
    END
  END q[199]
  PIN q[19]
    DIRECTION OUTPUT ;
    USE SIGNAL ;
    PORT
      LAYER M4 ;
        RECT  0 9.504 0.084 9.528 ;
    END
  END q[19]
  PIN q[1]
    DIRECTION OUTPUT ;
    USE SIGNAL ;
    PORT
      LAYER M4 ;
        RECT  0 7.68 0.084 7.704 ;
    END
  END q[1]
  PIN q[200]
    DIRECTION OUTPUT ;
    USE SIGNAL ;
    PORT
      LAYER M4 ;
        RECT  0 26.88 0.084 26.904 ;
    END
  END q[200]
  PIN q[201]
    DIRECTION OUTPUT ;
    USE SIGNAL ;
    PORT
      LAYER M4 ;
        RECT  0 26.976 0.084 27 ;
    END
  END q[201]
  PIN q[202]
    DIRECTION OUTPUT ;
    USE SIGNAL ;
    PORT
      LAYER M4 ;
        RECT  0 27.072 0.084 27.096 ;
    END
  END q[202]
  PIN q[203]
    DIRECTION OUTPUT ;
    USE SIGNAL ;
    PORT
      LAYER M4 ;
        RECT  0 27.168 0.084 27.192 ;
    END
  END q[203]
  PIN q[204]
    DIRECTION OUTPUT ;
    USE SIGNAL ;
    PORT
      LAYER M4 ;
        RECT  0 27.264 0.084 27.288 ;
    END
  END q[204]
  PIN q[205]
    DIRECTION OUTPUT ;
    USE SIGNAL ;
    PORT
      LAYER M4 ;
        RECT  0 27.36 0.084 27.384 ;
    END
  END q[205]
  PIN q[206]
    DIRECTION OUTPUT ;
    USE SIGNAL ;
    PORT
      LAYER M4 ;
        RECT  0 27.456 0.084 27.48 ;
    END
  END q[206]
  PIN q[207]
    DIRECTION OUTPUT ;
    USE SIGNAL ;
    PORT
      LAYER M4 ;
        RECT  0 27.552 0.084 27.576 ;
    END
  END q[207]
  PIN q[208]
    DIRECTION OUTPUT ;
    USE SIGNAL ;
    PORT
      LAYER M4 ;
        RECT  0 27.744 0.084 27.768 ;
    END
  END q[208]
  PIN q[209]
    DIRECTION OUTPUT ;
    USE SIGNAL ;
    PORT
      LAYER M4 ;
        RECT  0 27.648 0.084 27.672 ;
    END
  END q[209]
  PIN q[20]
    DIRECTION OUTPUT ;
    USE SIGNAL ;
    PORT
      LAYER M4 ;
        RECT  0 9.6 0.084 9.624 ;
    END
  END q[20]
  PIN q[210]
    DIRECTION OUTPUT ;
    USE SIGNAL ;
    PORT
      LAYER M4 ;
        RECT  0 27.84 0.084 27.864 ;
    END
  END q[210]
  PIN q[211]
    DIRECTION OUTPUT ;
    USE SIGNAL ;
    PORT
      LAYER M4 ;
        RECT  0 27.936 0.084 27.96 ;
    END
  END q[211]
  PIN q[212]
    DIRECTION OUTPUT ;
    USE SIGNAL ;
    PORT
      LAYER M4 ;
        RECT  0 28.032 0.084 28.056 ;
    END
  END q[212]
  PIN q[213]
    DIRECTION OUTPUT ;
    USE SIGNAL ;
    PORT
      LAYER M4 ;
        RECT  0 28.128 0.084 28.152 ;
    END
  END q[213]
  PIN q[214]
    DIRECTION OUTPUT ;
    USE SIGNAL ;
    PORT
      LAYER M4 ;
        RECT  0 28.224 0.084 28.248 ;
    END
  END q[214]
  PIN q[215]
    DIRECTION OUTPUT ;
    USE SIGNAL ;
    PORT
      LAYER M4 ;
        RECT  0 28.32 0.084 28.344 ;
    END
  END q[215]
  PIN q[216]
    DIRECTION OUTPUT ;
    USE SIGNAL ;
    PORT
      LAYER M4 ;
        RECT  0 28.416 0.084 28.44 ;
    END
  END q[216]
  PIN q[217]
    DIRECTION OUTPUT ;
    USE SIGNAL ;
    PORT
      LAYER M4 ;
        RECT  0 28.512 0.084 28.536 ;
    END
  END q[217]
  PIN q[218]
    DIRECTION OUTPUT ;
    USE SIGNAL ;
    PORT
      LAYER M4 ;
        RECT  0 28.608 0.084 28.632 ;
    END
  END q[218]
  PIN q[219]
    DIRECTION OUTPUT ;
    USE SIGNAL ;
    PORT
      LAYER M4 ;
        RECT  0 28.704 0.084 28.728 ;
    END
  END q[219]
  PIN q[21]
    DIRECTION OUTPUT ;
    USE SIGNAL ;
    PORT
      LAYER M4 ;
        RECT  0 9.696 0.084 9.72 ;
    END
  END q[21]
  PIN q[220]
    DIRECTION OUTPUT ;
    USE SIGNAL ;
    PORT
      LAYER M4 ;
        RECT  0 28.8 0.084 28.824 ;
    END
  END q[220]
  PIN q[221]
    DIRECTION OUTPUT ;
    USE SIGNAL ;
    PORT
      LAYER M4 ;
        RECT  0 28.896 0.084 28.92 ;
    END
  END q[221]
  PIN q[222]
    DIRECTION OUTPUT ;
    USE SIGNAL ;
    PORT
      LAYER M4 ;
        RECT  0 28.992 0.084 29.016 ;
    END
  END q[222]
  PIN q[223]
    DIRECTION OUTPUT ;
    USE SIGNAL ;
    PORT
      LAYER M4 ;
        RECT  0 29.088 0.084 29.112 ;
    END
  END q[223]
  PIN q[224]
    DIRECTION OUTPUT ;
    USE SIGNAL ;
    PORT
      LAYER M4 ;
        RECT  0 29.184 0.084 29.208 ;
    END
  END q[224]
  PIN q[225]
    DIRECTION OUTPUT ;
    USE SIGNAL ;
    PORT
      LAYER M4 ;
        RECT  0 29.28 0.084 29.304 ;
    END
  END q[225]
  PIN q[226]
    DIRECTION OUTPUT ;
    USE SIGNAL ;
    PORT
      LAYER M4 ;
        RECT  0 29.376 0.084 29.4 ;
    END
  END q[226]
  PIN q[227]
    DIRECTION OUTPUT ;
    USE SIGNAL ;
    PORT
      LAYER M4 ;
        RECT  0 29.472 0.084 29.496 ;
    END
  END q[227]
  PIN q[228]
    DIRECTION OUTPUT ;
    USE SIGNAL ;
    PORT
      LAYER M4 ;
        RECT  0 29.76 0.084 29.784 ;
    END
  END q[228]
  PIN q[229]
    DIRECTION OUTPUT ;
    USE SIGNAL ;
    PORT
      LAYER M4 ;
        RECT  0 29.568 0.084 29.592 ;
    END
  END q[229]
  PIN q[22]
    DIRECTION OUTPUT ;
    USE SIGNAL ;
    PORT
      LAYER M4 ;
        RECT  0 9.888 0.084 9.912 ;
    END
  END q[22]
  PIN q[230]
    DIRECTION OUTPUT ;
    USE SIGNAL ;
    PORT
      LAYER M4 ;
        RECT  0 29.856 0.084 29.88 ;
    END
  END q[230]
  PIN q[231]
    DIRECTION OUTPUT ;
    USE SIGNAL ;
    PORT
      LAYER M4 ;
        RECT  0 29.664 0.084 29.688 ;
    END
  END q[231]
  PIN q[232]
    DIRECTION OUTPUT ;
    USE SIGNAL ;
    PORT
      LAYER M4 ;
        RECT  0 29.952 0.084 29.976 ;
    END
  END q[232]
  PIN q[233]
    DIRECTION OUTPUT ;
    USE SIGNAL ;
    PORT
      LAYER M4 ;
        RECT  0 30.048 0.084 30.072 ;
    END
  END q[233]
  PIN q[234]
    DIRECTION OUTPUT ;
    USE SIGNAL ;
    PORT
      LAYER M4 ;
        RECT  0 30.144 0.084 30.168 ;
    END
  END q[234]
  PIN q[235]
    DIRECTION OUTPUT ;
    USE SIGNAL ;
    PORT
      LAYER M4 ;
        RECT  0 30.24 0.084 30.264 ;
    END
  END q[235]
  PIN q[236]
    DIRECTION OUTPUT ;
    USE SIGNAL ;
    PORT
      LAYER M4 ;
        RECT  0 30.336 0.084 30.36 ;
    END
  END q[236]
  PIN q[237]
    DIRECTION OUTPUT ;
    USE SIGNAL ;
    PORT
      LAYER M4 ;
        RECT  0 30.432 0.084 30.456 ;
    END
  END q[237]
  PIN q[238]
    DIRECTION OUTPUT ;
    USE SIGNAL ;
    PORT
      LAYER M4 ;
        RECT  0 30.528 0.084 30.552 ;
    END
  END q[238]
  PIN q[239]
    DIRECTION OUTPUT ;
    USE SIGNAL ;
    PORT
      LAYER M4 ;
        RECT  0 30.624 0.084 30.648 ;
    END
  END q[239]
  PIN q[23]
    DIRECTION OUTPUT ;
    USE SIGNAL ;
    PORT
      LAYER M4 ;
        RECT  0 9.792 0.084 9.816 ;
    END
  END q[23]
  PIN q[240]
    DIRECTION OUTPUT ;
    USE SIGNAL ;
    PORT
      LAYER M4 ;
        RECT  0 30.72 0.084 30.744 ;
    END
  END q[240]
  PIN q[241]
    DIRECTION OUTPUT ;
    USE SIGNAL ;
    PORT
      LAYER M4 ;
        RECT  0 30.816 0.084 30.84 ;
    END
  END q[241]
  PIN q[242]
    DIRECTION OUTPUT ;
    USE SIGNAL ;
    PORT
      LAYER M4 ;
        RECT  0 30.912 0.084 30.936 ;
    END
  END q[242]
  PIN q[243]
    DIRECTION OUTPUT ;
    USE SIGNAL ;
    PORT
      LAYER M4 ;
        RECT  0 31.008 0.084 31.032 ;
    END
  END q[243]
  PIN q[244]
    DIRECTION OUTPUT ;
    USE SIGNAL ;
    PORT
      LAYER M4 ;
        RECT  0 31.104 0.084 31.128 ;
    END
  END q[244]
  PIN q[245]
    DIRECTION OUTPUT ;
    USE SIGNAL ;
    PORT
      LAYER M4 ;
        RECT  0 31.2 0.084 31.224 ;
    END
  END q[245]
  PIN q[246]
    DIRECTION OUTPUT ;
    USE SIGNAL ;
    PORT
      LAYER M4 ;
        RECT  0 31.296 0.084 31.32 ;
    END
  END q[246]
  PIN q[247]
    DIRECTION OUTPUT ;
    USE SIGNAL ;
    PORT
      LAYER M4 ;
        RECT  0 31.488 0.084 31.512 ;
    END
  END q[247]
  PIN q[248]
    DIRECTION OUTPUT ;
    USE SIGNAL ;
    PORT
      LAYER M4 ;
        RECT  0 31.392 0.084 31.416 ;
    END
  END q[248]
  PIN q[249]
    DIRECTION OUTPUT ;
    USE SIGNAL ;
    PORT
      LAYER M4 ;
        RECT  0 31.584 0.084 31.608 ;
    END
  END q[249]
  PIN q[24]
    DIRECTION OUTPUT ;
    USE SIGNAL ;
    PORT
      LAYER M4 ;
        RECT  0 9.984 0.084 10.008 ;
    END
  END q[24]
  PIN q[250]
    DIRECTION OUTPUT ;
    USE SIGNAL ;
    PORT
      LAYER M4 ;
        RECT  0 31.776 0.084 31.8 ;
    END
  END q[250]
  PIN q[251]
    DIRECTION OUTPUT ;
    USE SIGNAL ;
    PORT
      LAYER M4 ;
        RECT  0 31.68 0.084 31.704 ;
    END
  END q[251]
  PIN q[252]
    DIRECTION OUTPUT ;
    USE SIGNAL ;
    PORT
      LAYER M4 ;
        RECT  0 31.872 0.084 31.896 ;
    END
  END q[252]
  PIN q[253]
    DIRECTION OUTPUT ;
    USE SIGNAL ;
    PORT
      LAYER M4 ;
        RECT  0 31.968 0.084 31.992 ;
    END
  END q[253]
  PIN q[254]
    DIRECTION OUTPUT ;
    USE SIGNAL ;
    PORT
      LAYER M4 ;
        RECT  0 32.064 0.084 32.088 ;
    END
  END q[254]
  PIN q[255]
    DIRECTION OUTPUT ;
    USE SIGNAL ;
    PORT
      LAYER M4 ;
        RECT  0 32.16 0.084 32.184 ;
    END
  END q[255]
  PIN q[256]
    DIRECTION OUTPUT ;
    USE SIGNAL ;
    PORT
      LAYER M4 ;
        RECT  0 32.256 0.084 32.28 ;
    END
  END q[256]
  PIN q[257]
    DIRECTION OUTPUT ;
    USE SIGNAL ;
    PORT
      LAYER M4 ;
        RECT  0 32.352 0.084 32.376 ;
    END
  END q[257]
  PIN q[258]
    DIRECTION OUTPUT ;
    USE SIGNAL ;
    PORT
      LAYER M4 ;
        RECT  0 32.448 0.084 32.472 ;
    END
  END q[258]
  PIN q[259]
    DIRECTION OUTPUT ;
    USE SIGNAL ;
    PORT
      LAYER M4 ;
        RECT  0 32.544 0.084 32.568 ;
    END
  END q[259]
  PIN q[25]
    DIRECTION OUTPUT ;
    USE SIGNAL ;
    PORT
      LAYER M4 ;
        RECT  0 10.08 0.084 10.104 ;
    END
  END q[25]
  PIN q[260]
    DIRECTION OUTPUT ;
    USE SIGNAL ;
    PORT
      LAYER M4 ;
        RECT  0 32.64 0.084 32.664 ;
    END
  END q[260]
  PIN q[261]
    DIRECTION OUTPUT ;
    USE SIGNAL ;
    PORT
      LAYER M4 ;
        RECT  0 32.736 0.084 32.76 ;
    END
  END q[261]
  PIN q[262]
    DIRECTION OUTPUT ;
    USE SIGNAL ;
    PORT
      LAYER M4 ;
        RECT  0 32.832 0.084 32.856 ;
    END
  END q[262]
  PIN q[263]
    DIRECTION OUTPUT ;
    USE SIGNAL ;
    PORT
      LAYER M4 ;
        RECT  0 32.928 0.084 32.952 ;
    END
  END q[263]
  PIN q[264]
    DIRECTION OUTPUT ;
    USE SIGNAL ;
    PORT
      LAYER M4 ;
        RECT  0 33.024 0.084 33.048 ;
    END
  END q[264]
  PIN q[265]
    DIRECTION OUTPUT ;
    USE SIGNAL ;
    PORT
      LAYER M4 ;
        RECT  0 33.12 0.084 33.144 ;
    END
  END q[265]
  PIN q[266]
    DIRECTION OUTPUT ;
    USE SIGNAL ;
    PORT
      LAYER M4 ;
        RECT  0 33.216 0.084 33.24 ;
    END
  END q[266]
  PIN q[267]
    DIRECTION OUTPUT ;
    USE SIGNAL ;
    PORT
      LAYER M4 ;
        RECT  0 33.312 0.084 33.336 ;
    END
  END q[267]
  PIN q[268]
    DIRECTION OUTPUT ;
    USE SIGNAL ;
    PORT
      LAYER M4 ;
        RECT  0 33.408 0.084 33.432 ;
    END
  END q[268]
  PIN q[269]
    DIRECTION OUTPUT ;
    USE SIGNAL ;
    PORT
      LAYER M4 ;
        RECT  0 33.504 0.084 33.528 ;
    END
  END q[269]
  PIN q[26]
    DIRECTION OUTPUT ;
    USE SIGNAL ;
    PORT
      LAYER M4 ;
        RECT  0 10.176 0.084 10.2 ;
    END
  END q[26]
  PIN q[270]
    DIRECTION OUTPUT ;
    USE SIGNAL ;
    PORT
      LAYER M4 ;
        RECT  0 33.696 0.084 33.72 ;
    END
  END q[270]
  PIN q[271]
    DIRECTION OUTPUT ;
    USE SIGNAL ;
    PORT
      LAYER M4 ;
        RECT  0 33.6 0.084 33.624 ;
    END
  END q[271]
  PIN q[272]
    DIRECTION OUTPUT ;
    USE SIGNAL ;
    PORT
      LAYER M4 ;
        RECT  0 33.792 0.084 33.816 ;
    END
  END q[272]
  PIN q[273]
    DIRECTION OUTPUT ;
    USE SIGNAL ;
    PORT
      LAYER M4 ;
        RECT  0 33.888 0.084 33.912 ;
    END
  END q[273]
  PIN q[274]
    DIRECTION OUTPUT ;
    USE SIGNAL ;
    PORT
      LAYER M4 ;
        RECT  0 33.984 0.084 34.008 ;
    END
  END q[274]
  PIN q[275]
    DIRECTION OUTPUT ;
    USE SIGNAL ;
    PORT
      LAYER M4 ;
        RECT  0 34.08 0.084 34.104 ;
    END
  END q[275]
  PIN q[276]
    DIRECTION OUTPUT ;
    USE SIGNAL ;
    PORT
      LAYER M4 ;
        RECT  0 34.176 0.084 34.2 ;
    END
  END q[276]
  PIN q[277]
    DIRECTION OUTPUT ;
    USE SIGNAL ;
    PORT
      LAYER M4 ;
        RECT  0 34.272 0.084 34.296 ;
    END
  END q[277]
  PIN q[278]
    DIRECTION OUTPUT ;
    USE SIGNAL ;
    PORT
      LAYER M4 ;
        RECT  0 34.368 0.084 34.392 ;
    END
  END q[278]
  PIN q[279]
    DIRECTION OUTPUT ;
    USE SIGNAL ;
    PORT
      LAYER M4 ;
        RECT  0 34.464 0.084 34.488 ;
    END
  END q[279]
  PIN q[27]
    DIRECTION OUTPUT ;
    USE SIGNAL ;
    PORT
      LAYER M4 ;
        RECT  0 10.272 0.084 10.296 ;
    END
  END q[27]
  PIN q[280]
    DIRECTION OUTPUT ;
    USE SIGNAL ;
    PORT
      LAYER M4 ;
        RECT  0 34.56 0.084 34.584 ;
    END
  END q[280]
  PIN q[281]
    DIRECTION OUTPUT ;
    USE SIGNAL ;
    PORT
      LAYER M4 ;
        RECT  0 34.656 0.084 34.68 ;
    END
  END q[281]
  PIN q[282]
    DIRECTION OUTPUT ;
    USE SIGNAL ;
    PORT
      LAYER M4 ;
        RECT  0 34.752 0.084 34.776 ;
    END
  END q[282]
  PIN q[283]
    DIRECTION OUTPUT ;
    USE SIGNAL ;
    PORT
      LAYER M4 ;
        RECT  0 34.848 0.084 34.872 ;
    END
  END q[283]
  PIN q[284]
    DIRECTION OUTPUT ;
    USE SIGNAL ;
    PORT
      LAYER M4 ;
        RECT  0 34.944 0.084 34.968 ;
    END
  END q[284]
  PIN q[285]
    DIRECTION OUTPUT ;
    USE SIGNAL ;
    PORT
      LAYER M4 ;
        RECT  0 35.04 0.084 35.064 ;
    END
  END q[285]
  PIN q[286]
    DIRECTION OUTPUT ;
    USE SIGNAL ;
    PORT
      LAYER M4 ;
        RECT  0 35.136 0.084 35.16 ;
    END
  END q[286]
  PIN q[287]
    DIRECTION OUTPUT ;
    USE SIGNAL ;
    PORT
      LAYER M4 ;
        RECT  0 35.232 0.084 35.256 ;
    END
  END q[287]
  PIN q[288]
    DIRECTION OUTPUT ;
    USE SIGNAL ;
    PORT
      LAYER M4 ;
        RECT  0 35.328 0.084 35.352 ;
    END
  END q[288]
  PIN q[289]
    DIRECTION OUTPUT ;
    USE SIGNAL ;
    PORT
      LAYER M4 ;
        RECT  0 35.424 0.084 35.448 ;
    END
  END q[289]
  PIN q[28]
    DIRECTION OUTPUT ;
    USE SIGNAL ;
    PORT
      LAYER M4 ;
        RECT  0 10.368 0.084 10.392 ;
    END
  END q[28]
  PIN q[290]
    DIRECTION OUTPUT ;
    USE SIGNAL ;
    PORT
      LAYER M4 ;
        RECT  0 35.616 0.084 35.64 ;
    END
  END q[290]
  PIN q[291]
    DIRECTION OUTPUT ;
    USE SIGNAL ;
    PORT
      LAYER M4 ;
        RECT  0 35.52 0.084 35.544 ;
    END
  END q[291]
  PIN q[292]
    DIRECTION OUTPUT ;
    USE SIGNAL ;
    PORT
      LAYER M4 ;
        RECT  0 35.808 0.084 35.832 ;
    END
  END q[292]
  PIN q[293]
    DIRECTION OUTPUT ;
    USE SIGNAL ;
    PORT
      LAYER M4 ;
        RECT  0 35.712 0.084 35.736 ;
    END
  END q[293]
  PIN q[294]
    DIRECTION OUTPUT ;
    USE SIGNAL ;
    PORT
      LAYER M4 ;
        RECT  0 35.904 0.084 35.928 ;
    END
  END q[294]
  PIN q[295]
    DIRECTION OUTPUT ;
    USE SIGNAL ;
    PORT
      LAYER M4 ;
        RECT  0 36 0.084 36.024 ;
    END
  END q[295]
  PIN q[296]
    DIRECTION OUTPUT ;
    USE SIGNAL ;
    PORT
      LAYER M4 ;
        RECT  0 36.096 0.084 36.12 ;
    END
  END q[296]
  PIN q[297]
    DIRECTION OUTPUT ;
    USE SIGNAL ;
    PORT
      LAYER M4 ;
        RECT  0 36.192 0.084 36.216 ;
    END
  END q[297]
  PIN q[298]
    DIRECTION OUTPUT ;
    USE SIGNAL ;
    PORT
      LAYER M4 ;
        RECT  0 36.288 0.084 36.312 ;
    END
  END q[298]
  PIN q[299]
    DIRECTION OUTPUT ;
    USE SIGNAL ;
    PORT
      LAYER M4 ;
        RECT  0 36.384 0.084 36.408 ;
    END
  END q[299]
  PIN q[29]
    DIRECTION OUTPUT ;
    USE SIGNAL ;
    PORT
      LAYER M4 ;
        RECT  0 10.464 0.084 10.488 ;
    END
  END q[29]
  PIN q[2]
    DIRECTION OUTPUT ;
    USE SIGNAL ;
    PORT
      LAYER M4 ;
        RECT  0 7.968 0.084 7.992 ;
    END
  END q[2]
  PIN q[300]
    DIRECTION OUTPUT ;
    USE SIGNAL ;
    PORT
      LAYER M4 ;
        RECT  0 36.48 0.084 36.504 ;
    END
  END q[300]
  PIN q[301]
    DIRECTION OUTPUT ;
    USE SIGNAL ;
    PORT
      LAYER M4 ;
        RECT  0 36.576 0.084 36.6 ;
    END
  END q[301]
  PIN q[302]
    DIRECTION OUTPUT ;
    USE SIGNAL ;
    PORT
      LAYER M4 ;
        RECT  0 36.672 0.084 36.696 ;
    END
  END q[302]
  PIN q[303]
    DIRECTION OUTPUT ;
    USE SIGNAL ;
    PORT
      LAYER M4 ;
        RECT  0 36.768 0.084 36.792 ;
    END
  END q[303]
  PIN q[304]
    DIRECTION OUTPUT ;
    USE SIGNAL ;
    PORT
      LAYER M4 ;
        RECT  0 36.864 0.084 36.888 ;
    END
  END q[304]
  PIN q[305]
    DIRECTION OUTPUT ;
    USE SIGNAL ;
    PORT
      LAYER M4 ;
        RECT  0 36.96 0.084 36.984 ;
    END
  END q[305]
  PIN q[306]
    DIRECTION OUTPUT ;
    USE SIGNAL ;
    PORT
      LAYER M4 ;
        RECT  0 37.056 0.084 37.08 ;
    END
  END q[306]
  PIN q[307]
    DIRECTION OUTPUT ;
    USE SIGNAL ;
    PORT
      LAYER M4 ;
        RECT  0 37.152 0.084 37.176 ;
    END
  END q[307]
  PIN q[308]
    DIRECTION OUTPUT ;
    USE SIGNAL ;
    PORT
      LAYER M4 ;
        RECT  0 37.248 0.084 37.272 ;
    END
  END q[308]
  PIN q[309]
    DIRECTION OUTPUT ;
    USE SIGNAL ;
    PORT
      LAYER M4 ;
        RECT  0 37.44 0.084 37.464 ;
    END
  END q[309]
  PIN q[30]
    DIRECTION OUTPUT ;
    USE SIGNAL ;
    PORT
      LAYER M4 ;
        RECT  0 10.56 0.084 10.584 ;
    END
  END q[30]
  PIN q[310]
    DIRECTION OUTPUT ;
    USE SIGNAL ;
    PORT
      LAYER M4 ;
        RECT  0 37.344 0.084 37.368 ;
    END
  END q[310]
  PIN q[311]
    DIRECTION OUTPUT ;
    USE SIGNAL ;
    PORT
      LAYER M4 ;
        RECT  0 37.536 0.084 37.56 ;
    END
  END q[311]
  PIN q[312]
    DIRECTION OUTPUT ;
    USE SIGNAL ;
    PORT
      LAYER M4 ;
        RECT  0 37.728 0.084 37.752 ;
    END
  END q[312]
  PIN q[313]
    DIRECTION OUTPUT ;
    USE SIGNAL ;
    PORT
      LAYER M4 ;
        RECT  0 37.632 0.084 37.656 ;
    END
  END q[313]
  PIN q[314]
    DIRECTION OUTPUT ;
    USE SIGNAL ;
    PORT
      LAYER M4 ;
        RECT  0 37.824 0.084 37.848 ;
    END
  END q[314]
  PIN q[315]
    DIRECTION OUTPUT ;
    USE SIGNAL ;
    PORT
      LAYER M4 ;
        RECT  0 37.92 0.084 37.944 ;
    END
  END q[315]
  PIN q[316]
    DIRECTION OUTPUT ;
    USE SIGNAL ;
    PORT
      LAYER M4 ;
        RECT  0 38.016 0.084 38.04 ;
    END
  END q[316]
  PIN q[317]
    DIRECTION OUTPUT ;
    USE SIGNAL ;
    PORT
      LAYER M4 ;
        RECT  0 38.112 0.084 38.136 ;
    END
  END q[317]
  PIN q[318]
    DIRECTION OUTPUT ;
    USE SIGNAL ;
    PORT
      LAYER M4 ;
        RECT  0 38.208 0.084 38.232 ;
    END
  END q[318]
  PIN q[319]
    DIRECTION OUTPUT ;
    USE SIGNAL ;
    PORT
      LAYER M4 ;
        RECT  0 38.304 0.084 38.328 ;
    END
  END q[319]
  PIN q[31]
    DIRECTION OUTPUT ;
    USE SIGNAL ;
    PORT
      LAYER M4 ;
        RECT  0 10.656 0.084 10.68 ;
    END
  END q[31]
  PIN q[320]
    DIRECTION OUTPUT ;
    USE SIGNAL ;
    PORT
      LAYER M4 ;
        RECT  0 38.4 0.084 38.424 ;
    END
  END q[320]
  PIN q[321]
    DIRECTION OUTPUT ;
    USE SIGNAL ;
    PORT
      LAYER M4 ;
        RECT  0 38.496 0.084 38.52 ;
    END
  END q[321]
  PIN q[322]
    DIRECTION OUTPUT ;
    USE SIGNAL ;
    PORT
      LAYER M4 ;
        RECT  0 38.592 0.084 38.616 ;
    END
  END q[322]
  PIN q[323]
    DIRECTION OUTPUT ;
    USE SIGNAL ;
    PORT
      LAYER M4 ;
        RECT  0 38.688 0.084 38.712 ;
    END
  END q[323]
  PIN q[324]
    DIRECTION OUTPUT ;
    USE SIGNAL ;
    PORT
      LAYER M4 ;
        RECT  0 38.784 0.084 38.808 ;
    END
  END q[324]
  PIN q[325]
    DIRECTION OUTPUT ;
    USE SIGNAL ;
    PORT
      LAYER M4 ;
        RECT  0 38.88 0.084 38.904 ;
    END
  END q[325]
  PIN q[326]
    DIRECTION OUTPUT ;
    USE SIGNAL ;
    PORT
      LAYER M4 ;
        RECT  0 38.976 0.084 39 ;
    END
  END q[326]
  PIN q[327]
    DIRECTION OUTPUT ;
    USE SIGNAL ;
    PORT
      LAYER M4 ;
        RECT  0 39.072 0.084 39.096 ;
    END
  END q[327]
  PIN q[328]
    DIRECTION OUTPUT ;
    USE SIGNAL ;
    PORT
      LAYER M4 ;
        RECT  0 39.168 0.084 39.192 ;
    END
  END q[328]
  PIN q[329]
    DIRECTION OUTPUT ;
    USE SIGNAL ;
    PORT
      LAYER M4 ;
        RECT  0 39.264 0.084 39.288 ;
    END
  END q[329]
  PIN q[32]
    DIRECTION OUTPUT ;
    USE SIGNAL ;
    PORT
      LAYER M4 ;
        RECT  0 10.752 0.084 10.776 ;
    END
  END q[32]
  PIN q[330]
    DIRECTION OUTPUT ;
    USE SIGNAL ;
    PORT
      LAYER M4 ;
        RECT  0 39.36 0.084 39.384 ;
    END
  END q[330]
  PIN q[331]
    DIRECTION OUTPUT ;
    USE SIGNAL ;
    PORT
      LAYER M4 ;
        RECT  0 39.456 0.084 39.48 ;
    END
  END q[331]
  PIN q[332]
    DIRECTION OUTPUT ;
    USE SIGNAL ;
    PORT
      LAYER M4 ;
        RECT  0 39.648 0.084 39.672 ;
    END
  END q[332]
  PIN q[333]
    DIRECTION OUTPUT ;
    USE SIGNAL ;
    PORT
      LAYER M4 ;
        RECT  0 39.552 0.084 39.576 ;
    END
  END q[333]
  PIN q[334]
    DIRECTION OUTPUT ;
    USE SIGNAL ;
    PORT
      LAYER M4 ;
        RECT  0 39.744 0.084 39.768 ;
    END
  END q[334]
  PIN q[335]
    DIRECTION OUTPUT ;
    USE SIGNAL ;
    PORT
      LAYER M4 ;
        RECT  0 39.84 0.084 39.864 ;
    END
  END q[335]
  PIN q[336]
    DIRECTION OUTPUT ;
    USE SIGNAL ;
    PORT
      LAYER M4 ;
        RECT  0 39.936 0.084 39.96 ;
    END
  END q[336]
  PIN q[337]
    DIRECTION OUTPUT ;
    USE SIGNAL ;
    PORT
      LAYER M4 ;
        RECT  0 40.032 0.084 40.056 ;
    END
  END q[337]
  PIN q[338]
    DIRECTION OUTPUT ;
    USE SIGNAL ;
    PORT
      LAYER M4 ;
        RECT  0 40.128 0.084 40.152 ;
    END
  END q[338]
  PIN q[339]
    DIRECTION OUTPUT ;
    USE SIGNAL ;
    PORT
      LAYER M4 ;
        RECT  0 40.224 0.084 40.248 ;
    END
  END q[339]
  PIN q[33]
    DIRECTION OUTPUT ;
    USE SIGNAL ;
    PORT
      LAYER M4 ;
        RECT  0 10.848 0.084 10.872 ;
    END
  END q[33]
  PIN q[340]
    DIRECTION OUTPUT ;
    USE SIGNAL ;
    PORT
      LAYER M4 ;
        RECT  0 40.32 0.084 40.344 ;
    END
  END q[340]
  PIN q[341]
    DIRECTION OUTPUT ;
    USE SIGNAL ;
    PORT
      LAYER M4 ;
        RECT  0 40.416 0.084 40.44 ;
    END
  END q[341]
  PIN q[342]
    DIRECTION OUTPUT ;
    USE SIGNAL ;
    PORT
      LAYER M4 ;
        RECT  0 40.512 0.084 40.536 ;
    END
  END q[342]
  PIN q[343]
    DIRECTION OUTPUT ;
    USE SIGNAL ;
    PORT
      LAYER M4 ;
        RECT  0 40.608 0.084 40.632 ;
    END
  END q[343]
  PIN q[344]
    DIRECTION OUTPUT ;
    USE SIGNAL ;
    PORT
      LAYER M4 ;
        RECT  0 40.704 0.084 40.728 ;
    END
  END q[344]
  PIN q[345]
    DIRECTION OUTPUT ;
    USE SIGNAL ;
    PORT
      LAYER M4 ;
        RECT  0 40.8 0.084 40.824 ;
    END
  END q[345]
  PIN q[346]
    DIRECTION OUTPUT ;
    USE SIGNAL ;
    PORT
      LAYER M4 ;
        RECT  0 40.896 0.084 40.92 ;
    END
  END q[346]
  PIN q[347]
    DIRECTION OUTPUT ;
    USE SIGNAL ;
    PORT
      LAYER M4 ;
        RECT  0 40.992 0.084 41.016 ;
    END
  END q[347]
  PIN q[348]
    DIRECTION OUTPUT ;
    USE SIGNAL ;
    PORT
      LAYER M4 ;
        RECT  0 41.088 0.084 41.112 ;
    END
  END q[348]
  PIN q[349]
    DIRECTION OUTPUT ;
    USE SIGNAL ;
    PORT
      LAYER M4 ;
        RECT  0 41.184 0.084 41.208 ;
    END
  END q[349]
  PIN q[34]
    DIRECTION OUTPUT ;
    USE SIGNAL ;
    PORT
      LAYER M4 ;
        RECT  0 11.04 0.084 11.064 ;
    END
  END q[34]
  PIN q[350]
    DIRECTION OUTPUT ;
    USE SIGNAL ;
    PORT
      LAYER M4 ;
        RECT  0 41.28 0.084 41.304 ;
    END
  END q[350]
  PIN q[351]
    DIRECTION OUTPUT ;
    USE SIGNAL ;
    PORT
      LAYER M4 ;
        RECT  0 41.472 0.084 41.496 ;
    END
  END q[351]
  PIN q[352]
    DIRECTION OUTPUT ;
    USE SIGNAL ;
    PORT
      LAYER M4 ;
        RECT  0 41.376 0.084 41.4 ;
    END
  END q[352]
  PIN q[353]
    DIRECTION OUTPUT ;
    USE SIGNAL ;
    PORT
      LAYER M4 ;
        RECT  0 41.568 0.084 41.592 ;
    END
  END q[353]
  PIN q[354]
    DIRECTION OUTPUT ;
    USE SIGNAL ;
    PORT
      LAYER M4 ;
        RECT  0 41.76 0.084 41.784 ;
    END
  END q[354]
  PIN q[355]
    DIRECTION OUTPUT ;
    USE SIGNAL ;
    PORT
      LAYER M4 ;
        RECT  0 41.664 0.084 41.688 ;
    END
  END q[355]
  PIN q[356]
    DIRECTION OUTPUT ;
    USE SIGNAL ;
    PORT
      LAYER M4 ;
        RECT  0 41.856 0.084 41.88 ;
    END
  END q[356]
  PIN q[357]
    DIRECTION OUTPUT ;
    USE SIGNAL ;
    PORT
      LAYER M4 ;
        RECT  0 41.952 0.084 41.976 ;
    END
  END q[357]
  PIN q[358]
    DIRECTION OUTPUT ;
    USE SIGNAL ;
    PORT
      LAYER M4 ;
        RECT  0 42.048 0.084 42.072 ;
    END
  END q[358]
  PIN q[359]
    DIRECTION OUTPUT ;
    USE SIGNAL ;
    PORT
      LAYER M4 ;
        RECT  0 42.144 0.084 42.168 ;
    END
  END q[359]
  PIN q[35]
    DIRECTION OUTPUT ;
    USE SIGNAL ;
    PORT
      LAYER M4 ;
        RECT  0 10.944 0.084 10.968 ;
    END
  END q[35]
  PIN q[360]
    DIRECTION OUTPUT ;
    USE SIGNAL ;
    PORT
      LAYER M4 ;
        RECT  0 42.24 0.084 42.264 ;
    END
  END q[360]
  PIN q[361]
    DIRECTION OUTPUT ;
    USE SIGNAL ;
    PORT
      LAYER M4 ;
        RECT  0 42.336 0.084 42.36 ;
    END
  END q[361]
  PIN q[362]
    DIRECTION OUTPUT ;
    USE SIGNAL ;
    PORT
      LAYER M4 ;
        RECT  0 42.432 0.084 42.456 ;
    END
  END q[362]
  PIN q[363]
    DIRECTION OUTPUT ;
    USE SIGNAL ;
    PORT
      LAYER M4 ;
        RECT  0 42.528 0.084 42.552 ;
    END
  END q[363]
  PIN q[364]
    DIRECTION OUTPUT ;
    USE SIGNAL ;
    PORT
      LAYER M4 ;
        RECT  0 42.624 0.084 42.648 ;
    END
  END q[364]
  PIN q[365]
    DIRECTION OUTPUT ;
    USE SIGNAL ;
    PORT
      LAYER M4 ;
        RECT  0 42.72 0.084 42.744 ;
    END
  END q[365]
  PIN q[366]
    DIRECTION OUTPUT ;
    USE SIGNAL ;
    PORT
      LAYER M4 ;
        RECT  0 42.816 0.084 42.84 ;
    END
  END q[366]
  PIN q[367]
    DIRECTION OUTPUT ;
    USE SIGNAL ;
    PORT
      LAYER M4 ;
        RECT  0 42.912 0.084 42.936 ;
    END
  END q[367]
  PIN q[368]
    DIRECTION OUTPUT ;
    USE SIGNAL ;
    PORT
      LAYER M4 ;
        RECT  0 43.008 0.084 43.032 ;
    END
  END q[368]
  PIN q[369]
    DIRECTION OUTPUT ;
    USE SIGNAL ;
    PORT
      LAYER M4 ;
        RECT  0 43.104 0.084 43.128 ;
    END
  END q[369]
  PIN q[36]
    DIRECTION OUTPUT ;
    USE SIGNAL ;
    PORT
      LAYER M4 ;
        RECT  0 11.136 0.084 11.16 ;
    END
  END q[36]
  PIN q[370]
    DIRECTION OUTPUT ;
    USE SIGNAL ;
    PORT
      LAYER M4 ;
        RECT  0 43.2 0.084 43.224 ;
    END
  END q[370]
  PIN q[371]
    DIRECTION OUTPUT ;
    USE SIGNAL ;
    PORT
      LAYER M4 ;
        RECT  0 43.392 0.084 43.416 ;
    END
  END q[371]
  PIN q[372]
    DIRECTION OUTPUT ;
    USE SIGNAL ;
    PORT
      LAYER M4 ;
        RECT  0 43.296 0.084 43.32 ;
    END
  END q[372]
  PIN q[373]
    DIRECTION OUTPUT ;
    USE SIGNAL ;
    PORT
      LAYER M4 ;
        RECT  0 43.488 0.084 43.512 ;
    END
  END q[373]
  PIN q[374]
    DIRECTION OUTPUT ;
    USE SIGNAL ;
    PORT
      LAYER M4 ;
        RECT  0 43.68 0.084 43.704 ;
    END
  END q[374]
  PIN q[375]
    DIRECTION OUTPUT ;
    USE SIGNAL ;
    PORT
      LAYER M4 ;
        RECT  0 43.584 0.084 43.608 ;
    END
  END q[375]
  PIN q[376]
    DIRECTION OUTPUT ;
    USE SIGNAL ;
    PORT
      LAYER M4 ;
        RECT  0 43.776 0.084 43.8 ;
    END
  END q[376]
  PIN q[377]
    DIRECTION OUTPUT ;
    USE SIGNAL ;
    PORT
      LAYER M4 ;
        RECT  0 43.872 0.084 43.896 ;
    END
  END q[377]
  PIN q[378]
    DIRECTION OUTPUT ;
    USE SIGNAL ;
    PORT
      LAYER M4 ;
        RECT  0 43.968 0.084 43.992 ;
    END
  END q[378]
  PIN q[379]
    DIRECTION OUTPUT ;
    USE SIGNAL ;
    PORT
      LAYER M4 ;
        RECT  0 44.064 0.084 44.088 ;
    END
  END q[379]
  PIN q[37]
    DIRECTION OUTPUT ;
    USE SIGNAL ;
    PORT
      LAYER M4 ;
        RECT  0 11.232 0.084 11.256 ;
    END
  END q[37]
  PIN q[380]
    DIRECTION OUTPUT ;
    USE SIGNAL ;
    PORT
      LAYER M4 ;
        RECT  0 44.16 0.084 44.184 ;
    END
  END q[380]
  PIN q[381]
    DIRECTION OUTPUT ;
    USE SIGNAL ;
    PORT
      LAYER M4 ;
        RECT  0 44.256 0.084 44.28 ;
    END
  END q[381]
  PIN q[382]
    DIRECTION OUTPUT ;
    USE SIGNAL ;
    PORT
      LAYER M4 ;
        RECT  0 44.352 0.084 44.376 ;
    END
  END q[382]
  PIN q[383]
    DIRECTION OUTPUT ;
    USE SIGNAL ;
    PORT
      LAYER M4 ;
        RECT  0 45.408 0.084 45.432 ;
    END
  END q[383]
  PIN q[384]
    DIRECTION OUTPUT ;
    USE SIGNAL ;
    PORT
      LAYER M4 ;
        RECT  0 45.504 0.084 45.528 ;
    END
  END q[384]
  PIN q[385]
    DIRECTION OUTPUT ;
    USE SIGNAL ;
    PORT
      LAYER M4 ;
        RECT  0 45.6 0.084 45.624 ;
    END
  END q[385]
  PIN q[386]
    DIRECTION OUTPUT ;
    USE SIGNAL ;
    PORT
      LAYER M4 ;
        RECT  0 45.696 0.084 45.72 ;
    END
  END q[386]
  PIN q[387]
    DIRECTION OUTPUT ;
    USE SIGNAL ;
    PORT
      LAYER M4 ;
        RECT  0 45.792 0.084 45.816 ;
    END
  END q[387]
  PIN q[388]
    DIRECTION OUTPUT ;
    USE SIGNAL ;
    PORT
      LAYER M4 ;
        RECT  0 45.888 0.084 45.912 ;
    END
  END q[388]
  PIN q[389]
    DIRECTION OUTPUT ;
    USE SIGNAL ;
    PORT
      LAYER M4 ;
        RECT  0 45.984 0.084 46.008 ;
    END
  END q[389]
  PIN q[38]
    DIRECTION OUTPUT ;
    USE SIGNAL ;
    PORT
      LAYER M4 ;
        RECT  0 11.328 0.084 11.352 ;
    END
  END q[38]
  PIN q[390]
    DIRECTION OUTPUT ;
    USE SIGNAL ;
    PORT
      LAYER M4 ;
        RECT  0 46.08 0.084 46.104 ;
    END
  END q[390]
  PIN q[391]
    DIRECTION OUTPUT ;
    USE SIGNAL ;
    PORT
      LAYER M4 ;
        RECT  0 46.176 0.084 46.2 ;
    END
  END q[391]
  PIN q[392]
    DIRECTION OUTPUT ;
    USE SIGNAL ;
    PORT
      LAYER M4 ;
        RECT  0 46.272 0.084 46.296 ;
    END
  END q[392]
  PIN q[393]
    DIRECTION OUTPUT ;
    USE SIGNAL ;
    PORT
      LAYER M4 ;
        RECT  0 46.464 0.084 46.488 ;
    END
  END q[393]
  PIN q[394]
    DIRECTION OUTPUT ;
    USE SIGNAL ;
    PORT
      LAYER M4 ;
        RECT  0 46.368 0.084 46.392 ;
    END
  END q[394]
  PIN q[395]
    DIRECTION OUTPUT ;
    USE SIGNAL ;
    PORT
      LAYER M4 ;
        RECT  0 46.56 0.084 46.584 ;
    END
  END q[395]
  PIN q[396]
    DIRECTION OUTPUT ;
    USE SIGNAL ;
    PORT
      LAYER M4 ;
        RECT  0 46.656 0.084 46.68 ;
    END
  END q[396]
  PIN q[397]
    DIRECTION OUTPUT ;
    USE SIGNAL ;
    PORT
      LAYER M4 ;
        RECT  0 46.752 0.084 46.776 ;
    END
  END q[397]
  PIN q[398]
    DIRECTION OUTPUT ;
    USE SIGNAL ;
    PORT
      LAYER M4 ;
        RECT  0 46.848 0.084 46.872 ;
    END
  END q[398]
  PIN q[399]
    DIRECTION OUTPUT ;
    USE SIGNAL ;
    PORT
      LAYER M4 ;
        RECT  0 46.944 0.084 46.968 ;
    END
  END q[399]
  PIN q[39]
    DIRECTION OUTPUT ;
    USE SIGNAL ;
    PORT
      LAYER M4 ;
        RECT  0 11.424 0.084 11.448 ;
    END
  END q[39]
  PIN q[3]
    DIRECTION OUTPUT ;
    USE SIGNAL ;
    PORT
      LAYER M4 ;
        RECT  0 7.776 0.084 7.8 ;
    END
  END q[3]
  PIN q[400]
    DIRECTION OUTPUT ;
    USE SIGNAL ;
    PORT
      LAYER M4 ;
        RECT  0 47.04 0.084 47.064 ;
    END
  END q[400]
  PIN q[401]
    DIRECTION OUTPUT ;
    USE SIGNAL ;
    PORT
      LAYER M4 ;
        RECT  0 47.136 0.084 47.16 ;
    END
  END q[401]
  PIN q[402]
    DIRECTION OUTPUT ;
    USE SIGNAL ;
    PORT
      LAYER M4 ;
        RECT  0 47.232 0.084 47.256 ;
    END
  END q[402]
  PIN q[403]
    DIRECTION OUTPUT ;
    USE SIGNAL ;
    PORT
      LAYER M4 ;
        RECT  0 47.328 0.084 47.352 ;
    END
  END q[403]
  PIN q[404]
    DIRECTION OUTPUT ;
    USE SIGNAL ;
    PORT
      LAYER M4 ;
        RECT  0 47.424 0.084 47.448 ;
    END
  END q[404]
  PIN q[405]
    DIRECTION OUTPUT ;
    USE SIGNAL ;
    PORT
      LAYER M4 ;
        RECT  0 47.52 0.084 47.544 ;
    END
  END q[405]
  PIN q[406]
    DIRECTION OUTPUT ;
    USE SIGNAL ;
    PORT
      LAYER M4 ;
        RECT  0 47.616 0.084 47.64 ;
    END
  END q[406]
  PIN q[407]
    DIRECTION OUTPUT ;
    USE SIGNAL ;
    PORT
      LAYER M4 ;
        RECT  0 47.712 0.084 47.736 ;
    END
  END q[407]
  PIN q[408]
    DIRECTION OUTPUT ;
    USE SIGNAL ;
    PORT
      LAYER M4 ;
        RECT  0 47.808 0.084 47.832 ;
    END
  END q[408]
  PIN q[409]
    DIRECTION OUTPUT ;
    USE SIGNAL ;
    PORT
      LAYER M4 ;
        RECT  0 47.904 0.084 47.928 ;
    END
  END q[409]
  PIN q[40]
    DIRECTION OUTPUT ;
    USE SIGNAL ;
    PORT
      LAYER M4 ;
        RECT  0 11.52 0.084 11.544 ;
    END
  END q[40]
  PIN q[410]
    DIRECTION OUTPUT ;
    USE SIGNAL ;
    PORT
      LAYER M4 ;
        RECT  0 48 0.084 48.024 ;
    END
  END q[410]
  PIN q[411]
    DIRECTION OUTPUT ;
    USE SIGNAL ;
    PORT
      LAYER M4 ;
        RECT  0 48.096 0.084 48.12 ;
    END
  END q[411]
  PIN q[412]
    DIRECTION OUTPUT ;
    USE SIGNAL ;
    PORT
      LAYER M4 ;
        RECT  0 48.192 0.084 48.216 ;
    END
  END q[412]
  PIN q[413]
    DIRECTION OUTPUT ;
    USE SIGNAL ;
    PORT
      LAYER M4 ;
        RECT  0 48.384 0.084 48.408 ;
    END
  END q[413]
  PIN q[414]
    DIRECTION OUTPUT ;
    USE SIGNAL ;
    PORT
      LAYER M4 ;
        RECT  0 48.288 0.084 48.312 ;
    END
  END q[414]
  PIN q[415]
    DIRECTION OUTPUT ;
    USE SIGNAL ;
    PORT
      LAYER M4 ;
        RECT  0 48.48 0.084 48.504 ;
    END
  END q[415]
  PIN q[416]
    DIRECTION OUTPUT ;
    USE SIGNAL ;
    PORT
      LAYER M4 ;
        RECT  0 48.672 0.084 48.696 ;
    END
  END q[416]
  PIN q[417]
    DIRECTION OUTPUT ;
    USE SIGNAL ;
    PORT
      LAYER M4 ;
        RECT  0 48.576 0.084 48.6 ;
    END
  END q[417]
  PIN q[418]
    DIRECTION OUTPUT ;
    USE SIGNAL ;
    PORT
      LAYER M4 ;
        RECT  0 48.768 0.084 48.792 ;
    END
  END q[418]
  PIN q[419]
    DIRECTION OUTPUT ;
    USE SIGNAL ;
    PORT
      LAYER M4 ;
        RECT  0 48.864 0.084 48.888 ;
    END
  END q[419]
  PIN q[41]
    DIRECTION OUTPUT ;
    USE SIGNAL ;
    PORT
      LAYER M4 ;
        RECT  0 11.616 0.084 11.64 ;
    END
  END q[41]
  PIN q[420]
    DIRECTION OUTPUT ;
    USE SIGNAL ;
    PORT
      LAYER M4 ;
        RECT  0 48.96 0.084 48.984 ;
    END
  END q[420]
  PIN q[421]
    DIRECTION OUTPUT ;
    USE SIGNAL ;
    PORT
      LAYER M4 ;
        RECT  0 49.056 0.084 49.08 ;
    END
  END q[421]
  PIN q[422]
    DIRECTION OUTPUT ;
    USE SIGNAL ;
    PORT
      LAYER M4 ;
        RECT  0 49.152 0.084 49.176 ;
    END
  END q[422]
  PIN q[423]
    DIRECTION OUTPUT ;
    USE SIGNAL ;
    PORT
      LAYER M4 ;
        RECT  0 49.248 0.084 49.272 ;
    END
  END q[423]
  PIN q[424]
    DIRECTION OUTPUT ;
    USE SIGNAL ;
    PORT
      LAYER M4 ;
        RECT  0 49.344 0.084 49.368 ;
    END
  END q[424]
  PIN q[425]
    DIRECTION OUTPUT ;
    USE SIGNAL ;
    PORT
      LAYER M4 ;
        RECT  0 49.44 0.084 49.464 ;
    END
  END q[425]
  PIN q[426]
    DIRECTION OUTPUT ;
    USE SIGNAL ;
    PORT
      LAYER M4 ;
        RECT  0 49.536 0.084 49.56 ;
    END
  END q[426]
  PIN q[427]
    DIRECTION OUTPUT ;
    USE SIGNAL ;
    PORT
      LAYER M4 ;
        RECT  0 49.632 0.084 49.656 ;
    END
  END q[427]
  PIN q[428]
    DIRECTION OUTPUT ;
    USE SIGNAL ;
    PORT
      LAYER M4 ;
        RECT  0 49.728 0.084 49.752 ;
    END
  END q[428]
  PIN q[429]
    DIRECTION OUTPUT ;
    USE SIGNAL ;
    PORT
      LAYER M4 ;
        RECT  0 49.824 0.084 49.848 ;
    END
  END q[429]
  PIN q[42]
    DIRECTION OUTPUT ;
    USE SIGNAL ;
    PORT
      LAYER M4 ;
        RECT  0 11.808 0.084 11.832 ;
    END
  END q[42]
  PIN q[430]
    DIRECTION OUTPUT ;
    USE SIGNAL ;
    PORT
      LAYER M4 ;
        RECT  0 49.92 0.084 49.944 ;
    END
  END q[430]
  PIN q[431]
    DIRECTION OUTPUT ;
    USE SIGNAL ;
    PORT
      LAYER M4 ;
        RECT  0 50.016 0.084 50.04 ;
    END
  END q[431]
  PIN q[432]
    DIRECTION OUTPUT ;
    USE SIGNAL ;
    PORT
      LAYER M4 ;
        RECT  0 50.112 0.084 50.136 ;
    END
  END q[432]
  PIN q[433]
    DIRECTION OUTPUT ;
    USE SIGNAL ;
    PORT
      LAYER M4 ;
        RECT  0 50.304 0.084 50.328 ;
    END
  END q[433]
  PIN q[434]
    DIRECTION OUTPUT ;
    USE SIGNAL ;
    PORT
      LAYER M4 ;
        RECT  0 50.208 0.084 50.232 ;
    END
  END q[434]
  PIN q[435]
    DIRECTION OUTPUT ;
    USE SIGNAL ;
    PORT
      LAYER M4 ;
        RECT  0 50.496 0.084 50.52 ;
    END
  END q[435]
  PIN q[436]
    DIRECTION OUTPUT ;
    USE SIGNAL ;
    PORT
      LAYER M4 ;
        RECT  0 50.4 0.084 50.424 ;
    END
  END q[436]
  PIN q[437]
    DIRECTION OUTPUT ;
    USE SIGNAL ;
    PORT
      LAYER M4 ;
        RECT  0 50.592 0.084 50.616 ;
    END
  END q[437]
  PIN q[438]
    DIRECTION OUTPUT ;
    USE SIGNAL ;
    PORT
      LAYER M4 ;
        RECT  0 50.688 0.084 50.712 ;
    END
  END q[438]
  PIN q[439]
    DIRECTION OUTPUT ;
    USE SIGNAL ;
    PORT
      LAYER M4 ;
        RECT  0 50.784 0.084 50.808 ;
    END
  END q[439]
  PIN q[43]
    DIRECTION OUTPUT ;
    USE SIGNAL ;
    PORT
      LAYER M4 ;
        RECT  0 11.712 0.084 11.736 ;
    END
  END q[43]
  PIN q[440]
    DIRECTION OUTPUT ;
    USE SIGNAL ;
    PORT
      LAYER M4 ;
        RECT  0 50.88 0.084 50.904 ;
    END
  END q[440]
  PIN q[441]
    DIRECTION OUTPUT ;
    USE SIGNAL ;
    PORT
      LAYER M4 ;
        RECT  0 50.976 0.084 51 ;
    END
  END q[441]
  PIN q[442]
    DIRECTION OUTPUT ;
    USE SIGNAL ;
    PORT
      LAYER M4 ;
        RECT  0 51.072 0.084 51.096 ;
    END
  END q[442]
  PIN q[443]
    DIRECTION OUTPUT ;
    USE SIGNAL ;
    PORT
      LAYER M4 ;
        RECT  0 51.168 0.084 51.192 ;
    END
  END q[443]
  PIN q[444]
    DIRECTION OUTPUT ;
    USE SIGNAL ;
    PORT
      LAYER M4 ;
        RECT  0 51.264 0.084 51.288 ;
    END
  END q[444]
  PIN q[445]
    DIRECTION OUTPUT ;
    USE SIGNAL ;
    PORT
      LAYER M4 ;
        RECT  0 51.36 0.084 51.384 ;
    END
  END q[445]
  PIN q[446]
    DIRECTION OUTPUT ;
    USE SIGNAL ;
    PORT
      LAYER M4 ;
        RECT  0 51.456 0.084 51.48 ;
    END
  END q[446]
  PIN q[447]
    DIRECTION OUTPUT ;
    USE SIGNAL ;
    PORT
      LAYER M4 ;
        RECT  0 51.552 0.084 51.576 ;
    END
  END q[447]
  PIN q[448]
    DIRECTION OUTPUT ;
    USE SIGNAL ;
    PORT
      LAYER M4 ;
        RECT  0 51.648 0.084 51.672 ;
    END
  END q[448]
  PIN q[449]
    DIRECTION OUTPUT ;
    USE SIGNAL ;
    PORT
      LAYER M4 ;
        RECT  0 51.744 0.084 51.768 ;
    END
  END q[449]
  PIN q[44]
    DIRECTION OUTPUT ;
    USE SIGNAL ;
    PORT
      LAYER M4 ;
        RECT  0 12 0.084 12.024 ;
    END
  END q[44]
  PIN q[450]
    DIRECTION OUTPUT ;
    USE SIGNAL ;
    PORT
      LAYER M4 ;
        RECT  0 51.84 0.084 51.864 ;
    END
  END q[450]
  PIN q[451]
    DIRECTION OUTPUT ;
    USE SIGNAL ;
    PORT
      LAYER M4 ;
        RECT  0 51.936 0.084 51.96 ;
    END
  END q[451]
  PIN q[452]
    DIRECTION OUTPUT ;
    USE SIGNAL ;
    PORT
      LAYER M4 ;
        RECT  0 52.032 0.084 52.056 ;
    END
  END q[452]
  PIN q[453]
    DIRECTION OUTPUT ;
    USE SIGNAL ;
    PORT
      LAYER M4 ;
        RECT  0 52.128 0.084 52.152 ;
    END
  END q[453]
  PIN q[454]
    DIRECTION OUTPUT ;
    USE SIGNAL ;
    PORT
      LAYER M4 ;
        RECT  0 52.224 0.084 52.248 ;
    END
  END q[454]
  PIN q[455]
    DIRECTION OUTPUT ;
    USE SIGNAL ;
    PORT
      LAYER M4 ;
        RECT  0 52.416 0.084 52.44 ;
    END
  END q[455]
  PIN q[456]
    DIRECTION OUTPUT ;
    USE SIGNAL ;
    PORT
      LAYER M4 ;
        RECT  0 52.32 0.084 52.344 ;
    END
  END q[456]
  PIN q[457]
    DIRECTION OUTPUT ;
    USE SIGNAL ;
    PORT
      LAYER M4 ;
        RECT  0 52.512 0.084 52.536 ;
    END
  END q[457]
  PIN q[458]
    DIRECTION OUTPUT ;
    USE SIGNAL ;
    PORT
      LAYER M4 ;
        RECT  0 52.608 0.084 52.632 ;
    END
  END q[458]
  PIN q[459]
    DIRECTION OUTPUT ;
    USE SIGNAL ;
    PORT
      LAYER M4 ;
        RECT  0 52.704 0.084 52.728 ;
    END
  END q[459]
  PIN q[45]
    DIRECTION OUTPUT ;
    USE SIGNAL ;
    PORT
      LAYER M4 ;
        RECT  0 11.904 0.084 11.928 ;
    END
  END q[45]
  PIN q[460]
    DIRECTION OUTPUT ;
    USE SIGNAL ;
    PORT
      LAYER M4 ;
        RECT  0 52.8 0.084 52.824 ;
    END
  END q[460]
  PIN q[461]
    DIRECTION OUTPUT ;
    USE SIGNAL ;
    PORT
      LAYER M4 ;
        RECT  0 52.896 0.084 52.92 ;
    END
  END q[461]
  PIN q[462]
    DIRECTION OUTPUT ;
    USE SIGNAL ;
    PORT
      LAYER M4 ;
        RECT  0 52.992 0.084 53.016 ;
    END
  END q[462]
  PIN q[463]
    DIRECTION OUTPUT ;
    USE SIGNAL ;
    PORT
      LAYER M4 ;
        RECT  0 53.088 0.084 53.112 ;
    END
  END q[463]
  PIN q[464]
    DIRECTION OUTPUT ;
    USE SIGNAL ;
    PORT
      LAYER M4 ;
        RECT  0 53.184 0.084 53.208 ;
    END
  END q[464]
  PIN q[465]
    DIRECTION OUTPUT ;
    USE SIGNAL ;
    PORT
      LAYER M4 ;
        RECT  0 53.28 0.084 53.304 ;
    END
  END q[465]
  PIN q[466]
    DIRECTION OUTPUT ;
    USE SIGNAL ;
    PORT
      LAYER M4 ;
        RECT  0 53.376 0.084 53.4 ;
    END
  END q[466]
  PIN q[467]
    DIRECTION OUTPUT ;
    USE SIGNAL ;
    PORT
      LAYER M4 ;
        RECT  0 53.472 0.084 53.496 ;
    END
  END q[467]
  PIN q[468]
    DIRECTION OUTPUT ;
    USE SIGNAL ;
    PORT
      LAYER M4 ;
        RECT  0 53.568 0.084 53.592 ;
    END
  END q[468]
  PIN q[469]
    DIRECTION OUTPUT ;
    USE SIGNAL ;
    PORT
      LAYER M4 ;
        RECT  0 53.664 0.084 53.688 ;
    END
  END q[469]
  PIN q[46]
    DIRECTION OUTPUT ;
    USE SIGNAL ;
    PORT
      LAYER M4 ;
        RECT  0 12.096 0.084 12.12 ;
    END
  END q[46]
  PIN q[470]
    DIRECTION OUTPUT ;
    USE SIGNAL ;
    PORT
      LAYER M4 ;
        RECT  0 53.76 0.084 53.784 ;
    END
  END q[470]
  PIN q[471]
    DIRECTION OUTPUT ;
    USE SIGNAL ;
    PORT
      LAYER M4 ;
        RECT  0 53.856 0.084 53.88 ;
    END
  END q[471]
  PIN q[472]
    DIRECTION OUTPUT ;
    USE SIGNAL ;
    PORT
      LAYER M4 ;
        RECT  0 53.952 0.084 53.976 ;
    END
  END q[472]
  PIN q[473]
    DIRECTION OUTPUT ;
    USE SIGNAL ;
    PORT
      LAYER M4 ;
        RECT  0 54.048 0.084 54.072 ;
    END
  END q[473]
  PIN q[474]
    DIRECTION OUTPUT ;
    USE SIGNAL ;
    PORT
      LAYER M4 ;
        RECT  0 54.144 0.084 54.168 ;
    END
  END q[474]
  PIN q[475]
    DIRECTION OUTPUT ;
    USE SIGNAL ;
    PORT
      LAYER M4 ;
        RECT  0 54.336 0.084 54.36 ;
    END
  END q[475]
  PIN q[476]
    DIRECTION OUTPUT ;
    USE SIGNAL ;
    PORT
      LAYER M4 ;
        RECT  0 54.24 0.084 54.264 ;
    END
  END q[476]
  PIN q[477]
    DIRECTION OUTPUT ;
    USE SIGNAL ;
    PORT
      LAYER M4 ;
        RECT  0 54.432 0.084 54.456 ;
    END
  END q[477]
  PIN q[478]
    DIRECTION OUTPUT ;
    USE SIGNAL ;
    PORT
      LAYER M4 ;
        RECT  0 54.624 0.084 54.648 ;
    END
  END q[478]
  PIN q[479]
    DIRECTION OUTPUT ;
    USE SIGNAL ;
    PORT
      LAYER M4 ;
        RECT  0 54.528 0.084 54.552 ;
    END
  END q[479]
  PIN q[47]
    DIRECTION OUTPUT ;
    USE SIGNAL ;
    PORT
      LAYER M4 ;
        RECT  0 12.192 0.084 12.216 ;
    END
  END q[47]
  PIN q[480]
    DIRECTION OUTPUT ;
    USE SIGNAL ;
    PORT
      LAYER M4 ;
        RECT  0 54.72 0.084 54.744 ;
    END
  END q[480]
  PIN q[481]
    DIRECTION OUTPUT ;
    USE SIGNAL ;
    PORT
      LAYER M4 ;
        RECT  0 54.816 0.084 54.84 ;
    END
  END q[481]
  PIN q[482]
    DIRECTION OUTPUT ;
    USE SIGNAL ;
    PORT
      LAYER M4 ;
        RECT  0 54.912 0.084 54.936 ;
    END
  END q[482]
  PIN q[483]
    DIRECTION OUTPUT ;
    USE SIGNAL ;
    PORT
      LAYER M4 ;
        RECT  0 55.008 0.084 55.032 ;
    END
  END q[483]
  PIN q[484]
    DIRECTION OUTPUT ;
    USE SIGNAL ;
    PORT
      LAYER M4 ;
        RECT  0 55.104 0.084 55.128 ;
    END
  END q[484]
  PIN q[485]
    DIRECTION OUTPUT ;
    USE SIGNAL ;
    PORT
      LAYER M4 ;
        RECT  0 55.2 0.084 55.224 ;
    END
  END q[485]
  PIN q[486]
    DIRECTION OUTPUT ;
    USE SIGNAL ;
    PORT
      LAYER M4 ;
        RECT  0 55.296 0.084 55.32 ;
    END
  END q[486]
  PIN q[487]
    DIRECTION OUTPUT ;
    USE SIGNAL ;
    PORT
      LAYER M4 ;
        RECT  0 55.392 0.084 55.416 ;
    END
  END q[487]
  PIN q[488]
    DIRECTION OUTPUT ;
    USE SIGNAL ;
    PORT
      LAYER M4 ;
        RECT  0 55.488 0.084 55.512 ;
    END
  END q[488]
  PIN q[489]
    DIRECTION OUTPUT ;
    USE SIGNAL ;
    PORT
      LAYER M4 ;
        RECT  0 55.584 0.084 55.608 ;
    END
  END q[489]
  PIN q[48]
    DIRECTION OUTPUT ;
    USE SIGNAL ;
    PORT
      LAYER M4 ;
        RECT  0 12.288 0.084 12.312 ;
    END
  END q[48]
  PIN q[490]
    DIRECTION OUTPUT ;
    USE SIGNAL ;
    PORT
      LAYER M4 ;
        RECT  0 55.68 0.084 55.704 ;
    END
  END q[490]
  PIN q[491]
    DIRECTION OUTPUT ;
    USE SIGNAL ;
    PORT
      LAYER M4 ;
        RECT  0 55.776 0.084 55.8 ;
    END
  END q[491]
  PIN q[492]
    DIRECTION OUTPUT ;
    USE SIGNAL ;
    PORT
      LAYER M4 ;
        RECT  0 55.872 0.084 55.896 ;
    END
  END q[492]
  PIN q[493]
    DIRECTION OUTPUT ;
    USE SIGNAL ;
    PORT
      LAYER M4 ;
        RECT  0 55.968 0.084 55.992 ;
    END
  END q[493]
  PIN q[494]
    DIRECTION OUTPUT ;
    USE SIGNAL ;
    PORT
      LAYER M4 ;
        RECT  0 56.064 0.084 56.088 ;
    END
  END q[494]
  PIN q[495]
    DIRECTION OUTPUT ;
    USE SIGNAL ;
    PORT
      LAYER M4 ;
        RECT  0 56.352 0.084 56.376 ;
    END
  END q[495]
  PIN q[496]
    DIRECTION OUTPUT ;
    USE SIGNAL ;
    PORT
      LAYER M4 ;
        RECT  0 56.16 0.084 56.184 ;
    END
  END q[496]
  PIN q[497]
    DIRECTION OUTPUT ;
    USE SIGNAL ;
    PORT
      LAYER M4 ;
        RECT  0 56.448 0.084 56.472 ;
    END
  END q[497]
  PIN q[498]
    DIRECTION OUTPUT ;
    USE SIGNAL ;
    PORT
      LAYER M4 ;
        RECT  0 56.256 0.084 56.28 ;
    END
  END q[498]
  PIN q[499]
    DIRECTION OUTPUT ;
    USE SIGNAL ;
    PORT
      LAYER M4 ;
        RECT  0 56.544 0.084 56.568 ;
    END
  END q[499]
  PIN q[49]
    DIRECTION OUTPUT ;
    USE SIGNAL ;
    PORT
      LAYER M4 ;
        RECT  0 12.384 0.084 12.408 ;
    END
  END q[49]
  PIN q[4]
    DIRECTION OUTPUT ;
    USE SIGNAL ;
    PORT
      LAYER M4 ;
        RECT  0 8.064 0.084 8.088 ;
    END
  END q[4]
  PIN q[500]
    DIRECTION OUTPUT ;
    USE SIGNAL ;
    PORT
      LAYER M4 ;
        RECT  0 56.64 0.084 56.664 ;
    END
  END q[500]
  PIN q[501]
    DIRECTION OUTPUT ;
    USE SIGNAL ;
    PORT
      LAYER M4 ;
        RECT  0 56.736 0.084 56.76 ;
    END
  END q[501]
  PIN q[502]
    DIRECTION OUTPUT ;
    USE SIGNAL ;
    PORT
      LAYER M4 ;
        RECT  0 56.832 0.084 56.856 ;
    END
  END q[502]
  PIN q[503]
    DIRECTION OUTPUT ;
    USE SIGNAL ;
    PORT
      LAYER M4 ;
        RECT  0 56.928 0.084 56.952 ;
    END
  END q[503]
  PIN q[504]
    DIRECTION OUTPUT ;
    USE SIGNAL ;
    PORT
      LAYER M4 ;
        RECT  0 57.024 0.084 57.048 ;
    END
  END q[504]
  PIN q[505]
    DIRECTION OUTPUT ;
    USE SIGNAL ;
    PORT
      LAYER M4 ;
        RECT  0 57.12 0.084 57.144 ;
    END
  END q[505]
  PIN q[506]
    DIRECTION OUTPUT ;
    USE SIGNAL ;
    PORT
      LAYER M4 ;
        RECT  0 57.216 0.084 57.24 ;
    END
  END q[506]
  PIN q[507]
    DIRECTION OUTPUT ;
    USE SIGNAL ;
    PORT
      LAYER M4 ;
        RECT  0 57.312 0.084 57.336 ;
    END
  END q[507]
  PIN q[508]
    DIRECTION OUTPUT ;
    USE SIGNAL ;
    PORT
      LAYER M4 ;
        RECT  0 57.408 0.084 57.432 ;
    END
  END q[508]
  PIN q[509]
    DIRECTION OUTPUT ;
    USE SIGNAL ;
    PORT
      LAYER M4 ;
        RECT  0 57.504 0.084 57.528 ;
    END
  END q[509]
  PIN q[50]
    DIRECTION OUTPUT ;
    USE SIGNAL ;
    PORT
      LAYER M4 ;
        RECT  0 12.48 0.084 12.504 ;
    END
  END q[50]
  PIN q[510]
    DIRECTION OUTPUT ;
    USE SIGNAL ;
    PORT
      LAYER M4 ;
        RECT  0 57.6 0.084 57.624 ;
    END
  END q[510]
  PIN q[511]
    DIRECTION OUTPUT ;
    USE SIGNAL ;
    PORT
      LAYER M4 ;
        RECT  0 57.696 0.084 57.72 ;
    END
  END q[511]
  PIN q[512]
    DIRECTION OUTPUT ;
    USE SIGNAL ;
    PORT
      LAYER M4 ;
        RECT  0 57.792 0.084 57.816 ;
    END
  END q[512]
  PIN q[513]
    DIRECTION OUTPUT ;
    USE SIGNAL ;
    PORT
      LAYER M4 ;
        RECT  0 57.888 0.084 57.912 ;
    END
  END q[513]
  PIN q[514]
    DIRECTION OUTPUT ;
    USE SIGNAL ;
    PORT
      LAYER M4 ;
        RECT  0 57.984 0.084 58.008 ;
    END
  END q[514]
  PIN q[515]
    DIRECTION OUTPUT ;
    USE SIGNAL ;
    PORT
      LAYER M4 ;
        RECT  0 58.08 0.084 58.104 ;
    END
  END q[515]
  PIN q[516]
    DIRECTION OUTPUT ;
    USE SIGNAL ;
    PORT
      LAYER M4 ;
        RECT  0 58.176 0.084 58.2 ;
    END
  END q[516]
  PIN q[517]
    DIRECTION OUTPUT ;
    USE SIGNAL ;
    PORT
      LAYER M4 ;
        RECT  0 58.368 0.084 58.392 ;
    END
  END q[517]
  PIN q[518]
    DIRECTION OUTPUT ;
    USE SIGNAL ;
    PORT
      LAYER M4 ;
        RECT  0 58.272 0.084 58.296 ;
    END
  END q[518]
  PIN q[519]
    DIRECTION OUTPUT ;
    USE SIGNAL ;
    PORT
      LAYER M4 ;
        RECT  0 58.464 0.084 58.488 ;
    END
  END q[519]
  PIN q[51]
    DIRECTION OUTPUT ;
    USE SIGNAL ;
    PORT
      LAYER M4 ;
        RECT  0 12.576 0.084 12.6 ;
    END
  END q[51]
  PIN q[520]
    DIRECTION OUTPUT ;
    USE SIGNAL ;
    PORT
      LAYER M4 ;
        RECT  0 58.56 0.084 58.584 ;
    END
  END q[520]
  PIN q[521]
    DIRECTION OUTPUT ;
    USE SIGNAL ;
    PORT
      LAYER M4 ;
        RECT  0 58.656 0.084 58.68 ;
    END
  END q[521]
  PIN q[522]
    DIRECTION OUTPUT ;
    USE SIGNAL ;
    PORT
      LAYER M4 ;
        RECT  0 58.752 0.084 58.776 ;
    END
  END q[522]
  PIN q[523]
    DIRECTION OUTPUT ;
    USE SIGNAL ;
    PORT
      LAYER M4 ;
        RECT  0 58.848 0.084 58.872 ;
    END
  END q[523]
  PIN q[524]
    DIRECTION OUTPUT ;
    USE SIGNAL ;
    PORT
      LAYER M4 ;
        RECT  0 58.944 0.084 58.968 ;
    END
  END q[524]
  PIN q[525]
    DIRECTION OUTPUT ;
    USE SIGNAL ;
    PORT
      LAYER M4 ;
        RECT  0 59.04 0.084 59.064 ;
    END
  END q[525]
  PIN q[526]
    DIRECTION OUTPUT ;
    USE SIGNAL ;
    PORT
      LAYER M4 ;
        RECT  0 59.136 0.084 59.16 ;
    END
  END q[526]
  PIN q[527]
    DIRECTION OUTPUT ;
    USE SIGNAL ;
    PORT
      LAYER M4 ;
        RECT  0 59.232 0.084 59.256 ;
    END
  END q[527]
  PIN q[528]
    DIRECTION OUTPUT ;
    USE SIGNAL ;
    PORT
      LAYER M4 ;
        RECT  0 59.328 0.084 59.352 ;
    END
  END q[528]
  PIN q[529]
    DIRECTION OUTPUT ;
    USE SIGNAL ;
    PORT
      LAYER M4 ;
        RECT  0 59.424 0.084 59.448 ;
    END
  END q[529]
  PIN q[52]
    DIRECTION OUTPUT ;
    USE SIGNAL ;
    PORT
      LAYER M4 ;
        RECT  0 12.672 0.084 12.696 ;
    END
  END q[52]
  PIN q[530]
    DIRECTION OUTPUT ;
    USE SIGNAL ;
    PORT
      LAYER M4 ;
        RECT  0 59.52 0.084 59.544 ;
    END
  END q[530]
  PIN q[531]
    DIRECTION OUTPUT ;
    USE SIGNAL ;
    PORT
      LAYER M4 ;
        RECT  0 59.616 0.084 59.64 ;
    END
  END q[531]
  PIN q[532]
    DIRECTION OUTPUT ;
    USE SIGNAL ;
    PORT
      LAYER M4 ;
        RECT  0 59.712 0.084 59.736 ;
    END
  END q[532]
  PIN q[533]
    DIRECTION OUTPUT ;
    USE SIGNAL ;
    PORT
      LAYER M4 ;
        RECT  0 59.808 0.084 59.832 ;
    END
  END q[533]
  PIN q[534]
    DIRECTION OUTPUT ;
    USE SIGNAL ;
    PORT
      LAYER M4 ;
        RECT  0 59.904 0.084 59.928 ;
    END
  END q[534]
  PIN q[535]
    DIRECTION OUTPUT ;
    USE SIGNAL ;
    PORT
      LAYER M4 ;
        RECT  0 60 0.084 60.024 ;
    END
  END q[535]
  PIN q[536]
    DIRECTION OUTPUT ;
    USE SIGNAL ;
    PORT
      LAYER M4 ;
        RECT  0 60.096 0.084 60.12 ;
    END
  END q[536]
  PIN q[537]
    DIRECTION OUTPUT ;
    USE SIGNAL ;
    PORT
      LAYER M4 ;
        RECT  0 60.288 0.084 60.312 ;
    END
  END q[537]
  PIN q[538]
    DIRECTION OUTPUT ;
    USE SIGNAL ;
    PORT
      LAYER M4 ;
        RECT  0 60.192 0.084 60.216 ;
    END
  END q[538]
  PIN q[539]
    DIRECTION OUTPUT ;
    USE SIGNAL ;
    PORT
      LAYER M4 ;
        RECT  0 60.384 0.084 60.408 ;
    END
  END q[539]
  PIN q[53]
    DIRECTION OUTPUT ;
    USE SIGNAL ;
    PORT
      LAYER M4 ;
        RECT  0 12.768 0.084 12.792 ;
    END
  END q[53]
  PIN q[540]
    DIRECTION OUTPUT ;
    USE SIGNAL ;
    PORT
      LAYER M4 ;
        RECT  0 60.576 0.084 60.6 ;
    END
  END q[540]
  PIN q[541]
    DIRECTION OUTPUT ;
    USE SIGNAL ;
    PORT
      LAYER M4 ;
        RECT  0 60.48 0.084 60.504 ;
    END
  END q[541]
  PIN q[542]
    DIRECTION OUTPUT ;
    USE SIGNAL ;
    PORT
      LAYER M4 ;
        RECT  0 60.672 0.084 60.696 ;
    END
  END q[542]
  PIN q[543]
    DIRECTION OUTPUT ;
    USE SIGNAL ;
    PORT
      LAYER M4 ;
        RECT  0 60.768 0.084 60.792 ;
    END
  END q[543]
  PIN q[544]
    DIRECTION OUTPUT ;
    USE SIGNAL ;
    PORT
      LAYER M4 ;
        RECT  0 60.864 0.084 60.888 ;
    END
  END q[544]
  PIN q[545]
    DIRECTION OUTPUT ;
    USE SIGNAL ;
    PORT
      LAYER M4 ;
        RECT  0 60.96 0.084 60.984 ;
    END
  END q[545]
  PIN q[546]
    DIRECTION OUTPUT ;
    USE SIGNAL ;
    PORT
      LAYER M4 ;
        RECT  0 61.056 0.084 61.08 ;
    END
  END q[546]
  PIN q[547]
    DIRECTION OUTPUT ;
    USE SIGNAL ;
    PORT
      LAYER M4 ;
        RECT  0 61.152 0.084 61.176 ;
    END
  END q[547]
  PIN q[548]
    DIRECTION OUTPUT ;
    USE SIGNAL ;
    PORT
      LAYER M4 ;
        RECT  0 61.248 0.084 61.272 ;
    END
  END q[548]
  PIN q[549]
    DIRECTION OUTPUT ;
    USE SIGNAL ;
    PORT
      LAYER M4 ;
        RECT  0 61.344 0.084 61.368 ;
    END
  END q[549]
  PIN q[54]
    DIRECTION OUTPUT ;
    USE SIGNAL ;
    PORT
      LAYER M4 ;
        RECT  0 12.864 0.084 12.888 ;
    END
  END q[54]
  PIN q[550]
    DIRECTION OUTPUT ;
    USE SIGNAL ;
    PORT
      LAYER M4 ;
        RECT  0 61.44 0.084 61.464 ;
    END
  END q[550]
  PIN q[551]
    DIRECTION OUTPUT ;
    USE SIGNAL ;
    PORT
      LAYER M4 ;
        RECT  0 61.536 0.084 61.56 ;
    END
  END q[551]
  PIN q[552]
    DIRECTION OUTPUT ;
    USE SIGNAL ;
    PORT
      LAYER M4 ;
        RECT  0 61.632 0.084 61.656 ;
    END
  END q[552]
  PIN q[553]
    DIRECTION OUTPUT ;
    USE SIGNAL ;
    PORT
      LAYER M4 ;
        RECT  0 61.728 0.084 61.752 ;
    END
  END q[553]
  PIN q[554]
    DIRECTION OUTPUT ;
    USE SIGNAL ;
    PORT
      LAYER M4 ;
        RECT  0 61.824 0.084 61.848 ;
    END
  END q[554]
  PIN q[555]
    DIRECTION OUTPUT ;
    USE SIGNAL ;
    PORT
      LAYER M4 ;
        RECT  0 61.92 0.084 61.944 ;
    END
  END q[555]
  PIN q[556]
    DIRECTION OUTPUT ;
    USE SIGNAL ;
    PORT
      LAYER M4 ;
        RECT  0 62.016 0.084 62.04 ;
    END
  END q[556]
  PIN q[557]
    DIRECTION OUTPUT ;
    USE SIGNAL ;
    PORT
      LAYER M4 ;
        RECT  0 62.208 0.084 62.232 ;
    END
  END q[557]
  PIN q[558]
    DIRECTION OUTPUT ;
    USE SIGNAL ;
    PORT
      LAYER M4 ;
        RECT  0 62.112 0.084 62.136 ;
    END
  END q[558]
  PIN q[559]
    DIRECTION OUTPUT ;
    USE SIGNAL ;
    PORT
      LAYER M4 ;
        RECT  0 62.4 0.084 62.424 ;
    END
  END q[559]
  PIN q[55]
    DIRECTION OUTPUT ;
    USE SIGNAL ;
    PORT
      LAYER M4 ;
        RECT  0 12.96 0.084 12.984 ;
    END
  END q[55]
  PIN q[560]
    DIRECTION OUTPUT ;
    USE SIGNAL ;
    PORT
      LAYER M4 ;
        RECT  0 62.304 0.084 62.328 ;
    END
  END q[560]
  PIN q[561]
    DIRECTION OUTPUT ;
    USE SIGNAL ;
    PORT
      LAYER M4 ;
        RECT  0 62.496 0.084 62.52 ;
    END
  END q[561]
  PIN q[562]
    DIRECTION OUTPUT ;
    USE SIGNAL ;
    PORT
      LAYER M4 ;
        RECT  0 62.592 0.084 62.616 ;
    END
  END q[562]
  PIN q[563]
    DIRECTION OUTPUT ;
    USE SIGNAL ;
    PORT
      LAYER M4 ;
        RECT  0 62.688 0.084 62.712 ;
    END
  END q[563]
  PIN q[564]
    DIRECTION OUTPUT ;
    USE SIGNAL ;
    PORT
      LAYER M4 ;
        RECT  0 62.784 0.084 62.808 ;
    END
  END q[564]
  PIN q[565]
    DIRECTION OUTPUT ;
    USE SIGNAL ;
    PORT
      LAYER M4 ;
        RECT  0 62.88 0.084 62.904 ;
    END
  END q[565]
  PIN q[566]
    DIRECTION OUTPUT ;
    USE SIGNAL ;
    PORT
      LAYER M4 ;
        RECT  0 62.976 0.084 63 ;
    END
  END q[566]
  PIN q[567]
    DIRECTION OUTPUT ;
    USE SIGNAL ;
    PORT
      LAYER M4 ;
        RECT  0 63.072 0.084 63.096 ;
    END
  END q[567]
  PIN q[568]
    DIRECTION OUTPUT ;
    USE SIGNAL ;
    PORT
      LAYER M4 ;
        RECT  0 63.168 0.084 63.192 ;
    END
  END q[568]
  PIN q[569]
    DIRECTION OUTPUT ;
    USE SIGNAL ;
    PORT
      LAYER M4 ;
        RECT  0 63.264 0.084 63.288 ;
    END
  END q[569]
  PIN q[56]
    DIRECTION OUTPUT ;
    USE SIGNAL ;
    PORT
      LAYER M4 ;
        RECT  0 13.152 0.084 13.176 ;
    END
  END q[56]
  PIN q[570]
    DIRECTION OUTPUT ;
    USE SIGNAL ;
    PORT
      LAYER M4 ;
        RECT  0 63.36 0.084 63.384 ;
    END
  END q[570]
  PIN q[571]
    DIRECTION OUTPUT ;
    USE SIGNAL ;
    PORT
      LAYER M4 ;
        RECT  0 63.456 0.084 63.48 ;
    END
  END q[571]
  PIN q[572]
    DIRECTION OUTPUT ;
    USE SIGNAL ;
    PORT
      LAYER M4 ;
        RECT  0 63.552 0.084 63.576 ;
    END
  END q[572]
  PIN q[573]
    DIRECTION OUTPUT ;
    USE SIGNAL ;
    PORT
      LAYER M4 ;
        RECT  0 63.648 0.084 63.672 ;
    END
  END q[573]
  PIN q[574]
    DIRECTION OUTPUT ;
    USE SIGNAL ;
    PORT
      LAYER M4 ;
        RECT  0 63.744 0.084 63.768 ;
    END
  END q[574]
  PIN q[575]
    DIRECTION OUTPUT ;
    USE SIGNAL ;
    PORT
      LAYER M4 ;
        RECT  0 63.84 0.084 63.864 ;
    END
  END q[575]
  PIN q[576]
    DIRECTION OUTPUT ;
    USE SIGNAL ;
    PORT
      LAYER M4 ;
        RECT  0 63.936 0.084 63.96 ;
    END
  END q[576]
  PIN q[577]
    DIRECTION OUTPUT ;
    USE SIGNAL ;
    PORT
      LAYER M4 ;
        RECT  0 64.032 0.084 64.056 ;
    END
  END q[577]
  PIN q[578]
    DIRECTION OUTPUT ;
    USE SIGNAL ;
    PORT
      LAYER M4 ;
        RECT  0 64.128 0.084 64.152 ;
    END
  END q[578]
  PIN q[579]
    DIRECTION OUTPUT ;
    USE SIGNAL ;
    PORT
      LAYER M4 ;
        RECT  0 64.32 0.084 64.344 ;
    END
  END q[579]
  PIN q[57]
    DIRECTION OUTPUT ;
    USE SIGNAL ;
    PORT
      LAYER M4 ;
        RECT  0 13.056 0.084 13.08 ;
    END
  END q[57]
  PIN q[580]
    DIRECTION OUTPUT ;
    USE SIGNAL ;
    PORT
      LAYER M4 ;
        RECT  0 64.224 0.084 64.248 ;
    END
  END q[580]
  PIN q[581]
    DIRECTION OUTPUT ;
    USE SIGNAL ;
    PORT
      LAYER M4 ;
        RECT  0 64.416 0.084 64.44 ;
    END
  END q[581]
  PIN q[582]
    DIRECTION OUTPUT ;
    USE SIGNAL ;
    PORT
      LAYER M4 ;
        RECT  0 64.512 0.084 64.536 ;
    END
  END q[582]
  PIN q[583]
    DIRECTION OUTPUT ;
    USE SIGNAL ;
    PORT
      LAYER M4 ;
        RECT  0 64.608 0.084 64.632 ;
    END
  END q[583]
  PIN q[584]
    DIRECTION OUTPUT ;
    USE SIGNAL ;
    PORT
      LAYER M4 ;
        RECT  0 64.704 0.084 64.728 ;
    END
  END q[584]
  PIN q[585]
    DIRECTION OUTPUT ;
    USE SIGNAL ;
    PORT
      LAYER M4 ;
        RECT  0 64.8 0.084 64.824 ;
    END
  END q[585]
  PIN q[586]
    DIRECTION OUTPUT ;
    USE SIGNAL ;
    PORT
      LAYER M4 ;
        RECT  0 64.896 0.084 64.92 ;
    END
  END q[586]
  PIN q[587]
    DIRECTION OUTPUT ;
    USE SIGNAL ;
    PORT
      LAYER M4 ;
        RECT  0 64.992 0.084 65.016 ;
    END
  END q[587]
  PIN q[588]
    DIRECTION OUTPUT ;
    USE SIGNAL ;
    PORT
      LAYER M4 ;
        RECT  0 65.088 0.084 65.112 ;
    END
  END q[588]
  PIN q[589]
    DIRECTION OUTPUT ;
    USE SIGNAL ;
    PORT
      LAYER M4 ;
        RECT  0 65.184 0.084 65.208 ;
    END
  END q[589]
  PIN q[58]
    DIRECTION OUTPUT ;
    USE SIGNAL ;
    PORT
      LAYER M4 ;
        RECT  0 13.248 0.084 13.272 ;
    END
  END q[58]
  PIN q[590]
    DIRECTION OUTPUT ;
    USE SIGNAL ;
    PORT
      LAYER M4 ;
        RECT  0 65.28 0.084 65.304 ;
    END
  END q[590]
  PIN q[591]
    DIRECTION OUTPUT ;
    USE SIGNAL ;
    PORT
      LAYER M4 ;
        RECT  0 65.376 0.084 65.4 ;
    END
  END q[591]
  PIN q[592]
    DIRECTION OUTPUT ;
    USE SIGNAL ;
    PORT
      LAYER M4 ;
        RECT  0 65.472 0.084 65.496 ;
    END
  END q[592]
  PIN q[593]
    DIRECTION OUTPUT ;
    USE SIGNAL ;
    PORT
      LAYER M4 ;
        RECT  0 65.568 0.084 65.592 ;
    END
  END q[593]
  PIN q[594]
    DIRECTION OUTPUT ;
    USE SIGNAL ;
    PORT
      LAYER M4 ;
        RECT  0 65.664 0.084 65.688 ;
    END
  END q[594]
  PIN q[595]
    DIRECTION OUTPUT ;
    USE SIGNAL ;
    PORT
      LAYER M4 ;
        RECT  0 65.76 0.084 65.784 ;
    END
  END q[595]
  PIN q[596]
    DIRECTION OUTPUT ;
    USE SIGNAL ;
    PORT
      LAYER M4 ;
        RECT  0 65.856 0.084 65.88 ;
    END
  END q[596]
  PIN q[597]
    DIRECTION OUTPUT ;
    USE SIGNAL ;
    PORT
      LAYER M4 ;
        RECT  0 65.952 0.084 65.976 ;
    END
  END q[597]
  PIN q[598]
    DIRECTION OUTPUT ;
    USE SIGNAL ;
    PORT
      LAYER M4 ;
        RECT  0 66.048 0.084 66.072 ;
    END
  END q[598]
  PIN q[599]
    DIRECTION OUTPUT ;
    USE SIGNAL ;
    PORT
      LAYER M4 ;
        RECT  0 66.336 0.084 66.36 ;
    END
  END q[599]
  PIN q[59]
    DIRECTION OUTPUT ;
    USE SIGNAL ;
    PORT
      LAYER M4 ;
        RECT  0 13.344 0.084 13.368 ;
    END
  END q[59]
  PIN q[5]
    DIRECTION OUTPUT ;
    USE SIGNAL ;
    PORT
      LAYER M4 ;
        RECT  0 8.16 0.084 8.184 ;
    END
  END q[5]
  PIN q[600]
    DIRECTION OUTPUT ;
    USE SIGNAL ;
    PORT
      LAYER M4 ;
        RECT  0 66.144 0.084 66.168 ;
    END
  END q[600]
  PIN q[601]
    DIRECTION OUTPUT ;
    USE SIGNAL ;
    PORT
      LAYER M4 ;
        RECT  0 66.432 0.084 66.456 ;
    END
  END q[601]
  PIN q[602]
    DIRECTION OUTPUT ;
    USE SIGNAL ;
    PORT
      LAYER M4 ;
        RECT  0 66.24 0.084 66.264 ;
    END
  END q[602]
  PIN q[603]
    DIRECTION OUTPUT ;
    USE SIGNAL ;
    PORT
      LAYER M4 ;
        RECT  0 66.528 0.084 66.552 ;
    END
  END q[603]
  PIN q[604]
    DIRECTION OUTPUT ;
    USE SIGNAL ;
    PORT
      LAYER M4 ;
        RECT  0 66.624 0.084 66.648 ;
    END
  END q[604]
  PIN q[605]
    DIRECTION OUTPUT ;
    USE SIGNAL ;
    PORT
      LAYER M4 ;
        RECT  0 66.72 0.084 66.744 ;
    END
  END q[605]
  PIN q[606]
    DIRECTION OUTPUT ;
    USE SIGNAL ;
    PORT
      LAYER M4 ;
        RECT  0 66.816 0.084 66.84 ;
    END
  END q[606]
  PIN q[607]
    DIRECTION OUTPUT ;
    USE SIGNAL ;
    PORT
      LAYER M4 ;
        RECT  0 66.912 0.084 66.936 ;
    END
  END q[607]
  PIN q[608]
    DIRECTION OUTPUT ;
    USE SIGNAL ;
    PORT
      LAYER M4 ;
        RECT  0 67.008 0.084 67.032 ;
    END
  END q[608]
  PIN q[609]
    DIRECTION OUTPUT ;
    USE SIGNAL ;
    PORT
      LAYER M4 ;
        RECT  0 67.104 0.084 67.128 ;
    END
  END q[609]
  PIN q[60]
    DIRECTION OUTPUT ;
    USE SIGNAL ;
    PORT
      LAYER M4 ;
        RECT  0 13.44 0.084 13.464 ;
    END
  END q[60]
  PIN q[610]
    DIRECTION OUTPUT ;
    USE SIGNAL ;
    PORT
      LAYER M4 ;
        RECT  0 67.2 0.084 67.224 ;
    END
  END q[610]
  PIN q[611]
    DIRECTION OUTPUT ;
    USE SIGNAL ;
    PORT
      LAYER M4 ;
        RECT  0 67.296 0.084 67.32 ;
    END
  END q[611]
  PIN q[612]
    DIRECTION OUTPUT ;
    USE SIGNAL ;
    PORT
      LAYER M4 ;
        RECT  0 67.392 0.084 67.416 ;
    END
  END q[612]
  PIN q[613]
    DIRECTION OUTPUT ;
    USE SIGNAL ;
    PORT
      LAYER M4 ;
        RECT  0 67.488 0.084 67.512 ;
    END
  END q[613]
  PIN q[614]
    DIRECTION OUTPUT ;
    USE SIGNAL ;
    PORT
      LAYER M4 ;
        RECT  0 67.584 0.084 67.608 ;
    END
  END q[614]
  PIN q[615]
    DIRECTION OUTPUT ;
    USE SIGNAL ;
    PORT
      LAYER M4 ;
        RECT  0 67.68 0.084 67.704 ;
    END
  END q[615]
  PIN q[616]
    DIRECTION OUTPUT ;
    USE SIGNAL ;
    PORT
      LAYER M4 ;
        RECT  0 67.776 0.084 67.8 ;
    END
  END q[616]
  PIN q[617]
    DIRECTION OUTPUT ;
    USE SIGNAL ;
    PORT
      LAYER M4 ;
        RECT  0 67.872 0.084 67.896 ;
    END
  END q[617]
  PIN q[618]
    DIRECTION OUTPUT ;
    USE SIGNAL ;
    PORT
      LAYER M4 ;
        RECT  0 67.968 0.084 67.992 ;
    END
  END q[618]
  PIN q[619]
    DIRECTION OUTPUT ;
    USE SIGNAL ;
    PORT
      LAYER M4 ;
        RECT  0 68.16 0.084 68.184 ;
    END
  END q[619]
  PIN q[61]
    DIRECTION OUTPUT ;
    USE SIGNAL ;
    PORT
      LAYER M4 ;
        RECT  0 13.536 0.084 13.56 ;
    END
  END q[61]
  PIN q[620]
    DIRECTION OUTPUT ;
    USE SIGNAL ;
    PORT
      LAYER M4 ;
        RECT  0 68.064 0.084 68.088 ;
    END
  END q[620]
  PIN q[621]
    DIRECTION OUTPUT ;
    USE SIGNAL ;
    PORT
      LAYER M4 ;
        RECT  0 68.352 0.084 68.376 ;
    END
  END q[621]
  PIN q[622]
    DIRECTION OUTPUT ;
    USE SIGNAL ;
    PORT
      LAYER M4 ;
        RECT  0 68.256 0.084 68.28 ;
    END
  END q[622]
  PIN q[623]
    DIRECTION OUTPUT ;
    USE SIGNAL ;
    PORT
      LAYER M4 ;
        RECT  0 68.448 0.084 68.472 ;
    END
  END q[623]
  PIN q[624]
    DIRECTION OUTPUT ;
    USE SIGNAL ;
    PORT
      LAYER M4 ;
        RECT  0 68.544 0.084 68.568 ;
    END
  END q[624]
  PIN q[625]
    DIRECTION OUTPUT ;
    USE SIGNAL ;
    PORT
      LAYER M4 ;
        RECT  0 68.64 0.084 68.664 ;
    END
  END q[625]
  PIN q[626]
    DIRECTION OUTPUT ;
    USE SIGNAL ;
    PORT
      LAYER M4 ;
        RECT  0 68.736 0.084 68.76 ;
    END
  END q[626]
  PIN q[627]
    DIRECTION OUTPUT ;
    USE SIGNAL ;
    PORT
      LAYER M4 ;
        RECT  0 68.832 0.084 68.856 ;
    END
  END q[627]
  PIN q[628]
    DIRECTION OUTPUT ;
    USE SIGNAL ;
    PORT
      LAYER M4 ;
        RECT  0 68.928 0.084 68.952 ;
    END
  END q[628]
  PIN q[629]
    DIRECTION OUTPUT ;
    USE SIGNAL ;
    PORT
      LAYER M4 ;
        RECT  0 69.024 0.084 69.048 ;
    END
  END q[629]
  PIN q[62]
    DIRECTION OUTPUT ;
    USE SIGNAL ;
    PORT
      LAYER M4 ;
        RECT  0 13.824 0.084 13.848 ;
    END
  END q[62]
  PIN q[630]
    DIRECTION OUTPUT ;
    USE SIGNAL ;
    PORT
      LAYER M4 ;
        RECT  0 69.12 0.084 69.144 ;
    END
  END q[630]
  PIN q[631]
    DIRECTION OUTPUT ;
    USE SIGNAL ;
    PORT
      LAYER M4 ;
        RECT  0 69.216 0.084 69.24 ;
    END
  END q[631]
  PIN q[632]
    DIRECTION OUTPUT ;
    USE SIGNAL ;
    PORT
      LAYER M4 ;
        RECT  0 69.312 0.084 69.336 ;
    END
  END q[632]
  PIN q[633]
    DIRECTION OUTPUT ;
    USE SIGNAL ;
    PORT
      LAYER M4 ;
        RECT  0 69.408 0.084 69.432 ;
    END
  END q[633]
  PIN q[634]
    DIRECTION OUTPUT ;
    USE SIGNAL ;
    PORT
      LAYER M4 ;
        RECT  0 69.504 0.084 69.528 ;
    END
  END q[634]
  PIN q[635]
    DIRECTION OUTPUT ;
    USE SIGNAL ;
    PORT
      LAYER M4 ;
        RECT  0 69.6 0.084 69.624 ;
    END
  END q[635]
  PIN q[636]
    DIRECTION OUTPUT ;
    USE SIGNAL ;
    PORT
      LAYER M4 ;
        RECT  0 69.696 0.084 69.72 ;
    END
  END q[636]
  PIN q[637]
    DIRECTION OUTPUT ;
    USE SIGNAL ;
    PORT
      LAYER M4 ;
        RECT  0 69.792 0.084 69.816 ;
    END
  END q[637]
  PIN q[638]
    DIRECTION OUTPUT ;
    USE SIGNAL ;
    PORT
      LAYER M4 ;
        RECT  0 69.888 0.084 69.912 ;
    END
  END q[638]
  PIN q[639]
    DIRECTION OUTPUT ;
    USE SIGNAL ;
    PORT
      LAYER M4 ;
        RECT  0 69.984 0.084 70.008 ;
    END
  END q[639]
  PIN q[63]
    DIRECTION OUTPUT ;
    USE SIGNAL ;
    PORT
      LAYER M4 ;
        RECT  0 13.632 0.084 13.656 ;
    END
  END q[63]
  PIN q[640]
    DIRECTION OUTPUT ;
    USE SIGNAL ;
    PORT
      LAYER M4 ;
        RECT  0 70.08 0.084 70.104 ;
    END
  END q[640]
  PIN q[641]
    DIRECTION OUTPUT ;
    USE SIGNAL ;
    PORT
      LAYER M4 ;
        RECT  0 70.272 0.084 70.296 ;
    END
  END q[641]
  PIN q[642]
    DIRECTION OUTPUT ;
    USE SIGNAL ;
    PORT
      LAYER M4 ;
        RECT  0 70.176 0.084 70.2 ;
    END
  END q[642]
  PIN q[643]
    DIRECTION OUTPUT ;
    USE SIGNAL ;
    PORT
      LAYER M4 ;
        RECT  0 70.368 0.084 70.392 ;
    END
  END q[643]
  PIN q[644]
    DIRECTION OUTPUT ;
    USE SIGNAL ;
    PORT
      LAYER M4 ;
        RECT  0 70.464 0.084 70.488 ;
    END
  END q[644]
  PIN q[645]
    DIRECTION OUTPUT ;
    USE SIGNAL ;
    PORT
      LAYER M4 ;
        RECT  0 70.56 0.084 70.584 ;
    END
  END q[645]
  PIN q[646]
    DIRECTION OUTPUT ;
    USE SIGNAL ;
    PORT
      LAYER M4 ;
        RECT  0 70.656 0.084 70.68 ;
    END
  END q[646]
  PIN q[647]
    DIRECTION OUTPUT ;
    USE SIGNAL ;
    PORT
      LAYER M4 ;
        RECT  0 70.752 0.084 70.776 ;
    END
  END q[647]
  PIN q[648]
    DIRECTION OUTPUT ;
    USE SIGNAL ;
    PORT
      LAYER M4 ;
        RECT  0 70.848 0.084 70.872 ;
    END
  END q[648]
  PIN q[649]
    DIRECTION OUTPUT ;
    USE SIGNAL ;
    PORT
      LAYER M4 ;
        RECT  0 70.944 0.084 70.968 ;
    END
  END q[649]
  PIN q[64]
    DIRECTION OUTPUT ;
    USE SIGNAL ;
    PORT
      LAYER M4 ;
        RECT  0 13.92 0.084 13.944 ;
    END
  END q[64]
  PIN q[650]
    DIRECTION OUTPUT ;
    USE SIGNAL ;
    PORT
      LAYER M4 ;
        RECT  0 71.04 0.084 71.064 ;
    END
  END q[650]
  PIN q[651]
    DIRECTION OUTPUT ;
    USE SIGNAL ;
    PORT
      LAYER M4 ;
        RECT  0 71.136 0.084 71.16 ;
    END
  END q[651]
  PIN q[652]
    DIRECTION OUTPUT ;
    USE SIGNAL ;
    PORT
      LAYER M4 ;
        RECT  0 71.232 0.084 71.256 ;
    END
  END q[652]
  PIN q[653]
    DIRECTION OUTPUT ;
    USE SIGNAL ;
    PORT
      LAYER M4 ;
        RECT  0 71.328 0.084 71.352 ;
    END
  END q[653]
  PIN q[654]
    DIRECTION OUTPUT ;
    USE SIGNAL ;
    PORT
      LAYER M4 ;
        RECT  0 71.424 0.084 71.448 ;
    END
  END q[654]
  PIN q[655]
    DIRECTION OUTPUT ;
    USE SIGNAL ;
    PORT
      LAYER M4 ;
        RECT  0 71.52 0.084 71.544 ;
    END
  END q[655]
  PIN q[656]
    DIRECTION OUTPUT ;
    USE SIGNAL ;
    PORT
      LAYER M4 ;
        RECT  0 71.616 0.084 71.64 ;
    END
  END q[656]
  PIN q[657]
    DIRECTION OUTPUT ;
    USE SIGNAL ;
    PORT
      LAYER M4 ;
        RECT  0 71.712 0.084 71.736 ;
    END
  END q[657]
  PIN q[658]
    DIRECTION OUTPUT ;
    USE SIGNAL ;
    PORT
      LAYER M4 ;
        RECT  0 71.808 0.084 71.832 ;
    END
  END q[658]
  PIN q[659]
    DIRECTION OUTPUT ;
    USE SIGNAL ;
    PORT
      LAYER M4 ;
        RECT  0 71.904 0.084 71.928 ;
    END
  END q[659]
  PIN q[65]
    DIRECTION OUTPUT ;
    USE SIGNAL ;
    PORT
      LAYER M4 ;
        RECT  0 13.728 0.084 13.752 ;
    END
  END q[65]
  PIN q[660]
    DIRECTION OUTPUT ;
    USE SIGNAL ;
    PORT
      LAYER M4 ;
        RECT  0 72 0.084 72.024 ;
    END
  END q[660]
  PIN q[661]
    DIRECTION OUTPUT ;
    USE SIGNAL ;
    PORT
      LAYER M4 ;
        RECT  0 72.288 0.084 72.312 ;
    END
  END q[661]
  PIN q[662]
    DIRECTION OUTPUT ;
    USE SIGNAL ;
    PORT
      LAYER M4 ;
        RECT  0 72.096 0.084 72.12 ;
    END
  END q[662]
  PIN q[663]
    DIRECTION OUTPUT ;
    USE SIGNAL ;
    PORT
      LAYER M4 ;
        RECT  0 72.384 0.084 72.408 ;
    END
  END q[663]
  PIN q[664]
    DIRECTION OUTPUT ;
    USE SIGNAL ;
    PORT
      LAYER M4 ;
        RECT  0 72.192 0.084 72.216 ;
    END
  END q[664]
  PIN q[665]
    DIRECTION OUTPUT ;
    USE SIGNAL ;
    PORT
      LAYER M4 ;
        RECT  0 72.48 0.084 72.504 ;
    END
  END q[665]
  PIN q[666]
    DIRECTION OUTPUT ;
    USE SIGNAL ;
    PORT
      LAYER M4 ;
        RECT  0 72.576 0.084 72.6 ;
    END
  END q[666]
  PIN q[667]
    DIRECTION OUTPUT ;
    USE SIGNAL ;
    PORT
      LAYER M4 ;
        RECT  0 72.672 0.084 72.696 ;
    END
  END q[667]
  PIN q[668]
    DIRECTION OUTPUT ;
    USE SIGNAL ;
    PORT
      LAYER M4 ;
        RECT  0 72.768 0.084 72.792 ;
    END
  END q[668]
  PIN q[669]
    DIRECTION OUTPUT ;
    USE SIGNAL ;
    PORT
      LAYER M4 ;
        RECT  0 72.864 0.084 72.888 ;
    END
  END q[669]
  PIN q[66]
    DIRECTION OUTPUT ;
    USE SIGNAL ;
    PORT
      LAYER M4 ;
        RECT  0 14.016 0.084 14.04 ;
    END
  END q[66]
  PIN q[670]
    DIRECTION OUTPUT ;
    USE SIGNAL ;
    PORT
      LAYER M4 ;
        RECT  0 72.96 0.084 72.984 ;
    END
  END q[670]
  PIN q[671]
    DIRECTION OUTPUT ;
    USE SIGNAL ;
    PORT
      LAYER M4 ;
        RECT  0 73.056 0.084 73.08 ;
    END
  END q[671]
  PIN q[672]
    DIRECTION OUTPUT ;
    USE SIGNAL ;
    PORT
      LAYER M4 ;
        RECT  0 73.152 0.084 73.176 ;
    END
  END q[672]
  PIN q[673]
    DIRECTION OUTPUT ;
    USE SIGNAL ;
    PORT
      LAYER M4 ;
        RECT  0 73.248 0.084 73.272 ;
    END
  END q[673]
  PIN q[674]
    DIRECTION OUTPUT ;
    USE SIGNAL ;
    PORT
      LAYER M4 ;
        RECT  0 73.344 0.084 73.368 ;
    END
  END q[674]
  PIN q[675]
    DIRECTION OUTPUT ;
    USE SIGNAL ;
    PORT
      LAYER M4 ;
        RECT  0 73.44 0.084 73.464 ;
    END
  END q[675]
  PIN q[676]
    DIRECTION OUTPUT ;
    USE SIGNAL ;
    PORT
      LAYER M4 ;
        RECT  0 73.536 0.084 73.56 ;
    END
  END q[676]
  PIN q[677]
    DIRECTION OUTPUT ;
    USE SIGNAL ;
    PORT
      LAYER M4 ;
        RECT  0 73.632 0.084 73.656 ;
    END
  END q[677]
  PIN q[678]
    DIRECTION OUTPUT ;
    USE SIGNAL ;
    PORT
      LAYER M4 ;
        RECT  0 73.728 0.084 73.752 ;
    END
  END q[678]
  PIN q[679]
    DIRECTION OUTPUT ;
    USE SIGNAL ;
    PORT
      LAYER M4 ;
        RECT  0 73.824 0.084 73.848 ;
    END
  END q[679]
  PIN q[67]
    DIRECTION OUTPUT ;
    USE SIGNAL ;
    PORT
      LAYER M4 ;
        RECT  0 14.112 0.084 14.136 ;
    END
  END q[67]
  PIN q[680]
    DIRECTION OUTPUT ;
    USE SIGNAL ;
    PORT
      LAYER M4 ;
        RECT  0 73.92 0.084 73.944 ;
    END
  END q[680]
  PIN q[681]
    DIRECTION OUTPUT ;
    USE SIGNAL ;
    PORT
      LAYER M4 ;
        RECT  0 74.112 0.084 74.136 ;
    END
  END q[681]
  PIN q[682]
    DIRECTION OUTPUT ;
    USE SIGNAL ;
    PORT
      LAYER M4 ;
        RECT  0 74.016 0.084 74.04 ;
    END
  END q[682]
  PIN q[683]
    DIRECTION OUTPUT ;
    USE SIGNAL ;
    PORT
      LAYER M4 ;
        RECT  0 74.304 0.084 74.328 ;
    END
  END q[683]
  PIN q[684]
    DIRECTION OUTPUT ;
    USE SIGNAL ;
    PORT
      LAYER M4 ;
        RECT  0 74.208 0.084 74.232 ;
    END
  END q[684]
  PIN q[685]
    DIRECTION OUTPUT ;
    USE SIGNAL ;
    PORT
      LAYER M4 ;
        RECT  0 74.4 0.084 74.424 ;
    END
  END q[685]
  PIN q[686]
    DIRECTION OUTPUT ;
    USE SIGNAL ;
    PORT
      LAYER M4 ;
        RECT  0 74.496 0.084 74.52 ;
    END
  END q[686]
  PIN q[687]
    DIRECTION OUTPUT ;
    USE SIGNAL ;
    PORT
      LAYER M4 ;
        RECT  0 74.592 0.084 74.616 ;
    END
  END q[687]
  PIN q[688]
    DIRECTION OUTPUT ;
    USE SIGNAL ;
    PORT
      LAYER M4 ;
        RECT  0 74.688 0.084 74.712 ;
    END
  END q[688]
  PIN q[689]
    DIRECTION OUTPUT ;
    USE SIGNAL ;
    PORT
      LAYER M4 ;
        RECT  0 74.784 0.084 74.808 ;
    END
  END q[689]
  PIN q[68]
    DIRECTION OUTPUT ;
    USE SIGNAL ;
    PORT
      LAYER M4 ;
        RECT  0 14.304 0.084 14.328 ;
    END
  END q[68]
  PIN q[690]
    DIRECTION OUTPUT ;
    USE SIGNAL ;
    PORT
      LAYER M4 ;
        RECT  0 74.88 0.084 74.904 ;
    END
  END q[690]
  PIN q[691]
    DIRECTION OUTPUT ;
    USE SIGNAL ;
    PORT
      LAYER M4 ;
        RECT  0 75.072 0.084 75.096 ;
    END
  END q[691]
  PIN q[692]
    DIRECTION OUTPUT ;
    USE SIGNAL ;
    PORT
      LAYER M4 ;
        RECT  0 74.976 0.084 75 ;
    END
  END q[692]
  PIN q[693]
    DIRECTION OUTPUT ;
    USE SIGNAL ;
    PORT
      LAYER M4 ;
        RECT  0 75.168 0.084 75.192 ;
    END
  END q[693]
  PIN q[694]
    DIRECTION OUTPUT ;
    USE SIGNAL ;
    PORT
      LAYER M4 ;
        RECT  0 75.264 0.084 75.288 ;
    END
  END q[694]
  PIN q[695]
    DIRECTION OUTPUT ;
    USE SIGNAL ;
    PORT
      LAYER M4 ;
        RECT  0 75.36 0.084 75.384 ;
    END
  END q[695]
  PIN q[696]
    DIRECTION OUTPUT ;
    USE SIGNAL ;
    PORT
      LAYER M4 ;
        RECT  0 75.456 0.084 75.48 ;
    END
  END q[696]
  PIN q[697]
    DIRECTION OUTPUT ;
    USE SIGNAL ;
    PORT
      LAYER M4 ;
        RECT  0 75.552 0.084 75.576 ;
    END
  END q[697]
  PIN q[698]
    DIRECTION OUTPUT ;
    USE SIGNAL ;
    PORT
      LAYER M4 ;
        RECT  0 75.648 0.084 75.672 ;
    END
  END q[698]
  PIN q[699]
    DIRECTION OUTPUT ;
    USE SIGNAL ;
    PORT
      LAYER M4 ;
        RECT  0 75.744 0.084 75.768 ;
    END
  END q[699]
  PIN q[69]
    DIRECTION OUTPUT ;
    USE SIGNAL ;
    PORT
      LAYER M4 ;
        RECT  0 14.208 0.084 14.232 ;
    END
  END q[69]
  PIN q[6]
    DIRECTION OUTPUT ;
    USE SIGNAL ;
    PORT
      LAYER M4 ;
        RECT  0 8.256 0.084 8.28 ;
    END
  END q[6]
  PIN q[700]
    DIRECTION OUTPUT ;
    USE SIGNAL ;
    PORT
      LAYER M4 ;
        RECT  0 75.84 0.084 75.864 ;
    END
  END q[700]
  PIN q[701]
    DIRECTION OUTPUT ;
    USE SIGNAL ;
    PORT
      LAYER M4 ;
        RECT  0 75.936 0.084 75.96 ;
    END
  END q[701]
  PIN q[702]
    DIRECTION OUTPUT ;
    USE SIGNAL ;
    PORT
      LAYER M4 ;
        RECT  0 76.032 0.084 76.056 ;
    END
  END q[702]
  PIN q[703]
    DIRECTION OUTPUT ;
    USE SIGNAL ;
    PORT
      LAYER M4 ;
        RECT  0 76.224 0.084 76.248 ;
    END
  END q[703]
  PIN q[704]
    DIRECTION OUTPUT ;
    USE SIGNAL ;
    PORT
      LAYER M4 ;
        RECT  0 76.128 0.084 76.152 ;
    END
  END q[704]
  PIN q[705]
    DIRECTION OUTPUT ;
    USE SIGNAL ;
    PORT
      LAYER M4 ;
        RECT  0 76.32 0.084 76.344 ;
    END
  END q[705]
  PIN q[706]
    DIRECTION OUTPUT ;
    USE SIGNAL ;
    PORT
      LAYER M4 ;
        RECT  0 76.416 0.084 76.44 ;
    END
  END q[706]
  PIN q[707]
    DIRECTION OUTPUT ;
    USE SIGNAL ;
    PORT
      LAYER M4 ;
        RECT  0 76.512 0.084 76.536 ;
    END
  END q[707]
  PIN q[708]
    DIRECTION OUTPUT ;
    USE SIGNAL ;
    PORT
      LAYER M4 ;
        RECT  0 76.608 0.084 76.632 ;
    END
  END q[708]
  PIN q[709]
    DIRECTION OUTPUT ;
    USE SIGNAL ;
    PORT
      LAYER M4 ;
        RECT  0 76.704 0.084 76.728 ;
    END
  END q[709]
  PIN q[70]
    DIRECTION OUTPUT ;
    USE SIGNAL ;
    PORT
      LAYER M4 ;
        RECT  0 14.4 0.084 14.424 ;
    END
  END q[70]
  PIN q[710]
    DIRECTION OUTPUT ;
    USE SIGNAL ;
    PORT
      LAYER M4 ;
        RECT  0 76.8 0.084 76.824 ;
    END
  END q[710]
  PIN q[711]
    DIRECTION OUTPUT ;
    USE SIGNAL ;
    PORT
      LAYER M4 ;
        RECT  0 76.992 0.084 77.016 ;
    END
  END q[711]
  PIN q[712]
    DIRECTION OUTPUT ;
    USE SIGNAL ;
    PORT
      LAYER M4 ;
        RECT  0 76.896 0.084 76.92 ;
    END
  END q[712]
  PIN q[713]
    DIRECTION OUTPUT ;
    USE SIGNAL ;
    PORT
      LAYER M4 ;
        RECT  0 77.088 0.084 77.112 ;
    END
  END q[713]
  PIN q[714]
    DIRECTION OUTPUT ;
    USE SIGNAL ;
    PORT
      LAYER M4 ;
        RECT  0 77.184 0.084 77.208 ;
    END
  END q[714]
  PIN q[715]
    DIRECTION OUTPUT ;
    USE SIGNAL ;
    PORT
      LAYER M4 ;
        RECT  0 77.28 0.084 77.304 ;
    END
  END q[715]
  PIN q[716]
    DIRECTION OUTPUT ;
    USE SIGNAL ;
    PORT
      LAYER M4 ;
        RECT  0 77.376 0.084 77.4 ;
    END
  END q[716]
  PIN q[717]
    DIRECTION OUTPUT ;
    USE SIGNAL ;
    PORT
      LAYER M4 ;
        RECT  0 77.472 0.084 77.496 ;
    END
  END q[717]
  PIN q[718]
    DIRECTION OUTPUT ;
    USE SIGNAL ;
    PORT
      LAYER M4 ;
        RECT  0 77.568 0.084 77.592 ;
    END
  END q[718]
  PIN q[719]
    DIRECTION OUTPUT ;
    USE SIGNAL ;
    PORT
      LAYER M4 ;
        RECT  0 77.664 0.084 77.688 ;
    END
  END q[719]
  PIN q[71]
    DIRECTION OUTPUT ;
    USE SIGNAL ;
    PORT
      LAYER M4 ;
        RECT  0 14.496 0.084 14.52 ;
    END
  END q[71]
  PIN q[720]
    DIRECTION OUTPUT ;
    USE SIGNAL ;
    PORT
      LAYER M4 ;
        RECT  0 77.76 0.084 77.784 ;
    END
  END q[720]
  PIN q[721]
    DIRECTION OUTPUT ;
    USE SIGNAL ;
    PORT
      LAYER M4 ;
        RECT  0 77.856 0.084 77.88 ;
    END
  END q[721]
  PIN q[722]
    DIRECTION OUTPUT ;
    USE SIGNAL ;
    PORT
      LAYER M4 ;
        RECT  0 77.952 0.084 77.976 ;
    END
  END q[722]
  PIN q[723]
    DIRECTION OUTPUT ;
    USE SIGNAL ;
    PORT
      LAYER M4 ;
        RECT  0 78.24 0.084 78.264 ;
    END
  END q[723]
  PIN q[724]
    DIRECTION OUTPUT ;
    USE SIGNAL ;
    PORT
      LAYER M4 ;
        RECT  0 78.048 0.084 78.072 ;
    END
  END q[724]
  PIN q[725]
    DIRECTION OUTPUT ;
    USE SIGNAL ;
    PORT
      LAYER M4 ;
        RECT  0 78.336 0.084 78.36 ;
    END
  END q[725]
  PIN q[726]
    DIRECTION OUTPUT ;
    USE SIGNAL ;
    PORT
      LAYER M4 ;
        RECT  0 78.144 0.084 78.168 ;
    END
  END q[726]
  PIN q[727]
    DIRECTION OUTPUT ;
    USE SIGNAL ;
    PORT
      LAYER M4 ;
        RECT  0 78.432 0.084 78.456 ;
    END
  END q[727]
  PIN q[728]
    DIRECTION OUTPUT ;
    USE SIGNAL ;
    PORT
      LAYER M4 ;
        RECT  0 78.528 0.084 78.552 ;
    END
  END q[728]
  PIN q[729]
    DIRECTION OUTPUT ;
    USE SIGNAL ;
    PORT
      LAYER M4 ;
        RECT  0 78.624 0.084 78.648 ;
    END
  END q[729]
  PIN q[72]
    DIRECTION OUTPUT ;
    USE SIGNAL ;
    PORT
      LAYER M4 ;
        RECT  0 14.592 0.084 14.616 ;
    END
  END q[72]
  PIN q[730]
    DIRECTION OUTPUT ;
    USE SIGNAL ;
    PORT
      LAYER M4 ;
        RECT  0 78.72 0.084 78.744 ;
    END
  END q[730]
  PIN q[731]
    DIRECTION OUTPUT ;
    USE SIGNAL ;
    PORT
      LAYER M4 ;
        RECT  0 78.816 0.084 78.84 ;
    END
  END q[731]
  PIN q[732]
    DIRECTION OUTPUT ;
    USE SIGNAL ;
    PORT
      LAYER M4 ;
        RECT  0 78.912 0.084 78.936 ;
    END
  END q[732]
  PIN q[733]
    DIRECTION OUTPUT ;
    USE SIGNAL ;
    PORT
      LAYER M4 ;
        RECT  0 79.008 0.084 79.032 ;
    END
  END q[733]
  PIN q[734]
    DIRECTION OUTPUT ;
    USE SIGNAL ;
    PORT
      LAYER M4 ;
        RECT  0 79.104 0.084 79.128 ;
    END
  END q[734]
  PIN q[735]
    DIRECTION OUTPUT ;
    USE SIGNAL ;
    PORT
      LAYER M4 ;
        RECT  0 79.2 0.084 79.224 ;
    END
  END q[735]
  PIN q[736]
    DIRECTION OUTPUT ;
    USE SIGNAL ;
    PORT
      LAYER M4 ;
        RECT  0 79.296 0.084 79.32 ;
    END
  END q[736]
  PIN q[737]
    DIRECTION OUTPUT ;
    USE SIGNAL ;
    PORT
      LAYER M4 ;
        RECT  0 79.488 0.084 79.512 ;
    END
  END q[737]
  PIN q[738]
    DIRECTION OUTPUT ;
    USE SIGNAL ;
    PORT
      LAYER M4 ;
        RECT  0 79.392 0.084 79.416 ;
    END
  END q[738]
  PIN q[739]
    DIRECTION OUTPUT ;
    USE SIGNAL ;
    PORT
      LAYER M4 ;
        RECT  0 79.584 0.084 79.608 ;
    END
  END q[739]
  PIN q[73]
    DIRECTION OUTPUT ;
    USE SIGNAL ;
    PORT
      LAYER M4 ;
        RECT  0 14.688 0.084 14.712 ;
    END
  END q[73]
  PIN q[740]
    DIRECTION OUTPUT ;
    USE SIGNAL ;
    PORT
      LAYER M4 ;
        RECT  0 79.68 0.084 79.704 ;
    END
  END q[740]
  PIN q[741]
    DIRECTION OUTPUT ;
    USE SIGNAL ;
    PORT
      LAYER M4 ;
        RECT  0 79.776 0.084 79.8 ;
    END
  END q[741]
  PIN q[742]
    DIRECTION OUTPUT ;
    USE SIGNAL ;
    PORT
      LAYER M4 ;
        RECT  0 79.872 0.084 79.896 ;
    END
  END q[742]
  PIN q[743]
    DIRECTION OUTPUT ;
    USE SIGNAL ;
    PORT
      LAYER M4 ;
        RECT  0 80.064 0.084 80.088 ;
    END
  END q[743]
  PIN q[744]
    DIRECTION OUTPUT ;
    USE SIGNAL ;
    PORT
      LAYER M4 ;
        RECT  0 79.968 0.084 79.992 ;
    END
  END q[744]
  PIN q[745]
    DIRECTION OUTPUT ;
    USE SIGNAL ;
    PORT
      LAYER M4 ;
        RECT  0 80.256 0.084 80.28 ;
    END
  END q[745]
  PIN q[746]
    DIRECTION OUTPUT ;
    USE SIGNAL ;
    PORT
      LAYER M4 ;
        RECT  0 80.16 0.084 80.184 ;
    END
  END q[746]
  PIN q[747]
    DIRECTION OUTPUT ;
    USE SIGNAL ;
    PORT
      LAYER M4 ;
        RECT  0 80.352 0.084 80.376 ;
    END
  END q[747]
  PIN q[748]
    DIRECTION OUTPUT ;
    USE SIGNAL ;
    PORT
      LAYER M4 ;
        RECT  0 80.448 0.084 80.472 ;
    END
  END q[748]
  PIN q[749]
    DIRECTION OUTPUT ;
    USE SIGNAL ;
    PORT
      LAYER M4 ;
        RECT  0 80.64 0.084 80.664 ;
    END
  END q[749]
  PIN q[74]
    DIRECTION OUTPUT ;
    USE SIGNAL ;
    PORT
      LAYER M4 ;
        RECT  0 14.784 0.084 14.808 ;
    END
  END q[74]
  PIN q[750]
    DIRECTION OUTPUT ;
    USE SIGNAL ;
    PORT
      LAYER M4 ;
        RECT  0 80.544 0.084 80.568 ;
    END
  END q[750]
  PIN q[751]
    DIRECTION OUTPUT ;
    USE SIGNAL ;
    PORT
      LAYER M4 ;
        RECT  0 80.736 0.084 80.76 ;
    END
  END q[751]
  PIN q[752]
    DIRECTION OUTPUT ;
    USE SIGNAL ;
    PORT
      LAYER M4 ;
        RECT  0 80.832 0.084 80.856 ;
    END
  END q[752]
  PIN q[753]
    DIRECTION OUTPUT ;
    USE SIGNAL ;
    PORT
      LAYER M4 ;
        RECT  0 80.928 0.084 80.952 ;
    END
  END q[753]
  PIN q[754]
    DIRECTION OUTPUT ;
    USE SIGNAL ;
    PORT
      LAYER M4 ;
        RECT  0 81.024 0.084 81.048 ;
    END
  END q[754]
  PIN q[755]
    DIRECTION OUTPUT ;
    USE SIGNAL ;
    PORT
      LAYER M4 ;
        RECT  0 81.12 0.084 81.144 ;
    END
  END q[755]
  PIN q[756]
    DIRECTION OUTPUT ;
    USE SIGNAL ;
    PORT
      LAYER M4 ;
        RECT  0 81.216 0.084 81.24 ;
    END
  END q[756]
  PIN q[757]
    DIRECTION OUTPUT ;
    USE SIGNAL ;
    PORT
      LAYER M4 ;
        RECT  0 81.408 0.084 81.432 ;
    END
  END q[757]
  PIN q[758]
    DIRECTION OUTPUT ;
    USE SIGNAL ;
    PORT
      LAYER M4 ;
        RECT  0 81.312 0.084 81.336 ;
    END
  END q[758]
  PIN q[759]
    DIRECTION OUTPUT ;
    USE SIGNAL ;
    PORT
      LAYER M4 ;
        RECT  0 81.504 0.084 81.528 ;
    END
  END q[759]
  PIN q[75]
    DIRECTION OUTPUT ;
    USE SIGNAL ;
    PORT
      LAYER M4 ;
        RECT  0 14.88 0.084 14.904 ;
    END
  END q[75]
  PIN q[760]
    DIRECTION OUTPUT ;
    USE SIGNAL ;
    PORT
      LAYER M4 ;
        RECT  0 81.6 0.084 81.624 ;
    END
  END q[760]
  PIN q[761]
    DIRECTION OUTPUT ;
    USE SIGNAL ;
    PORT
      LAYER M4 ;
        RECT  0 81.792 0.084 81.816 ;
    END
  END q[761]
  PIN q[762]
    DIRECTION OUTPUT ;
    USE SIGNAL ;
    PORT
      LAYER M4 ;
        RECT  0 81.696 0.084 81.72 ;
    END
  END q[762]
  PIN q[763]
    DIRECTION OUTPUT ;
    USE SIGNAL ;
    PORT
      LAYER M4 ;
        RECT  0 81.888 0.084 81.912 ;
    END
  END q[763]
  PIN q[764]
    DIRECTION OUTPUT ;
    USE SIGNAL ;
    PORT
      LAYER M4 ;
        RECT  0 81.984 0.084 82.008 ;
    END
  END q[764]
  PIN q[765]
    DIRECTION OUTPUT ;
    USE SIGNAL ;
    PORT
      LAYER M4 ;
        RECT  0 82.176 0.084 82.2 ;
    END
  END q[765]
  PIN q[766]
    DIRECTION OUTPUT ;
    USE SIGNAL ;
    PORT
      LAYER M4 ;
        RECT  0 82.08 0.084 82.104 ;
    END
  END q[766]
  PIN q[76]
    DIRECTION OUTPUT ;
    USE SIGNAL ;
    PORT
      LAYER M4 ;
        RECT  0 14.976 0.084 15 ;
    END
  END q[76]
  PIN q[77]
    DIRECTION OUTPUT ;
    USE SIGNAL ;
    PORT
      LAYER M4 ;
        RECT  0 15.072 0.084 15.096 ;
    END
  END q[77]
  PIN q[78]
    DIRECTION OUTPUT ;
    USE SIGNAL ;
    PORT
      LAYER M4 ;
        RECT  0 15.168 0.084 15.192 ;
    END
  END q[78]
  PIN q[79]
    DIRECTION OUTPUT ;
    USE SIGNAL ;
    PORT
      LAYER M4 ;
        RECT  0 15.264 0.084 15.288 ;
    END
  END q[79]
  PIN q[7]
    DIRECTION OUTPUT ;
    USE SIGNAL ;
    PORT
      LAYER M4 ;
        RECT  0 8.352 0.084 8.376 ;
    END
  END q[7]
  PIN q[80]
    DIRECTION OUTPUT ;
    USE SIGNAL ;
    PORT
      LAYER M4 ;
        RECT  0 15.36 0.084 15.384 ;
    END
  END q[80]
  PIN q[81]
    DIRECTION OUTPUT ;
    USE SIGNAL ;
    PORT
      LAYER M4 ;
        RECT  0 15.456 0.084 15.48 ;
    END
  END q[81]
  PIN q[82]
    DIRECTION OUTPUT ;
    USE SIGNAL ;
    PORT
      LAYER M4 ;
        RECT  0 15.552 0.084 15.576 ;
    END
  END q[82]
  PIN q[83]
    DIRECTION OUTPUT ;
    USE SIGNAL ;
    PORT
      LAYER M4 ;
        RECT  0 15.648 0.084 15.672 ;
    END
  END q[83]
  PIN q[84]
    DIRECTION OUTPUT ;
    USE SIGNAL ;
    PORT
      LAYER M4 ;
        RECT  0 15.84 0.084 15.864 ;
    END
  END q[84]
  PIN q[85]
    DIRECTION OUTPUT ;
    USE SIGNAL ;
    PORT
      LAYER M4 ;
        RECT  0 15.744 0.084 15.768 ;
    END
  END q[85]
  PIN q[86]
    DIRECTION OUTPUT ;
    USE SIGNAL ;
    PORT
      LAYER M4 ;
        RECT  0 15.936 0.084 15.96 ;
    END
  END q[86]
  PIN q[87]
    DIRECTION OUTPUT ;
    USE SIGNAL ;
    PORT
      LAYER M4 ;
        RECT  0 16.032 0.084 16.056 ;
    END
  END q[87]
  PIN q[88]
    DIRECTION OUTPUT ;
    USE SIGNAL ;
    PORT
      LAYER M4 ;
        RECT  0 16.128 0.084 16.152 ;
    END
  END q[88]
  PIN q[89]
    DIRECTION OUTPUT ;
    USE SIGNAL ;
    PORT
      LAYER M4 ;
        RECT  0 16.224 0.084 16.248 ;
    END
  END q[89]
  PIN q[8]
    DIRECTION OUTPUT ;
    USE SIGNAL ;
    PORT
      LAYER M4 ;
        RECT  0 8.448 0.084 8.472 ;
    END
  END q[8]
  PIN q[90]
    DIRECTION OUTPUT ;
    USE SIGNAL ;
    PORT
      LAYER M4 ;
        RECT  0 16.32 0.084 16.344 ;
    END
  END q[90]
  PIN q[91]
    DIRECTION OUTPUT ;
    USE SIGNAL ;
    PORT
      LAYER M4 ;
        RECT  0 16.416 0.084 16.44 ;
    END
  END q[91]
  PIN q[92]
    DIRECTION OUTPUT ;
    USE SIGNAL ;
    PORT
      LAYER M4 ;
        RECT  0 16.512 0.084 16.536 ;
    END
  END q[92]
  PIN q[93]
    DIRECTION OUTPUT ;
    USE SIGNAL ;
    PORT
      LAYER M4 ;
        RECT  0 16.608 0.084 16.632 ;
    END
  END q[93]
  PIN q[94]
    DIRECTION OUTPUT ;
    USE SIGNAL ;
    PORT
      LAYER M4 ;
        RECT  0 16.704 0.084 16.728 ;
    END
  END q[94]
  PIN q[95]
    DIRECTION OUTPUT ;
    USE SIGNAL ;
    PORT
      LAYER M4 ;
        RECT  0 16.8 0.084 16.824 ;
    END
  END q[95]
  PIN q[96]
    DIRECTION OUTPUT ;
    USE SIGNAL ;
    PORT
      LAYER M4 ;
        RECT  0 16.896 0.084 16.92 ;
    END
  END q[96]
  PIN q[97]
    DIRECTION OUTPUT ;
    USE SIGNAL ;
    PORT
      LAYER M4 ;
        RECT  0 16.992 0.084 17.016 ;
    END
  END q[97]
  PIN q[98]
    DIRECTION OUTPUT ;
    USE SIGNAL ;
    PORT
      LAYER M4 ;
        RECT  0 17.088 0.084 17.112 ;
    END
  END q[98]
  PIN q[99]
    DIRECTION OUTPUT ;
    USE SIGNAL ;
    PORT
      LAYER M4 ;
        RECT  0 17.184 0.084 17.208 ;
    END
  END q[99]
  PIN q[9]
    DIRECTION OUTPUT ;
    USE SIGNAL ;
    PORT
      LAYER M4 ;
        RECT  0 8.544 0.084 8.568 ;
    END
  END q[9]
  PIN ready
    DIRECTION OUTPUT ;
    USE SIGNAL ;
    PORT
      LAYER M4 ;
        RECT  0 44.64 0.084 44.664 ;
    END
  END ready
  PIN rst_n
    DIRECTION INPUT ;
    USE SIGNAL ;
    PORT
      LAYER M4 ;
        RECT  0 44.544 0.084 44.568 ;
    END
  END rst_n
  PIN strap_k[0]
    DIRECTION INPUT ;
    USE SIGNAL ;
    PORT
      LAYER M4 ;
        RECT  0 44.832 0.084 44.856 ;
    END
  END strap_k[0]
  PIN strap_k[1]
    DIRECTION INPUT ;
    USE SIGNAL ;
    PORT
      LAYER M4 ;
        RECT  0 44.928 0.084 44.952 ;
    END
  END strap_k[1]
  PIN strap_k[2]
    DIRECTION INPUT ;
    USE SIGNAL ;
    PORT
      LAYER M4 ;
        RECT  0 45.024 0.084 45.048 ;
    END
  END strap_k[2]
  PIN strap_k[3]
    DIRECTION INPUT ;
    USE SIGNAL ;
    PORT
      LAYER M4 ;
        RECT  0 45.12 0.084 45.144 ;
    END
  END strap_k[3]
  PIN strap_k[4]
    DIRECTION INPUT ;
    USE SIGNAL ;
    PORT
      LAYER M4 ;
        RECT  0 45.216 0.084 45.24 ;
    END
  END strap_k[4]
  PIN strap_k[5]
    DIRECTION INPUT ;
    USE SIGNAL ;
    PORT
      LAYER M4 ;
        RECT  0 45.312 0.084 45.336 ;
    END
  END strap_k[5]
  PIN t_rst_n
    DIRECTION INPUT ;
    USE SIGNAL ;
    PORT
      LAYER M4 ;
        RECT  77.676 44.928 77.76 44.952 ;
    END
  END t_rst_n
  PIN VDD
    DIRECTION INOUT ;
    USE POWER ;
    PORT
      LAYER M5 ;
        RECT  71.316 4.311 71.436 85.329 ;
        RECT  66.996 4.311 67.116 85.329 ;
        RECT  62.676 4.311 62.796 85.329 ;
        RECT  58.356 4.311 58.476 85.329 ;
        RECT  54.036 4.311 54.156 85.329 ;
        RECT  49.716 4.311 49.836 85.329 ;
        RECT  45.396 4.311 45.516 85.329 ;
        RECT  41.076 4.311 41.196 85.329 ;
        RECT  36.756 4.311 36.876 85.329 ;
        RECT  32.436 4.311 32.556 85.329 ;
        RECT  28.116 4.311 28.236 85.329 ;
        RECT  23.796 4.311 23.916 85.329 ;
        RECT  19.476 4.311 19.596 85.329 ;
        RECT  15.156 4.311 15.276 85.329 ;
        RECT  10.836 4.311 10.956 85.329 ;
        RECT  6.516 4.311 6.636 85.329 ;
    END
  END VDD
  PIN VSS
    DIRECTION INOUT ;
    USE GROUND ;
    PORT
      LAYER M5 ;
        RECT  71.124 4.297 71.244 85.343 ;
        RECT  66.804 4.297 66.924 85.343 ;
        RECT  62.484 4.297 62.604 85.343 ;
        RECT  58.164 4.297 58.284 85.343 ;
        RECT  53.844 4.297 53.964 85.343 ;
        RECT  49.524 4.297 49.644 85.343 ;
        RECT  45.204 4.297 45.324 85.343 ;
        RECT  40.884 4.297 41.004 85.343 ;
        RECT  36.564 4.297 36.684 85.343 ;
        RECT  32.244 4.297 32.364 85.343 ;
        RECT  27.924 4.297 28.044 85.343 ;
        RECT  23.604 4.297 23.724 85.343 ;
        RECT  19.284 4.297 19.404 85.343 ;
        RECT  14.964 4.297 15.084 85.343 ;
        RECT  10.644 4.297 10.764 85.343 ;
        RECT  6.324 4.297 6.444 85.343 ;
    END
  END VSS
  OBS
    LAYER RVTN ;
     RECT  0 4.189 77.76 85.379 ;
    LAYER RVTP ;
     RECT  0 4.189 77.76 85.379 ;
    LAYER M1 ;
     RECT  0 4.189 77.76 85.379 ;
    LAYER M2 ;
     RECT  0 4.189 77.76 85.379 ;
    LAYER M3 ;
     RECT  0 4.189 77.76 85.379 ;
    LAYER M4 ;
     RECT  0 4.189 77.76 85.379 ;
    LAYER M5 ;
     RECT  0 4.189 77.76 85.379 ;
  END
END sle_cland_w767_e_200
END LIBRARY
